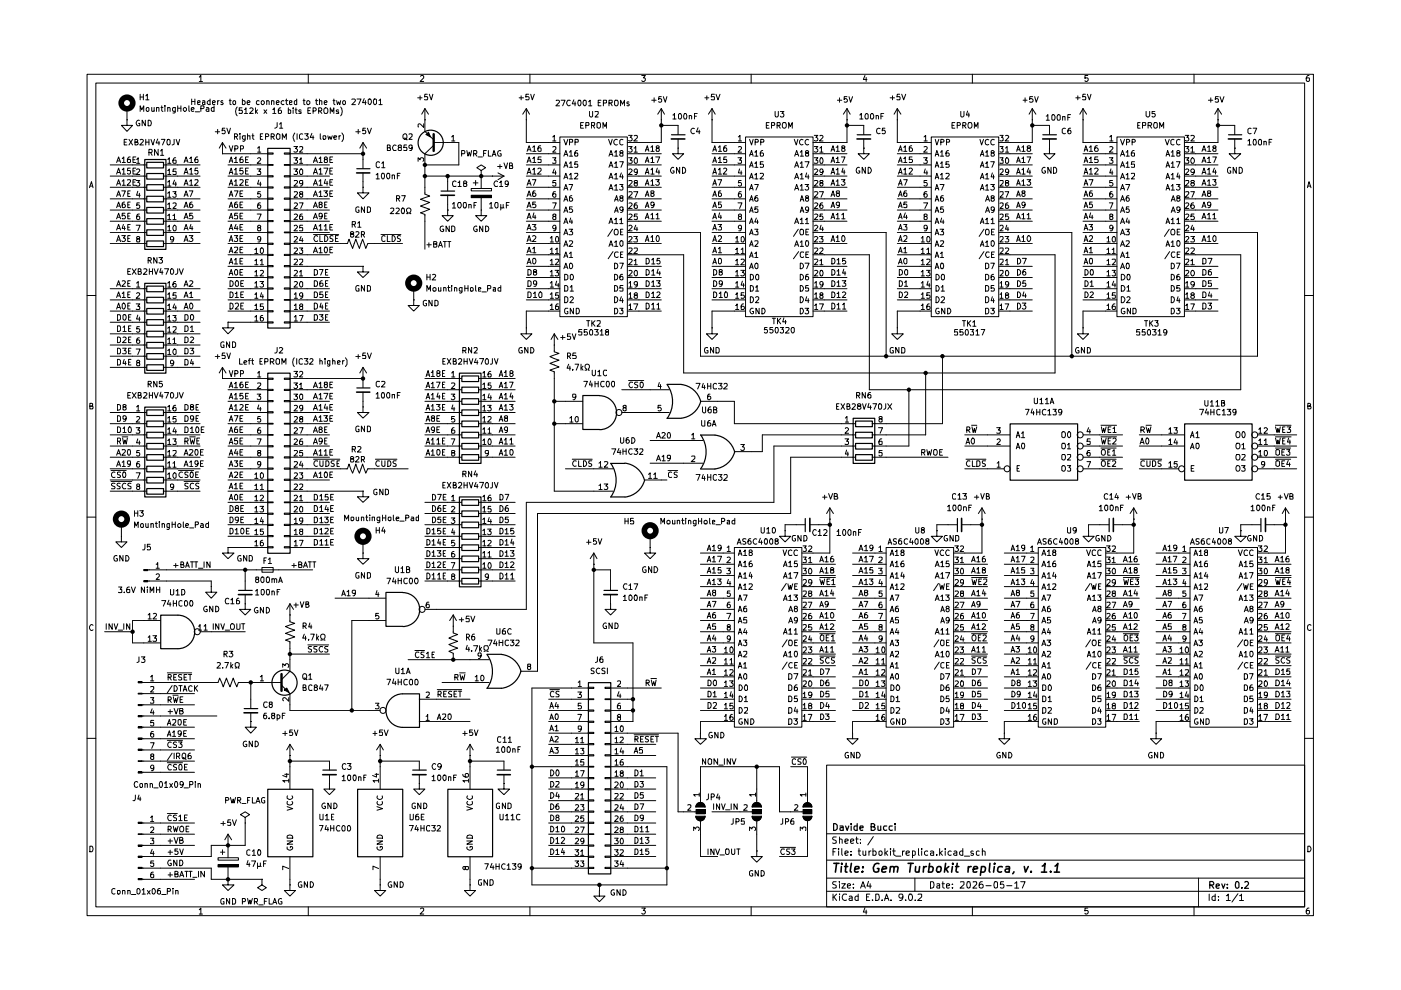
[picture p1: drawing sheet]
<svg xmlns="http://www.w3.org/2000/svg" width="297mm" height="210mm" viewBox="0 0 297 210" stroke-linecap="round" stroke-linejoin="round" font-family="sans-serif">
<g fill="none" stroke="#000" stroke-width=".21">
<path d="M18.5 15.7h260v178.4h-260zM20.3 17.6h256.3v174.7h-256.3zM29.7 20v1.2M30.4 20v1.2M42.2 16.3l.4-.3v1.3M42.2 17.3h.7M65.4 15.7v1.9M89.2 16.2l.1-.2h.4l.1 .2v.3l-.7 .8h.7M90.6 20h-.5l-.1 .6 .6-.1v.7l-.6-.1M91 20l.4 1.2 .4-1.2M112.1 20h-.6v.6l.5-.1 .2 .2v.3l-.2 .2-.5-.1M112.4 15.7v1.9"/>
<path d="M112.5 20l.4 1.2 .4-1.2M136.1 16h.7l-.4 .5 .4 .2v.3l-.2 .3h-.4l-.1-.2M151.5 20h-.6l-.1 .6 .6-.1 .1 .6h-.7M151.8 20l.4 1.2 .5-1.2M159.3 15.7v1.9M183.4 16l-.4 .8h.8M183.6 16.4v.9M190.8 20h-.6v.6l.6-.1v.7l-.6-.1M191.2 20l.4 1.2 .4-1.2M206.2 15.7v1.9M230.1 20h-.5l-.1 .6 .6-.1v.7l-.6-.1M230.5 20l.5 1.2 .3-1.2"/>
<path d="M230.6 16h-.6v.6l.5-.1 .2 .2v.3l-.2 .3-.5-.2M253.2 15.7v1.9M277.5 16h-.2a.93 .93 0 0 0-.3 1.2l.5 .1 .1-.2v-.5l-.6-.1-.1 .2M19 39.8l.4-1.3 .3 1.3M19.1 39.5h.5M23.4 35h7.7M23.4 37.3h7.7M23.4 39.7h7.7M24.7 39.3l.4-1.2 .5 1.2M24.7 36.9l.4-1.3 .5 1.3M24.7 34.5l.4-1.2 .5 1.2M24.9 38.9h.5"/>
<path d="M24.9 36.6h.5M24.9 34.1h.5M25.9 38.4l.3-.3v1.2M25.9 36l.3-.4v1.3M25.9 33.6l.3-.3v1.2M25.9 39.3h.7M25.9 36.9h.7M25.9 34.5h.7M26.3 30.1h.5M26.9 25.4v1.2h1.2l-1.2 1.3-1.2-1.3h1.2M26.9 25.4h.1M26.9 29.5h-.6v1.2h.6"/>
<path d="M26.9 23v2.4M27 38.2l.6-.1 .1 .3-.8 .9h.8M27.3 29.5l.8 1.2M27.6 35.6h-.5l-.1 .6h.6v.6l-.4 .1-.2-.2M27.6 33.3h-.3a.93 .93 0 0 0-.2 1.2h.5l.1-.5-.1-.2h-.5l-.1 .2M28.1 29.5l-.8 1.2M28.2 38.6h.4M28.2 36.2h.4M28.2 33.9h.4M28.6 30.1h.5v-.5l-.5-.1v1.2h.4l.3-.4-.3-.2M28.8 38.1h-.6v1.2h.6M28.8 35.6h-.6v1.3h.6"/>
<path d="M28.8 33.3h-.6v1.2h.6M28.9 38.3h.7l-.4 .4 .4 .2-.1 .5-.5 .1-.1-.2M29 33.8l.3-.4v1.2M29 36l.4-.2 .2 .4-.7 .8h.7M29 34.6h.6M29.5 25.6v-.1a.66 .66 0 0 0-.6 .5 .66 .66 0 0 0 .2 .7l.5-.1v-.4h-.2M29.7 29.6l.4-.1 .3 .4-.8 .8h.8M29.7 23.6v-1.2l.4 .9 .4-.9v1.2M29.7 20.6h.7M30.8 25.5v1.2l-.7-1.2v1.2M30.9 20.3l.3-.3v1.2M30.9 30.1h.7"/>
<path d="M30.9 29.5v1.2M30.9 21.2h.7M31.1 22.9l.3-.1 .2 .1v.6l-.2 .1-.4-.2zM31.4 25.5a.66 .66 0 0 1 .7 .4 .66 .66 0 0 1-.3 .8h-.4zM31.6 32.3h.5l.2-.1v-.4l-.2-.1h-.5v1.2M31.6 29.5v1.2M31.9 32.3l.4 .6M32 29.5l.4 1.2 .4-1.2M32.2 22.8v.7l.3 .1 .2-.1M32.7 22.8v.8M33.2 22.9l.2-.1 .3 .1v.7M33.2 22.8v.8"/>
<path d="M33.4 29.5l-.3 .8h.8M33.5 31.7v1.2l-.7-1.2v1.2M33.7 30v.7M34 32l.4-.3v1.2M34 32.9h.7M34.1 22.8h.4M34.2 29.5h.8l-.5 1.2M34.3 22.4v1.1l.2 .1M34.6 35h7.8M34.6 37.3h7.8M34.6 39.7h7.8M35 22.4v.1"/>
<path d="M35 22.8v.8M35.5 29.6h.5l.1 .9a.35 .35 0 0 1-.5 .2 .35 .35 0 0 1-.2-.4zM35.6 33.8l.3-.4v1.2M35.6 36.2l.3-.4v1.2M35.6 38.6l.3-.3v1.2M35.6 22.9l.1-.1 .4 .1v.7M35.6 39.5h.6M35.6 34.6h.6M35.6 37h.6M35.6 22.8v.8M36.9 29.5v1.1l-.4 .1M37 38.2l-.3 .8h.7"/>
<path d="M37.2 22.8v1l-.2 .2h-.3M37.2 22.9l-.4-.1-.2 .2 .1 .5h.5M37.3 33.4l-.5 .2-.1 .9 .1 .1 .5-.1v-.5h-.5l-.1 .1M37.3 38.6v.9M37.3 35.8h-.6v.6l.6-.1v.6h-.6M37.3 29.5l.5 1.2 .3-1.2M37.7 22.4v1.2M37.7 22.9h.7M38.4 22.4v1.2M38.9 23l.4-.2 .2 .2v.4l-.4 .2-.2-.2zM39 39.3l.5-1.2 .4 1.2M39 34.5l.5-1.2 .4 1.2"/>
<path d="M39 36.9l.5-1.3 .4 1.3M39.2 38.9h.5M39.2 36.6h.5M39.2 34.1h.5M40 22.4v1.1l.2 .1M40.2 38.4l.4-.3v1.2M40.2 33.6l.4-.3v1.2M40.2 36l.4-.4v1.3M40.2 39.3h.7M40.2 36.9h.7M40.2 34.5h.7M40.6 23.2l.5-.1-.1-.3-.4 .1v.6l.1 .1 .4-.1"/>
<path d="M40.6 21v1.2M40.6 21.5h.7M41.3 38.2l.6-.1 .1 .3-.8 .9h.8M41.3 21v1.2M41.4 23.7h.9M41.9 33.3h-.2a.93 .93 0 0 0-.3 1.2h.5l.1-.5-.1-.2h-.5l-.1 .2M41.9 35.6h-.5l-.1 .6h.6v.6l-.4 .1-.2-.2M41.9 21.8l.5-.1v-.3h-.5v.7h.5M42.6 23l.6-.1v-.5h-.6v1.2M42.9 21.4h.5v.8M43.4 21.7l-.5 .1v.3h.5M43.8 22.9l.3-.1 .2 .1v.7"/>
<path d="M44.3 23.1h-.4l-.2 .2 .2 .3 .4-.1M44.5 21.4l-.3-.1-.3 .3v.3l.3 .3 .3-.1M44.5 21v1.2M45 21.8l.6-.1-.1-.4-.5 .2v.5l.2 .2 .4-.1M45.4 22.9l-.4-.1-.2 .2 .1 .5h.5M45.4 22.4v1.2M45.6 27.9h1M46.1 21.3v.9M46.1 27.4v1M46.5 21.3l-.4 .3M47.2 32.6h.1M47.2 30.2v2.4"/>
<path d="M47.2 30.2l-.7 1.2M47.2 30.2l.7 1.2M47.2 32.6h9.5M47.2 21.4l-.2-.1-.2 .3 .5 .4-.1 .2-.4-.1M47.7 27.2h-.5l-.1 .6 .1-.2 .5 .1v.6h-.6M48.1 27.2l.4 1.2 .4-1.2M48.3 35h8.4M48.3 37.3h8.4M48.3 39.7h8.4M48.6 34.5l.4-1.2 .4 1.2M48.6 30.9l.4 1.2 .4-1.2M48.6 36.9l.4-1.3 .4 1.3"/>
<path d="M48.6 39.3l.4-1.2 .4 1.2M48.6 21.3h.4M48.7 38.9h.6M48.7 36.6h.6M48.7 34.1h.6M48.8 21v1.1l.2 .1M49.4 21.4l.4-.1 .2 .2v.5l-.2 .2-.4-.3zM49.7 33.6h.2l.1-.3v1.2M49.7 36h.2l.1-.4v1.3M49.7 38.4l.3-.3v1.2M49.7 29h.5l.2-.2-.1-.4h-.6v1.1M49.7 39.3h.7"/>
<path d="M49.7 36.9h.7M49.7 34.5h.7M49.8 31.6l.6-.1v-.5l-.6-.1v1.2M50 29l.4 .5M50.3 22.7a1.44 1.44 0 0 0 0 1.9M50.9 38.2l.5-.1 .2 .3-.8 .9h.8M50.9 28.4h.1M50.9 28.8v.7M51 31.6l.6-.1v-.5l-.6-.1v1.2M51.3 22.9h-.6v.6l.6-.1v.6h-.6M51.4 33.3l-.3 .1-.2 .2v.8l.5 .1 .2-.2v-.3l-.2-.2h-.4l-.1 .2M51.4 21.4l.3-.1 .3 .3-.1 .5h-.5"/>
<path d="M51.4 21v1.2M51.5 35.6h-.6v.6h.5l.2 .5-.3 .2-.4-.2M51.8 23.2h.2l.2-.3v1.1M51.8 24h.7M52 29.5a.36 .36 0 0 1-.6-.2l.1-.5h.5v.9l-.3 .3-.2-.1M52.1 38.6h.4M52.1 36.2h.4M52.1 33.9h.4M52.4 21.8l.6-.1-.2-.4-.4 .2v.5l.2 .2 .3-.1M52.5 28.9l.5-.1v.7M52.5 28.4v1.1M52.7 33.3h-.6v1.2h.6"/>
<path d="M52.7 35.6h-.6v1.3h.6M52.7 38.1h-.6v1.2h.6M53 23l.4-.1 .3 .3-.8 .8h.8M53.4 28.8h.4M53.6 28.4v1l.2 .1M54.2 22.9v1.1M54.3 23.6l.3 .4M54.5 35.8h.8l-.4 .5h.3v.7l-.7-.1M54.6 31.4l.3-.3v1.2M54.6 33.6l.4-.2 .3 .4-.8 .8h.8M54.6 32.3h.7M54.6 23.3l-.4 .4"/>
<path d="M54.9 38.2l-.3 .8h.8M54.9 21.4l-.3-.1-.2 .3v.5h.5M55.2 38.6v.9M55.2 29h.3M55.5 21.4l.3-.1 .2 .3v.3l-.2 .3-.4-.3zM55.7 28.4h-.5v1.1h.5M56 23.3l.6 .7M56.3 29h.5l.2-.2-.1-.4h-.6v1.1M56.6 21.5l.1-.2 .4 .2v.7M56.6 21.3v.9M56.6 23.3l-.6 .7M56.7 32.4h1.2v.3h-1.2z"/>
<path d="M56.7 34.9h1.2v.2h-1.2zM56.7 37.3h1.2v.2h-1.2zM56.7 39.6h1.2v.3h-1.2zM57.5 29h.5l.2-.2-.1-.4h-.6v1.1M57.6 21.5l.1-.2 .4 .1v.8M57.6 21.3v.9M57.7 29l.5 .5M57.8 23.2h.2l.2-.3v1.1M57.8 24h.7M58.6 21.8l.6-.1-.2-.4-.4 .2v.5l.2 .2 .3-.1M58.8 26v.8l-.5 .4M58.8 28.4l.6 .1v.9l-.6 .1a.78 .78 0 0 1 0-1.1z"/>
<path d="M59.3 26.3l.3-.3v1.2M59.3 27.2h.6M59.5 22.9h-.3l-.2 .3v.8h.5l.2-.1v-.4l-.2-.1h-.4l-.1 .1M59.9 29.5v-1.1l.4 .8 .4-.8v1.1M60.2 21.4l-.3-.1-.3 .3v.3l.3 .3 .3-.1M60.3 32.4h1.2v.3h-1.2zM60.3 34.9h1.2v.2h-1.2zM60.3 37.3h1.2v.2h-1.2zM60.3 39.6h1.2v.3h-1.2zM60.5 21.3h.5M60.7 21v1l.3 .2M61.1 22.9v1.1h.5v-.6h-.5"/>
<path d="M61.4 21.8l.5-.1v-.3h-.5v.7h.5M61.5 35h8.4M61.5 37.3h8.4M61.5 39.7h8.4M61.5 32.6h15.5M62.1 22.9v.1M62.1 23.3v.7M62.3 31.1h.8l-.4 .4 .4 .2-.1 .5h-.7M62.3 33.4h.8l-.4 .6 .4 .1v.4l-.2 .1-.6-.1M62.3 35.8h.8l-.4 .5 .4 .2v.3l-.2 .2-.6-.1M62.4 38.4l.5-.1 .2 .3-.8 .9h.8M62.5 28.2a1.32 1.32 0 0 0 0 1.8"/>
<path d="M62.6 23.3h.4M62.7 22.9v1l.3 .1M62.9 21.4l-.3-.1-.2 .2v.5l.2 .2 .3-.1M62.9 21v1.2M63 28.4v1.1M63.5 31.2h.7v.4l-.7 .7h.7M63.5 33.8h.2l.1-.4v1.2M63.5 34.6h.7M63.7 35.9l.2-.1 .3 .3v.7l-.2 .2h-.3l-.2-.4zM63.8 23.4l-.3-.1-.2 .2 .2 .2h.3v.3h-.5M64.2 38.8l-.1 .1h-.4l-.2-.1v-.4l.2-.1 .5 .1v.7l-.2 .3-.3 .1M64.2 28.4a.45 .45 0 0 0-.7 .2v.7a.45 .45 0 0 0 .7 .2"/>
<path d="M64.3 21.3h.4M64.4 21v1.1l.3 .1M64.6 28.4h.8l-.5 .4 .5 .2-.1 .5h-.7M65.1 21.4l.3-.1 .3 .3v.3l-.3 .3-.4-.3zM65.3 23.5h.4M65.9 22.9h-.6v1.1h.6M66.1 28.3l-.3 .8h.7M66.4 23.5h.6v-.6h-.6v1.1M66.4 28.8v.7M66.5 39.3l.4-1.2 .4 1.2M66.5 34.5l.4-1.2 .4 1.2M66.5 36.9l.4-1.3 .4 1.3"/>
<path d="M66.5 38.9h.6M66.5 36.6h.6M66.5 34.1h.6M66.9 21.3h.5M67.1 21v1l.3 .2M67.6 23.5h.6v-.6h-.6v1.1M67.6 38.4l.4-.3v1.2M67.6 33.6l.4-.3v1.2M67.6 36l.4-.4v1.3M67.6 39.3h.7M67.6 36.9h.7M67.6 34.5h.7"/>
<path d="M67.7 21.5l.2-.2 .3 .1v.8M67.7 21v1.2M67.8 23.5l.4 .5M67.9 28.4v1l.2 .1M68.5 28.9l.5-.1v.7h-.5zM68.7 35.6h.8l-.5 1.3M68.7 21.8l.6-.1-.1-.4-.5 .2v.5l.2 .2 .4-.1M68.7 23l.3-.1h.3a.87 .87 0 0 1 0 1.1h-.5l-.1-.3zM69 38l-.3 .9h.8M69 33.8h-.2a.31 .31 0 0 1 .1-.4 .31 .31 0 0 1 .4 0v.4l-.5 .1v.6h.5l.1-.2-.1-.4-.1-.1M69.3 38.4v.9M69.5 28.8l.2 .7 .2-.5 .3 .5 .2-.7"/>
<path d="M69.9 38.6h.5M69.9 36.2h.5M69.9 33.9h.5M70 24v-1.1l.4 .8 .4-.8v1.1M70.5 38.1h-.6v1.2h.6M70.5 33.3h-.6v1.2h.6M70.5 35.6h-.6v1.3h.6M70.6 21.3h.4M70.8 21v1l.2 .2M70.8 29.1l.6-.1-.1-.2h-.4l-.1 .2v.4l.2 .1h.3M71.4 21.3l.1 .9 .3-.6 .3 .6 .1-.9M71.8 23.4l-.3-.1-.2 .2 .2 .2h.3v.3h-.5"/>
<path d="M71.9 28.8v.7M72.2 22.7a1.44 1.44 0 0 1 0 1.9M72.2 28.8h-.2l-.1 .2M72.5 28.2l.3 .5v.8l-.3 .5M72.7 21.4l.4-.1 .1 .2v.5l-.1 .2-.5-.3zM74.6 21.1l.6-.1 .2 .2-.1 .3-.7 .7h.8M75.4 27.9h1M75.7 21h.8l-.5 1.2M75.9 27.4v1M77 32.6h.1M77 39.7v1.2h1.2l-1.2 1.3-1.2-1.3h1.2M77 39.7h.1"/>
<path d="M77 30.2v5.5M77 36.7v3M77 30.2l-.7 1.2M77 30.2l.7 1.2M77.2 20.9l-.3 .9h.7M77.5 27.2h-.5l-.1 .6 .1-.2 .5 .1v.6h-.6M77.5 21.3v.9M77.9 27.2l.4 1.2 .4-1.2M78.1 21.2l.1-.2a.6 .6 0 0 1 .6 .4 .6 .6 0 0 1-.2 .7l-.3 .1-.2-.3zM79.2 21.1l.5-.1 .1 .2v.7l-.2 .3-.4-.2zM79.8 37.1l.3-.4v1.2M79.8 37.9h.6"/>
<path d="M80.3 21.3l.4-.3v1.2M80.3 22.2h.7M80.4 34.5l-.3-.2-.3 .3v.8l.3 .2 .3-.2M80.9 36.8l.1-.1a.59 .59 0 0 1 .6 .4 .59 .59 0 0 1-.2 .7l-.1 .1-.4-.1zM80.9 34.6l.4-.3v1.3M80.9 35.6h.7M82.1 36.7h.4l.1 .2v.8l-.2 .2a.71 .71 0 0 1-.3-1.2zM82.1 31.3l.6-.1v-.4l-.6-.1v1.2h.6l.1-.3-.2-.3M83.1 37.3l.2-.2 .4 .1v.7M83.1 37.1v.8M84 30.8l-.3-.1a.67 .67 0 0 0-.5 .5 .67 .67 0 0 0 .3 .7l.5-.1M84.2 37.3h.5"/>
<path d="M84.7 31.2l-.3-.1 .1-.3h.6l-.1 .4h-.3l-.3 .3 .2 .4 .5-.1v-.4l-.2-.2M84.8 36.7h-.6v1.2M85.5 28.5l.5-.1a.65 .65 0 0 1 .3 .6 .65 .65 0 0 1-.5 .5h-.1a.67 .67 0 0 1-.2-1zM85.7 29.3h.2l.5 .3M86.2 30.7h-.5l-.1 .6 .6-.1v.7l-.6-.1M86.7 28.4h.7v.5l-.7 .6h.7M87.4 31.2v.2a.42 .42 0 0 1-.6 0 .42 .42 0 0 1 0-.6h.6v.9l-.2 .2h-.3M88.6 20.7h.9M88.6 34.2v-.8l.5 .5 .1-.4h.5l.1 .5-.1 .2M89.1 20.3v.9M89.8 26.2v.8l-.8-.8-.4 .2 .1 .5M90.1 25.4h.1"/>
<path d="M90.1 37.3h16.7M90.1 23l-.7 1.2M90.1 23l.7 1.2M90.1 23v4.9l1.8 1.7M90.3 28.5l.5-.5 .5 1zM91.9 30.8l-1.8 1.8v8.5l1 .5-1.9 .6 1.9 .7-1.9 .8 1.9 .7-1.9 .7 .9 .4v7.3M91.9 30.2h5.4v4.8h-7.2M94.9 37.3v3.2M95.8 29l.3-.3v1.2M95.8 29.9h.6M96.7 38.5l-.3-.1a.67 .67 0 0 0-.5 .5 .67 .67 0 0 0 .3 .6h.5M97.1 38.7h.2l.2-.3v1.1"/>
<path d="M97.1 39.5h.7M97.9 32.6h.5l.2-.2v-.3l-.2-.2h-.5v1.2M98.5 38.9l-.2-.1 .2-.4h.2l.3 .2-.2 .3h-.3l-.2 .1 .1 .5h.4l.2-.4-.3-.2M99 31.9l.2 1.2 .3-.8 .2 .8 .3-1.2M99.9 40h4.3v.5h-4.3zM100.3 38.8h1M100.4 32.6h.5l.2-.2v-.3l-.2-.2h-.5v1.2M100.8 32.6l.3 .5M100.8 38.3v1M101.3 33.3h1M102 36.2l1-.6-1-.6-.9 .6 .9 .6v1.1M102 37.3h.1"/>
<path d="M102 37.3v2.7M102.5 32.5h.5M103.1 31.9h-.6v1.2M103.5 31.9v1.2h.6M104.4 37.3h.1M104.4 33.1l.3-1.2 .5 1.2M104.5 32.8h.6M105.5 38.5l-.3-.1a.67 .67 0 0 0-.5 .5 .67 .67 0 0 0 .3 .6h.5M105.5 35.3h.9M105.6 36.7l1.2 .6M105.9 38.7h.2l.2-.3v1.1M105.9 39.5h.7"/>
<path d="M106 34.9v.8M106.2 32l-.1-.1a.66 .66 0 0 0-.6 .5 .66 .66 0 0 0 .2 .7l.6-.1v-.4h-.3M106.8 34.5l.5 1.2 .3-1.2M106.8 37.3l-1.2 .8M107.8 38.9l-.3 .2h-.2l-.2-.1v-.5l.4-.1 .3 .2-.2 .9h-.4M108 35.1h.6v-.4l-.1-.2h-.5v1.2h.6l.1-.3-.2-.3M110.1 20.7h.9M110.5 20.3v.9M111.6 25.4h.1M111.6 35h7.1M111.6 37.3h7.1M111.6 39.7h7.1"/>
<path d="M111.6 32.6h7.1M111.6 23v7.2h7.1M111.6 23l-.8 1.2M111.6 23l.7 1.2M111.8 39.3l.4-1.2 .4 1.2M111.8 36.9l.4-1.3 .4 1.3M111.8 34.5l.4-1.2 .4 1.2M111.8 32.1l.4-1.2 .4 1.2M111.9 38.9h.5M111.9 36.6h.5M111.9 34.1h.5M111.9 31.7h.5"/>
<path d="M112.9 38.1h.7l-.5 1.2M112.9 36l.4-.4v1.3M112.9 33.6l.4-.3v1.2M112.9 31.2l.4-.3v1.2M112.9 36.9h.7M112.9 34.5h.7M112.9 32.1h.7M114 35.8l.2-.2h.4l.1 .2v.4l-.7 .7h.7M114.6 30.9l-.4 .1a.94 .94 0 0 0 0 1.1l.5-.1v-.5l-.4-.2-.3 .3M114.7 33.3h-.6l-.1 .6 .6-.1 .1 .6h-.7M117.2 29l.3-.3v1.2M117.2 31.2h.7v.4l-.7 .7h.7"/>
<path d="M117.2 33.4h.7l-.4 .6h.4v.5h-.7M117.2 29.9h.7M117.5 35.8l-.3 .9h.7M117.8 36.2v.8M117.9 38.3h-.6l-.1 .5h.7v.5l-.2 .2h-.4l-.1-.2M117.9 21.3h.5l.2 .3-.7 .8h.7M118.7 29h14.3v38.1h-14.3zM119 21.3h.8l-.5 1.1M119.5 29.5l.5 1.2 .4-1.2M119.5 33.1l.5-1.2 .4 1.2M119.5 35.5l.5-1.2 .4 1.2M119.5 37.9l.5-1.2 .4 1.2"/>
<path d="M119.7 32.8h.5M119.7 35.1h.5M119.7 37.6h.5M119.7 40h.5M120.7 39.1h.7l-.5 1.2M120.7 30.1h.6l.1-.5-.7-.1v1.2M120.7 32.3l.4-.4v1.2M120.7 34.6l.4-.3v1.2M120.7 37.1l.4-.4v1.2M120.7 33.1h.7M120.7 35.5h.7M120.7 37.9h.7"/>
<path d="M120.9 21.3h-.5a.67 .67 0 0 0-.3 .6 .67 .67 0 0 0 .6 .5l.2-.1M121.7 21.2l-.4 .8h.8M121.8 36.8l.6-.1 .1 .4-.7 .8h.7M121.9 30.1h.6l.1-.5-.7-.1v1.2M121.9 21.6v.8M122.4 31.9h-.2a.93 .93 0 0 0-.3 1.2h.5l.1-.5-.1-.2h-.5l-.1 .2M122.4 34.3h-.5l-.1 .6 .6-.1v.7l-.6-.1M122.6 21.3h.1a.59 .59 0 0 1 .5 .3 .59 .59 0 0 1-.1 .7l-.2 .1-.3-.1zM123.1 26.6h.4M123.7 26h-.6v1.2h.6M123.8 21.3h.3l.2 .1v.8l-.3 .2a.71 .71 0 0 1-.2-1.1zM124.2 26.6h.6v-.6h-.6v1.2"/>
<path d="M124.8 21.6l.3-.3v1.1M124.8 22.4h.7M125 23.6v1l.2 .2 .4-.2v-1M125.4 26.6h.6l.1-.5-.7-.1v1.2M125.7 26.6l.4 .6M126.2 23.7h.6v.4l-.6 .7h.6M126.6 26.2l.1-.2h.5l.1 .2a.65 .65 0 0 1-.5 1l-.2-.2zM126.8 21.8h.5M127.4 21.3h-.6v1.1h.6M127.8 27.2v-1.2l.5 .8 .3-.8v1.2M127.9 21.8h.7v-.5h-.7v1.1M129 29.5l.5 1.2 .3-1.2"/>
<path d="M129.1 33.1l.4-1.2 .5 1.2M129.1 35.5l.4-1.2 .5 1.2M129.1 37.9l.4-1.2 .5 1.2M129.1 21.8h.7v-.5h-.7v1.1M129.3 32.8h.5M129.3 35.1h.5M129.3 37.6h.5M129.3 40h.5M129.5 21.8l.3 .6M130.3 32.3l.3-.4v1.2M130.3 34.6l.3-.3v1.2M130.3 37.1l.3-.4v1.2"/>
<path d="M130.3 39.5l.3-.4v1.2M130.3 21.4l.2-.1h.4a.86 .86 0 0 1-.1 1.1l-.5-.1zM130.3 33.1h.7M130.3 35.5h.7M130.3 37.9h.7M130.9 29.6a.55 .55 0 0 0-.8 .5 .55 .55 0 0 0 .8 .5M131.4 34.3h.8l-.5 1.2M131.4 39.1h.7l-.4 .4 .4 .1v.5l-.2 .2h-.3l-.2-.2M131.6 22.4v-1.1l.4 .8 .4-.8v1.1M131.7 32.4l-.3-.2 .3-.3h.2l.2 .4-.4 .1-.3 .3v.2l.2 .2h.4l.1-.5-.2-.2M131.7 36.7l-.3 .8h.8M132 37.1v.8"/>
<path d="M132.1 29.6a.45 .45 0 0 0-.7 .2v.7a.45 .45 0 0 0 .7 .1M133 35h7.2M133 37.3h7.2M133 39.7h7.2M133 32.6h7.2M133.3 28.7h.7l-.4 .4 .4 .3-.1 .4h-.6M133.3 31.1h.7l-.4 .4 .4 .2-.1 .5h-.6M133.3 33.4h.7l-.4 .6 .4 .1v.4l-.1 .1-.6-.1M133.4 36l.4-.2 .2 .4-.7 .8h.7M133.4 38.4l.5-.1 .1 .3-.7 .9h.7M133.4 21.7h-.5v.2l.4 .1 .1 .3-.1 .1h-.4M134.5 28.8h.6v.4l-.7 .7h.7"/>
<path d="M134.5 31.4l.3-.3v1.2M134.5 32.3h.6M134.6 33.5l.3-.1 .2 .3v.8l-.1 .1h-.4l-.1-.4zM134.7 38.8l-.2-.4 .1-.1h.4l.1 .3-.6 .3v.3l.2 .3 .4-.2v-.4l-.1-.1M135.1 36.3v.2l-.4 .1-.2-.1v-.4l.2-.3 .4 .2v.7l-.1 .3h-.4M136.8 32.1l.4-1.2 .4 1.2M136.8 34.5l.4-1.2 .4 1.2M136.8 39.3l.4-1.2 .4 1.2M136.8 36.9l.4-1.3 .4 1.3M136.9 38.9h.6M136.9 36.6h.6M136.9 34.1h.6"/>
<path d="M136.9 31.7h.6M138 31.2l.3-.3v1.2M138 33.6l.3-.3v1.2M138 38.4l.3-.3v1.2M138 36l.3-.4v1.3M138 39.3h.7M138 36.9h.7M138 34.5h.7M138 32.1h.7M138.2 21.3h.9M138.7 20.7v1M139 33.3h.9l-.5 1.2"/>
<path d="M139 38.1h.8l-.4 .4 .3 .1v.6l-.5 .1-.2-.2M139.4 31.4l-.3-.2a.35 .35 0 0 1 .3-.3 .35 .35 0 0 1 .4 .3l-.1 .1a.51 .51 0 0 0-.5 .3 .51 .51 0 0 0 0 .5h.5l.1-.4-.3-.3M139.4 35.6l-.3 .9h.8M139.7 36.1v.8M140.2 25.4h.1M140.2 20.5h-.5l-.1 .6 .2-.2 .4 .1v.6h-.6M140.2 23v7.2h-7.2M140.2 26.6h3.6v1.9M140.2 23l-.8 1.2M140.2 23l.7 1.2M140.6 20.5l.5 1.2 .3-1.2M142.7 24.4h.1l.2-.4v1.2"/>
<path d="M142.7 25.2h.6M142.8 35.6l-.1-.1a.6 .6 0 0 0-.5 .6 .6 .6 0 0 0 .6 .6l.1-.5h-.2M143.8 31.4v1.2h1.1l-1.1 1.2-1.2-1.2h1.2M143.8 31.4h.1M143.8 29.5v1.9M143.8 24.3l.3-.3a.71 .71 0 0 1 .3 1.2h-.4l-.2-.1zM144.1 35.5v1.2l-.7-1.2v1.2M144.7 35.5a.64 .64 0 0 1 .7 .6 .64 .64 0 0 1-.7 .6zM145.2 24a.75 .75 0 0 1 .3 1.2h-.4l-.2-.4 .1-.6zM146.1 24.6l.4-.1 .1 .1v.6M146.1 24.5v.7M147.2 27.3a.55 .55 0 0 0-.7 .5 .55 .55 0 0 0 .7 .5"/>
<path d="M147.2 24.6h.5M147.8 24h-.6v1.2M148 27.1l-.3 .8h.7M148.3 27.6v.8M149.4 20.7h.9M149.9 20.3v.9M151 25.4h.1M151 35h7.1M151 37.3h7.1M151 39.7h7.1M151 32.6h7.1M151 23v7.2h7.1"/>
<path d="M151 23l-.8 1.2M151 23l.6 1.2M151.1 32.1l.5-1.2 .3 1.2M151.1 39.3l.5-1.2 .3 1.2M151.1 34.5l.5-1.2 .3 1.2M151.1 36.9l.5-1.3 .3 1.3M151.2 38.9h.6M151.2 36.6h.6M151.2 34.1h.6M151.2 31.7h.6M152.2 38.1h.8l-.5 1.2M152.3 31.2l.4-.3v1.2"/>
<path d="M152.3 33.6l.4-.3v1.2M152.3 36l.4-.4v1.3M152.3 36.9h.7M152.3 34.5h.7M152.3 32.1h.7M153.4 35.8l.4-.2 .3 .4-.8 .9h.8M154 30.9l-.4 .1-.2 .4 .1 .7h.5v-.7l-.3-.1-.3 .3M154 33.3h-.5l-.1 .6 .6-.1v.7l-.6-.1M156.5 33.4h.7l-.4 .6h.3v.6l-.6-.1M156.5 29l.4-.3v1.2M156.5 31.2l.5-.1 .2 .3-.7 .9h.7M156.5 29.9h.7"/>
<path d="M156.8 35.8l-.3 .9h.8M157.1 38.3h-.5l-.1 .5h.6v.6l-.4 .1-.2-.2M157.1 36.2v.8M158.1 29h14.3v38.1h-14.3zM158.9 29.5l.4 1.2 .4-1.2M158.9 33.1l.4-1.2 .4 1.2M158.9 35.5l.4-1.2 .4 1.2M158.9 37.9l.4-1.2 .4 1.2M159 32.8h.6M159 35.1h.6M159 37.6h.6M159 40h.6"/>
<path d="M160 32.3h.2l.2-.4v1.2M160 34.6h.2l.2-.3v1.2M160 37.1l.4-.4v1.2M160 39.1h.8l-.5 1.2M160 33.1h.7M160 35.5h.7M160 37.9h.7M160.1 30.1h.6v-.5l-.6-.1v1.2M161.2 36.8l.5-.1 .2 .4-.8 .8h.8M161.3 30.1h.6v-.5l-.6-.1v1.2M161.7 31.9l-.3 .1-.2 .3v.7l.5 .1 .2-.2v-.3l-.2-.2h-.4l-.1 .2M161.8 34.3h-.6v.6l.5-.1 .2 .2v.3l-.2 .2-.5-.1"/>
<path d="M162.5 26.6h.4M163.1 26h-.6v1.2h.6M163.6 26.6h.6v-.6h-.6v1.2M164.3 23.6v1l.3 .2 .4-.2v-1M164.8 26.6h.6v-.6h-.6v1.2M165 26.6l.4 .6M165.4 23.6h.8l-.4 .4 .4 .3-.1 .4-.5 .1-.2-.2M166 26h.5l.2 .4-.1 .6-.2 .2-.4-.1-.1-.3zM167.2 27.2v-1.2l.4 .8 .4-.8v1.2M168.4 29.5l.4 1.2 .4-1.2M168.5 33.1l.4-1.2 .4 1.2M168.5 35.5l.4-1.2 .4 1.2"/>
<path d="M168.5 37.9l.4-1.2 .4 1.2M168.7 32.8h.5M168.7 35.1h.5M168.7 37.6h.5M168.7 40h.5M169.7 32.3l.3-.4v1.2M169.7 34.6l.3-.3v1.2M169.7 37.1l.3-.4v1.2M169.7 39.5l.3-.4v1.2M169.7 33.1h.6M169.7 35.5h.6M169.7 37.9h.6"/>
<path d="M170.3 29.6a.55 .55 0 0 0-.8 .5 .55 .55 0 0 0 .8 .5M170.7 34.3h.8l-.5 1.2M170.7 39.1h.8l-.5 .4 .5 .3-.1 .4-.5 .1-.2-.2M171 32.4h-.1a.31 .31 0 0 1 0-.4 .31 .31 0 0 1 .5 .1v.3h-.4l-.2 .3 .1 .4h.5l.1-.2v-.2l-.3-.3M171 36.7l-.2 .8h.7M171.4 37.1v.8M171.5 29.6a.55 .55 0 0 0-.8 .5 .55 .55 0 0 0 .8 .5M172.4 35h7.2M172.4 37.3h7.2M172.4 39.7h7.2M172.4 32.6h7.2M172.6 28.7h.8l-.4 .4 .4 .3-.1 .4h-.7"/>
<path d="M172.6 31.1h.8l-.4 .4 .4 .2-.1 .5h-.7M172.6 33.4h.8l-.4 .6 .4 .1v.4l-.2 .1-.6-.1M172.7 36l.4-.2 .3 .4-.8 .8h.8M172.7 38.4l.5-.1 .2 .3-.8 .9h.8M173.8 28.8l.4-.1 .3 .3-.8 .9h.8M173.8 31.4l.4-.3v1.2M173.8 32.3h.7M174.1 33.4a.75 .75 0 0 1 .2 1.2h-.3l-.2-.4 .1-.6zM174.1 38.8l-.3-.3 .1-.2h.5v.4l-.5 .1-.1 .1 .1 .5 .2 .1 .4-.3-.1-.4h-.2M174.5 36.3a.35 .35 0 0 1-.3 .3 .35 .35 0 0 1-.4-.3l.1-.4h.5v.8l-.2 .3h-.3M176.2 34.5l.4-1.2 .4 1.2M176.2 36.9l.4-1.3 .4 1.3"/>
<path d="M176.2 39.3l.4-1.2 .4 1.2M176.2 32.1l.4-1.2 .4 1.2M176.3 38.9h.6M176.3 36.6h.6M176.3 34.1h.6M176.3 31.7h.6M177.3 33.6h.2l.1-.3v1.2M177.3 36h.2l.1-.4v1.3M177.3 38.4l.3-.3v1.2M177.3 31.2l.3-.3v1.2M177.3 39.3h.7M177.3 36.9h.7"/>
<path d="M177.3 34.5h.7M177.3 32.1h.7M177.5 21.3h1M178 20.7v1M178.4 33.3h.8l-.6 1.2M178.4 38.1h.8l-.5 .4 .4 .1 .1 .4-.3 .3h-.3l-.2-.2M178.6 31.4l-.1-.1v-.3h.6v.3l-.6 .3 .1 .5h.4l.2-.2v-.2l-.3-.3M178.7 35.6l-.2 .9h.7M179 36.1v.8M179.6 25.4h.1M179.6 20.5h-.6v.6l.4-.2 .3 .3-.1 .4h-.6M179.6 23v7.2h-7.2"/>
<path d="M179.6 26.6h3.5v1.9M179.6 23l-.8 1.2M179.6 23l.7 1.2M180 20.5l.3 1.2 .5-1.2M182.2 35.6a.61 .61 0 0 0-.7 .2 .61 .61 0 0 0 .1 .8l.3 .1h.3l.1-.5h-.3M182.3 24.4l.3-.4v1.2M182.3 25.2h.7M183.1 31.4v1.2h1.2l-1.2 1.2-1.2-1.2h1.2M183.1 31.4h.1M183.1 29.5v1.9M183.5 35.5v1.2l-.7-1.2v1.2M183.6 24.1l.2-.1 .3 .3v.8l-.2 .1h-.3l-.2-.4z"/>
<path d="M184.1 35.5a.64 .64 0 0 1 .6 .6 .64 .64 0 0 1-.6 .6zM184.6 24.3l.2-.3a.71 .71 0 0 1 .3 1.2h-.4l-.1-.1zM185.8 24.6l.3-.1 .2 .1v.6M185.8 24.5v.7M186.6 27.3l-.2-.1a.6 .6 0 0 0-.6 .6 .6 .6 0 0 0 .6 .6l.2-.1M186.8 24.6h.4M187.4 24h-.6v1.2M187.6 27.2h-.5l-.1 .6 .2-.2 .4 .1v.6h-.6M188.7 20.7h1M189.2 20.3v.9M190.2 25.4h.1M190.2 35h7.2"/>
<path d="M190.2 37.3h7.2M190.2 39.7h7.2M190.2 32.6h7.2M190.2 23v7.2h7.2M190.2 23l-.6 1.2M190.2 23l.8 1.2M190.5 36.9l.4-1.3 .4 1.3M190.5 32.1l.4-1.2 .4 1.2M190.5 39.3l.4-1.2 .4 1.2M190.5 34.5l.4-1.2 .4 1.2M190.6 38.9h.6M190.6 36.6h.6"/>
<path d="M190.6 34.1h.6M190.6 31.7h.6M191.6 36h.2l.1-.4v1.3M191.6 31.2l.3-.3v1.2M191.6 38.1h.8l-.5 1.2M191.6 33.6h.2l.1-.3v1.2M191.6 36.9h.7M191.6 34.5h.7M191.6 32.1h.7M192.8 35.8l.4-.2 .3 .4-.8 .9h.8M193.3 30.9l-.5 .3v.8l.5 .1 .2-.2v-.3l-.3-.3h-.2l-.2 .3M193.4 33.3h-.6v.6l.5-.1 .2 .2v.3l-.2 .2-.5-.1"/>
<path d="M195.8 33.4h.8l-.4 .6h.3v.6l-.7-.1M195.9 29l.4-.3v1.2M195.9 31.2l.4-.1 .3 .3-.8 .9h.8M195.9 29.9h.7M196.2 35.8l-.3 .9h.8M196.5 38.3h-.6v.5h.6v.6l-.4 .1-.2-.2M196.5 36.2v.8M197.4 29h14.4v38.1h-14.4zM198.3 29.5l.3 1.2 .5-1.2M198.3 33.1l.3-1.2 .5 1.2M198.3 35.5l.3-1.2 .5 1.2M198.3 37.9l.3-1.2 .5 1.2"/>
<path d="M198.4 32.8h.6M198.4 35.1h.6M198.4 37.6h.6M198.4 40h.6M199.3 39.1h.9l-.6 1.2M199.4 32.3l.3-.4v1.2M199.4 34.6l.3-.3v1.2M199.4 37.1l.3-.4v1.2M199.4 33.1h.7M199.4 35.5h.7M199.4 37.9h.7M199.5 30.1h.5l.2-.1-.1-.4-.6-.1v1.2"/>
<path d="M200.6 36.8l.5-.1 .2 .4-.8 .8h.8M200.7 30.1h.6v-.5l-.6-.1v1.2M201.1 31.9l-.4 .1-.1 .3v.7l.5 .1 .2-.2v-.3l-.2-.2h-.4l-.1 .2M201.2 34.3h-.6v.6l.5-.1 .2 .2v.3l-.2 .2-.5-.1M201.8 26.6h.5M202.4 26h-.6v1.2h.6M202.9 26.6h.6l.1-.2-.1-.3-.6-.1v1.2M203.7 23.6v1l.2 .2h.2l.3-.2v-1M204.1 26.6h.5l.2-.2-.2-.4h-.5v1.2M204.4 26.6l.4 .6M205.1 23.5l-.2 .9h.7M205.4 26h.5l.2 .8a.46 .46 0 0 1-.6 .4 .86 .86 0 0 1-.1-1.2z"/>
<path d="M205.4 24v.8M206.6 27.2v-1.2l.3 .8 .4-.8v1.2M207.8 29.5l.3 1.2 .4-1.2M207.9 33.1l.4-1.2 .3 1.2M207.9 35.5l.4-1.2 .3 1.2M207.9 37.9l.4-1.2 .3 1.2M207.9 32.8h.6M207.9 35.1h.6M207.9 37.6h.6M207.9 40h.6M209 32.3h.1l.2-.4v1.2M209 34.6h.1l.2-.3v1.2"/>
<path d="M209 37.1l.3-.4v1.2M209 39.5l.3-.4v1.2M209 33.1h.6M209 35.5h.6M209 37.9h.6M209.6 29.6l-.2-.1a.6 .6 0 0 0-.5 .6 .6 .6 0 0 0 .5 .6l.2-.1M210.1 34.3h.7l-.5 1.2M210.1 39.1h.7l-.4 .4 .3 .1 .1 .4-.2 .3h-.4l-.1-.2M210.3 32.4l-.2-.1 .2-.4h.3l.2 .3-.1 .2h-.4l-.2 .2v.4l.6 .1 .1-.4-.2-.3M210.4 36.7l-.3 .8h.7M210.7 37.1v.8M210.8 29.6l-.2-.1a.6 .6 0 0 0-.5 .6 .6 .6 0 0 0 .5 .6l.2-.1"/>
<path d="M211.8 35h7.1M211.8 37.3h7.1M211.8 39.7h7.1M211.8 32.6h7.1M212 28.7h.7l-.4 .4 .4 .2v.5h-.7M212 31.1h.7l-.4 .4 .4 .2v.5h-.7M212 33.4h.7l-.4 .6h.4v.5h-.7M212 36l.2-.2h.3l.2 .2v.3l-.7 .7h.7M212 38.4h.7v.4l-.7 .7h.7M213.2 28.8l.4-.1 .3 .3-.8 .9h.8M213.2 31.4l.3-.3v1.2M213.2 32.3h.7"/>
<path d="M213.4 38.8l-.2-.4 .5-.1 .2 .2-.3 .3-.4 .1v.4l.2 .2h.2l.3-.3v-.3l-.3-.1M213.4 33.4a.71 .71 0 0 1 .3 1.2h-.3l-.2-.1v-.8zM213.9 36.3l-.3 .3-.4-.1v-.5l.4-.2a.81 .81 0 0 1 0 1.2h-.3M215.6 36.9l.3-1.3 .4 1.3M215.6 39.3l.3-1.2 .4 1.2M215.6 34.5l.3-1.2 .4 1.2M215.6 32.1l.3-1.2 .4 1.2M215.6 38.9h.6M215.6 36.6h.6M215.6 34.1h.6M215.6 31.7h.6M216.7 36l.3-.4v1.3"/>
<path d="M216.7 38.4l.3-.3v1.2M216.7 33.6l.3-.3v1.2M216.7 31.2l.3-.3v1.2M216.7 39.3h.6M216.7 36.9h.6M216.7 34.5h.6M216.7 32.1h.6M216.9 21.3h.9M217.3 20.7v1M217.8 38.1h.7l-.4 .4 .3 .1 .1 .4-.2 .3h-.4l-.1-.2M217.8 33.3h.7l-.5 1.2M218 31.4l-.2-.2v-.2h.6v.3l-.4 .1-.2 .3 .1 .4h.5l.1-.2v-.2l-.2-.3"/>
<path d="M218.1 35.6l-.3 .9h.7M218.4 36.1v.8M218.9 25.4h.1M218.9 26.6h3.6v1.9M218.9 23v7.2h-7.1M218.9 23l-.7 1.2M218.9 23l.7 1.2M218.9 20.5h-.5l-.1 .6 .1-.2h.4l.2 .3-.1 .4h-.6M219.4 20.5l.3 1.2 .4-1.2M221.6 35.6a.61 .61 0 0 0-.7 .2 .61 .61 0 0 0 .1 .8l.3 .1h.3l.1-.5h-.3M221.8 24.6l.4-.3v1.2M221.8 25.5h.7"/>
<path d="M222.5 31.4v1.2h1.2l-1.2 1.2-1.2-1.2h1.2M222.5 31.4h.1M222.5 29.5v1.9M222.8 35.5v1.2l-.6-1.2v1.2M223.1 24.4l.3-.1a.84 .84 0 0 1 .1 1.2h-.3l-.2-.2zM223.4 35.5h.3l.3 .3v.6l-.3 .3h-.3zM224.2 24.4l.3-.1 .3 .3v.7l-.2 .2-.4-.1zM225.3 24.8l.5-.1v.8M225.3 24.7v.8M225.9 27.3a.45 .45 0 0 0-.7 .1v.7a.45 .45 0 0 0 .7 .2M226.4 24.9h.4M227 24.3h-.6v1.2"/>
<path d="M227 27.2l-.4 .1-.2 .8a.35 .35 0 0 0 .3 .3 .35 .35 0 0 0 .4-.3l-.1-.4-.2-.1-.4 .3M228.1 20.7h.9M228.5 20.3v.9M229.6 25.4h.1M229.6 35h7.2M229.6 37.3h7.2M229.6 39.7h7.2M229.6 32.6h7.2M229.6 23l-.7 1.2M229.6 23l.8 1.2M229.6 23v7.2h7.2M229.9 34.5l.3-1.2 .4 1.2"/>
<path d="M229.9 36.9l.3-1.3 .4 1.3M229.9 39.3l.3-1.2 .4 1.2M229.9 32.1l.3-1.2 .4 1.2M230 38.9h.5M230 36.6h.5M230 34.1h.5M230 31.7h.5M230.9 38.1h.8l-.5 1.2M231 33.6l.3-.3v1.2M231 36l.3-.4v1.3M231 31.2l.3-.3v1.2M231 36.9h.6"/>
<path d="M231 34.5h.6M231 32.1h.6M232.1 35.8l.1-.2h.4l.2 .3-.7 1h.7M232.7 30.9l-.5 .1a.94 .94 0 0 0 0 1.1h.5l.1-.2v-.3l-.2-.3h-.3l-.2 .3M232.7 33.3h-.5l-.1 .6 .6-.1 .1 .2v.3l-.1 .2-.6-.1M235.2 33.4h.8l-.5 .6 .5 .1v.4l-.2 .1-.6-.1M235.3 29l.3-.3v1.2M235.3 31.2l.4-.1 .3 .3-.8 .9h.8M235.3 29.9h.7M235.5 35.8l-.2 .9h.7M235.8 36.2v.8M235.9 38.3h-.6v.5h.6l.1 .4-.3 .3-.4-.2"/>
<path d="M236.8 29h14.3v38.1h-14.3zM237.6 29.5l.4 1.2 .4-1.2M237.6 33.1l.4-1.2 .4 1.2M237.6 35.5l.4-1.2 .4 1.2M237.6 37.9l.4-1.2 .4 1.2M237.7 32.8h.6M237.7 35.1h.6M237.7 37.6h.6M237.7 40h.6M238.7 39.1h.8l-.5 1.2M238.8 32.3l.3-.4v1.2M238.8 34.6l.3-.3v1.2"/>
<path d="M238.8 37.1l.3-.4v1.2M238.8 33.1h.6M238.8 35.5h.6M238.8 37.9h.6M238.8 30.1h.6l.1-.1-.1-.4-.6-.1v1.2M239.9 36.8h.6v.5l-.6 .6h.6M240 30.1h.5l.2-.1-.1-.4-.6-.1v1.2M240.5 31.9l-.5 .2-.1 .8 .1 .2 .5-.1v-.6h-.5l-.1 .2M240.5 34.3h-.6v.6l.6-.1v.6h-.6M241.2 26.6h.4M241.7 26h-.5v1.2h.5M242.2 26.6h.6l.1-.5-.7-.1v1.2"/>
<path d="M243 23.6v1l.2 .2h.3l.3-.2v-1M243.4 26.6h.6l.2-.2-.1-.3-.7-.1v1.2M243.8 26.6l.4 .6M244.8 26h.4l.2 .2v.8l-.5 .2a.86 .86 0 0 1-.1-1.2zM244.9 23.6h-.6v.5h.6v.5l-.2 .2-.4-.2M245.9 27.2v-1.2l.4 .8 .4-.8v1.2M247.1 29.5l.4 1.2 .4-1.2M247.2 33.1l.4-1.2 .4 1.2M247.2 35.5l.4-1.2 .4 1.2M247.2 37.9l.4-1.2 .4 1.2M247.3 32.8h.6M247.3 35.1h.6"/>
<path d="M247.3 37.6h.6M247.3 40h.6M248.3 32.3l.4-.4v1.2M248.3 34.6l.4-.3v1.2M248.3 37.1l.4-.4v1.2M248.3 39.5l.4-.4v1.2M248.3 33.1h.7M248.3 35.5h.7M248.3 37.9h.7M248.9 29.6a.45 .45 0 0 0-.7 .2v.7a.45 .45 0 0 0 .7 .1M249.4 34.3h.8l-.5 1.2M249.4 39.1h.8l-.4 .4 .3 .1 .1 .4-.3 .3h-.3l-.2-.2"/>
<path d="M249.7 32.4l-.2-.1 .2-.4h.2l.3 .3-.2 .2h-.3l-.2 .2v.4l.5 .1 .2-.4-.3-.3M249.8 36.7l-.3 .8h.7M250 37.1v.8M250.2 29.6l-.3-.1a.6 .6 0 0 0-.5 .6 .6 .6 0 0 0 .5 .6l.3-.1M251.1 35h7.1M251.1 37.3h7.1M251.1 39.7h7.1M251.1 32.6h7.1M251.3 28.7h.8l-.5 .4 .4 .1v.6h-.7M251.3 31.1h.8l-.5 .4 .4 .1v.6h-.7M251.3 33.4h.8l-.5 .6h.4v.6l-.7-.1M251.4 36l.4-.2 .3 .4-.8 .8h.8"/>
<path d="M251.4 38.4l.6-.1 .1 .3-.8 .9h.8M252.5 28.8l.5-.1 .2 .3-.7 .9h.7M252.5 31.4l.3-.3v1.2M252.5 32.3h.7M252.6 33.5l.2-.1a.61 .61 0 0 1 .4 .7 .61 .61 0 0 1-.6 .5l-.1-.4zM252.7 38.8l-.2-.4 .1-.1h.5l.1 .2-.7 .4v.3l.2 .3h.3l.2-.3v-.3l-.2-.1M253.2 36.3l-.2 .3-.4-.1-.1-.2v-.2l.2-.3h.3a.81 .81 0 0 1 0 1.2h-.4M254.8 32.1l.5-1.2 .4 1.2M254.8 39.3l.5-1.2 .4 1.2M254.8 36.9l.5-1.3 .4 1.3M254.8 34.5l.5-1.2 .4 1.2M255 38.9h.5"/>
<path d="M255 36.6h.5M255 34.1h.5M255 31.7h.5M256 31.2l.4-.3v1.2M256 38.4l.4-.3v1.2M256 36l.4-.4v1.3M256 33.6l.4-.3v1.2M256 39.3h.7M256 36.9h.7M256 34.5h.7M256 32.1h.7M256.2 21.3h.9"/>
<path d="M256.7 20.7v1M257.1 38.1h.7l-.3 .4 .3 .1v.5l-.2 .2h-.3l-.2-.2M257.1 33.3h.8l-.5 1.2M257.4 31.4l-.3-.2 .1-.2h.6v.3l-.4 .1-.3 .3 .2 .4 .5-.1v-.4l-.2-.2M257.5 35.6l-.4 .9h.8M257.7 36.1v.8M258.2 25.4h.1M258.2 26.6h3.6v1.9M258.2 23l-.6 1.2M258.2 23l.8 1.2M258.2 23v7.2h-7.1M258.3 20.5h-.6l-.1 .6 .2-.2h.3l.2 .2v.5h-.7"/>
<path d="M258.7 20.5l.4 1.2 .4-1.2M260.9 35.6a.42 .42 0 0 0-.6 .2v.6l.1 .3h.5v-.5h-.1M261.8 31.4v1.2h1.3l-1.3 1.2-1.2-1.2h1.2M261.8 31.4h.1M261.8 29.5v1.9M262.1 35.5v1.2l-.6-1.2v1.2M262.7 35.5l.5 .1 .2 .2v.6l-.3 .3h-.4zM264.6 29.9l.3-.4v1.2M264.6 30.7h.7M265.3 27.3a.45 .45 0 0 0-.7 .1v.7a.45 .45 0 0 0 .7 .2M265.7 27.2h.7l-.5 1.2M265.8 29.6l.3-.1a.91 .91 0 0 1 .1 1.2l-.4-.1z"/>
<path d="M267 29.6l.2-.1 .3 .3v.8l-.2 .1h-.3l-.2-.4zM268 30.1h.5v.6M268 30v.7M269.1 30.1h.4M269.7 29.5h-.6v1.2M277.2 39.8l.3-1.3 .5 1.3M277.3 39.5h.6M23.4 42.2h7.7M23.4 44.5h7.7M23.4 46.9h7.7M23.4 49.3h7.7M23.4 51.6h7.7"/>
<path d="M24.7 41.7l.4-1.2 .5 1.2M24.7 51.2l.4-1.2 .5 1.2M24.7 46.4l.4-1.2 .5 1.2M24.7 48.8l.4-1.2 .5 1.2M24.7 44l.4-1.2 .5 1.2M24.9 41.3h.5M24.9 43.7h.5M24.9 50.9h.5M24.9 46.1h.5M24.9 48.4h.5M25.8 40.5h.8l-.5 1.2M25.8 50h.8l-.4 .5h.3l.1 .5-.3 .2h-.3l-.2-.1"/>
<path d="M25.9 59.6l.4-.1 .3 .4-.8 .8h.8M26.2 47.6l-.3 .8h.7M26.4 42.8l-.5 .3v.8h.6l.1-.4-.3-.2h-.2l-.2 .2M26.4 48v.8M26.5 45.2h-.6v.6l.4-.2 .3 .3v.3l-.2 .2-.5-.1M27.1 41.1h.3M27.1 50.5h.3M27.1 45.8h.3M27.1 43.4h.3M27.1 48.2h.3M27.1 57.6h.4M27.6 40.5h-.5v1.2h.5"/>
<path d="M27.6 59.5h-.5v1.2h.5M27.6 50h-.5v1.2h.5M27.6 45.2h-.5v1.2h.5M27.6 47.6h-.5v1.2h.5M27.6 42.8h-.5v1.2h.5M27.7 57h-.6v1.2h.6M28 57l.9 1.2M28.9 47.8h.8l-.5 1.1M28.9 57l-.9 1.2M29.2 40.6l-.2 .8h.7M29.2 50.6h-.2a.31 .31 0 0 1 .1-.4 .31 .31 0 0 1 .4 .1v.3h-.3l-.2 .3v.4h.5l.1-.4-.2-.3M29.3 57.6h.4l.2-.2v-.3l-.2-.1h-.4v1.2l.6-.1 .1-.4-.3-.1"/>
<path d="M29.5 43h-.5v.6l.1-.2 .4 .1v.6h-.5M29.5 45.4l-.4 .1-.1 .8a.35 .35 0 0 0 .3 .3 .35 .35 0 0 0 .3-.3v-.2l-.2-.3-.4 .3M29.5 41v.8M30.5 57.1l.4-.1 .3 .3-.8 .9h.8M31.4 55.2h.5l.2-.2-.1-.3-.6-.1v1.2M31.7 57v1.2M31.7 57.6h.6M31.7 55.2l.4 .6M32.3 57v1.2M32.7 57l.4 1.2 .4-1.2M33.3 54.6v1.2l-.7-1.2v1.2M33.7 54.6h.8l-.5 .4 .5 .3-.1 .4h-.7"/>
<path d="M34.1 56.9l-.2 .8h.6M34.4 57.4v.8M34.6 42.2h7.8M34.6 44.5h7.8M34.6 46.9h7.8M34.6 49.3h7.8M34.6 51.6h7.8M34.9 57h.8l-.5 1.2M35.6 41l.3-.4v1.2M35.6 43.3l.3-.3v1.2M35.6 45.7l.3-.3v1.2M35.6 48.1l.3-.3v1.1"/>
<path d="M35.6 41.8h.6M35.6 44.2h.6M35.6 46.6h.6M35.6 48.9h.6M36.2 57.1l.3-.1a.64 .64 0 0 1 .4 .6 .64 .64 0 0 1-.5 .6l-.2-.3zM36.7 40.6h.6l-.3 .5h.3v.6l-.1 .1h-.4l-.1-.1M36.7 43.1h.6v.4l-.6 .7h.6M36.7 45.7l.3-.3v1.2M36.7 46.6h.6M36.8 47.8h.3l.2 .2v.8l-.1 .1h-.4l-.1-.4zM36.8 50.6l-.2 .3-.4-.1v-.5l.4-.2a.81 .81 0 0 1 0 1.2h-.4M37.3 59.7h-.3a.73 .73 0 0 0-.1 1.2l.4-.1v-.5l-.4-.2-.2 .3"/>
<path d="M37.7 57v.8l-.2 .3-.3 .1M38 57l.4 1.2 .5-1.2M39 44l.5-1.2 .4 1.2M39 41.7l.5-1.2 .4 1.2M39 48.8l.5-1.2 .4 1.2M39 46.4l.5-1.2 .4 1.2M39 51.2l.5-1.2 .4 1.2M39.2 41.3h.5M39.2 43.7h.5M39.2 50.9h.5M39.2 46.1h.5M39.2 48.4h.5"/>
<path d="M40.1 40.5h.8l-.5 1.2M40.1 50h.8l-.4 .5h.3l.1 .5-.3 .2h-.3l-.2-.1M40.2 59.6l.4-.1 .3 .4-.8 .8h.8M40.5 47.6l-.3 .8h.7M40.7 42.8l-.5 .3v.8h.6l.1-.4-.3-.2h-.2l-.2 .2M40.7 48v.8M40.8 45.2h-.6v.6l.4-.2 .3 .3v.3l-.2 .2-.5-.1M48.3 42.2h8.4M48.3 44.5h8.4M48.3 46.9h8.4M48.3 49.3h8.4M48.3 51.6h8.4"/>
<path d="M48.3 54h8.4M48.3 56.5h8.4M48.3 58.8h8.4M48.6 46.4l.4-1.2 .4 1.2M48.6 44l.4-1.2 .4 1.2M48.6 41.7l.4-1.2 .4 1.2M48.6 53.6l.4-1.2 .4 1.2M48.6 48.8l.4-1.2 .4 1.2M48.6 56l.4-1.2 .4 1.2M48.6 51.2l.4-1.2 .4 1.2M48.6 58.3l.4-1.2 .4 1.2M48.7 41.3h.6"/>
<path d="M48.7 43.7h.6M48.7 50.9h.6M48.7 46.1h.6M48.7 48.4h.6M48.7 53.3h.6M48.7 55.6h.6M48.7 58h.6M48.8 59.5a.66 .66 0 0 1 .6 .5 .66 .66 0 0 1-.2 .7h-.4zM49.7 40.5h.8l-.5 1.2M49.7 52.5h.7v.4l-.7 .7h.7M49.7 55.1l.3-.3v1.2M49.7 50h.7l-.4 .5h.4v.6l-.2 .1h-.3l-.2-.1"/>
<path d="M49.7 56h.7M49.9 57.2l.2-.1 .3 .3v.7l-.4 .2a.7 .7 0 0 1-.1-1.1zM50 59.6l.3-.1 .2 .3v.7l-.1 .2h-.4l-.1-.4zM50 47.6l-.3 .8h.8M50.3 42.8h-.3a.73 .73 0 0 0 0 1.2l.4-.1v-.5l-.4-.1-.3 .2M50.3 48v.8M50.4 45.2h-.6l-.1 .6 .2-.2h.3l.2 .2v.5h-.7M50.9 41.1h.4M50.9 50.5h.4M50.9 45.8h.4M50.9 43.4h.4M50.9 48.2h.4"/>
<path d="M50.9 52.9h.4M50.9 55.4h.4M50.9 57.7h.4M51.5 45.2h-.6v1.2h.6M51.5 42.8h-.6v1.2h.6M51.5 40.5h-.6v1.2h.6M51.5 52.4h-.6v1.2h.6M51.5 47.6h-.6v1.2h.6M51.5 54.8h-.6v1.2h.6M51.5 50h-.6v1.2h.6M51.5 57.1h-.6v1.2h.6M51.6 59.5h-.5v1.2h.5"/>
<path d="M54 52.9l.4-.3v1.2M54 55.3l.4-.4v1.2M54 57.7l.4-.4v1.2M54 53.8h.7M54 56.1h.7M54 58.5h.7M54.5 45.4h.9l-.5 1.2M54.9 48.3h-.2a.31 .31 0 0 1 .1-.5 .31 .31 0 0 1 .4 .1v.4h-.3l-.3 .2 .1 .4h.5l.1-.1-.1-.5h-.2M55.1 59.7h.8l-.4 .4 .4 .3-.1 .4h-.7M55.2 40.6h-.5l-.1 .5h.6v.6l-.4 .1-.2-.1M55.2 43l-.4 .1-.2 .8a.35 .35 0 0 0 .3 .3 .35 .35 0 0 0 .4-.3l-.1-.4-.2-.1-.4 .3M55.2 52.7l.2-.1a.6 .6 0 0 1 .6 .4 .6 .6 0 0 1-.3 .7l-.2 .1-.3-.3z"/>
<path d="M55.2 55.3l.3-.4v1.2M55.2 57.4l.4-.1 .3 .4-.8 .8h.8M55.2 56.1h.7M55.3 50.6a.35 .35 0 0 1-.4 .3 .35 .35 0 0 1-.3-.3l.1-.4h.5v.9l-.2 .2h-.3M56.7 42h1.2v.2h-1.2zM56.7 44.4h1.2v.2h-1.2zM56.7 46.7h1.2v.3h-1.2zM56.7 49.2h1.2v.2h-1.2zM56.7 51.6h1.2v.2h-1.2zM56.7 53.9h1.2v.3h-1.2zM56.7 56.3h1.2v.3h-1.2zM56.7 58.7h1.2v.2h-1.2z"/>
<path d="M60.3 42h1.2v.2h-1.2zM60.3 44.4h1.2v.2h-1.2zM60.3 46.7h1.2v.3h-1.2zM60.3 49.2h1.2v.2h-1.2zM60.3 51.6h1.2v.2h-1.2zM60.3 53.9h1.2v.3h-1.2zM60.3 56.3h1.2v.3h-1.2zM60.3 58.7h1.2v.2h-1.2zM61.5 51.6h12.2l.3-.9 .8 2 .6-2 .8 2 .7-2 .7 2 .4-1.1h7.3M61.5 42.2h8.4M61.5 44.5h8.4M61.5 46.9h8.4"/>
<path d="M61.5 49.3h8.4M61.5 54h8.4M61.5 56.5h15.5M61.5 58.8h8.4M62.4 40.7l.5-.1 .2 .4-.8 .8h.8M62.4 43.1l.4-.1 .3 .3-.8 .9h.8M62.4 45.5l.4-.1 .3 .3-.8 .9h.8M62.4 47.9l.4-.1 .3 .3-.8 .8h.8M62.4 50.3l.4-.2 .3 .4-.8 .8h.8M62.4 52.7l.5-.1 .2 .3-.8 .9h.8M62.4 55l.5-.1 .2 .4-.8 .8h.8M62.4 57.4l.4-.1 .3 .4-.8 .8h.8"/>
<path d="M62.4 59.8l.4-.1 .3 .3-.8 .9h.8M63.5 43h.8l-.5 1.2M63.5 52.6h.7l-.4 .4 .4 .1v.5l-.2 .2h-.3l-.2-.2M63.5 55h.7v.5l-.7 .6h.7M63.5 57.7l.3-.4v1.2M63.5 58.5h.7M63.7 59.8l.2-.1 .3 .2v.7l-.4 .3a.7 .7 0 0 1-.1-1.1zM63.8 41.1l-.3-.3 .2-.2h.4l.1 .4-.7 .3v.3l.3 .2 .4-.1v-.5l-.2-.1M63.8 50.1l-.3 .9h.8M64.1 45.4h-.3a.73 .73 0 0 0 0 1.2l.4-.1v-.5l-.4-.2-.3 .3M64.1 50.5v.8M64.2 47.8h-.6l-.1 .5h.6l.1 .6h-.7"/>
<path d="M66.5 46.4l.4-1.2 .4 1.2M66.5 48.8l.4-1.2 .4 1.2M66.5 53.6l.4-1.2 .4 1.2M66.5 44l.4-1.2 .4 1.2M66.5 41.7l.4-1.2 .4 1.2M66.5 49.7h5.3M66.5 41.3h.6M66.5 43.7h.6M66.5 46.1h.6M66.5 48.4h.6M66.5 53.3h.6M66.6 57.1h.4l.3 .3v.7l-.3 .2h-.4z"/>
<path d="M66.6 59.5h.4l.3 .3v.7l-.2 .2h-.5zM67.3 50.1l-.2-.1a.6 .6 0 0 0-.5 .6 .6 .6 0 0 0 .7 .5M67.6 47.9l.4-.3v1.2M67.6 52.7l.4-.3v1.2M67.6 40.8l.4-.3v1.2M67.6 48.8h.7M67.6 53.6h.7M67.6 41.7h.7M67.7 57.1h.8l-.5 1.2M67.8 50v1.2h.6M67.8 43.3h-.2v-.4h.6v.4l-.6 .1v.5l.2 .1h.3l.2-.2-.2-.5M68.3 45.7l-.2 .3-.5-.1v-.6l.5-.1 .2 .3-.1 .8-.5 .1"/>
<path d="M68.3 59.5l-.5 .3v.8l.5 .1 .2-.2v-.3l-.2-.2h-.4l-.1 .2M68.7 40.5h.7l-.4 .4 .3 .1v.6h-.6M68.7 47.9l.4-.3v1.2M68.7 48.8h.7M68.8 50a.64 .64 0 0 1 .7 .6 .64 .64 0 0 1-.7 .6zM68.8 52.5l.1-.1a.59 .59 0 0 1 .6 .4 .59 .59 0 0 1-.2 .6l-.1 .2-.4-.2zM68.8 45.8h.4M68.8 43.4h.4M69 57.7h.3M69.3 45.2h-.5v1.2h.5M69.3 42.8h-.5v1.2h.5M69.5 57.1h-.5v1.2h.5"/>
<path d="M69.5 59.5h-.5v1.2h.5M69.9 41.1h.5M69.9 48.2h.5M69.9 52.9h.5M70.5 47.6h-.6v1.2h.6M70.5 52.4h-.6v1.2h.6M70.5 40.5h-.6v1.2h.6M70.6 50h-.6v.5l.5 .2 .1 .3-.2 .2-.5-.1M71.1 50.5h.4M71.7 50h-.6v1.2h.6M74.5 49.6l-.2-.1v-.3h.6v.3l-.6 .2v.5l.2 .1h.3l.2-.3-.2-.4M74.7 47.6l.7-.1v-.4l-.7-.1v1.2"/>
<path d="M75 47.6l.4 .6M75.4 49.2l.5-.1 .2 .3-.7 .9h.7M75.9 47.3l.3-.3v1.2M75.9 48.2h.6M76.1 43.9a.45 .45 0 0 0-.7 .2v.7a.45 .45 0 0 0 .7 .2v-.5h-.2M76.6 49.7h.6v-.5l-.6-.1v1.2M76.9 49.7l.4 .6M77 56.5v1.2h1.2l-1.2 1.1-1.2-1.1h1.2M77 56.5h.1M77.3 43.9v1.1l-.7-1.1v1.1M77.9 43.9h.3l.4 .2v.7l-.4 .2h-.3zM80.8 49.7h4.2"/>
<path d="M81.6 50.1l-.3-.1-.4 .3 .1 .8 .3 .1 .3-.1M82.1 50v1.2h.6M82.8 44.2h.7v.4l-.8 .7h.8M83.1 50a.64 .64 0 0 1 .7 .6 .64 .64 0 0 1-.7 .6zM84 44.2l.4-.1 .3 .3-.8 .9h.8M84.1 42.1h.6v-.5l-.6-.1v1.2M84.3 42.1l.5 .6M84.9 50h-.6v.5l.5 .2 .1 .3-.2 .2-.5-.1M85.2 44.2l.3-.1a.78 .78 0 0 1 0 1.2l-.3-.1zM85.2 41.5h.7l-.5 1.2M86.2 45.3h.3v-.3h-.1l-.2-.3a.48 .48 0 0 1 .5-.6 .48 .48 0 0 1 .4 .6l-.2 .3v.3h.2M90.5 51.9h.9"/>
<path d="M90.5 58.2v1.2M90.5 58.8h.7M90.9 51.5v.9M91.2 58.2v1.2M91.7 58.3l.4-.1 .3 .3-.8 .9h.8M91.9 51.7h.6l.1-.3-.1-.2h-.6v1.2h.6l.1-.2v-.3l-.2-.2M93 52.4l.4-1.2 .4 1.2M93.1 52.1h.5M94 48l-.3-.1a.61 .61 0 0 0-.4 .6 .61 .61 0 0 0 .5 .6l.3-.1v-.4h-.3M94 51.2h.7M94.3 51.2v1.2M94.9 44.5v1.2h1.2l-1.2 1.2-1.2-1.2h1.2"/>
<path d="M94.9 44.5h.1M94.9 51.2h.7M94.9 41.4v3.1M95.3 47.9v1.2l-.7-1.2v1.2M95.3 51.2v1.2M95.8 47.9h.3l.3 .3v.7l-.3 .2h-.3zM95.9 43.3l.4-.4v1.2M95.9 44.1h.7M97.3 42.9l.3 .1a.66 .66 0 0 1-.2 1.1l-.1-.1a.67 .67 0 0 1 0-1.1zM98.3 43l.4-.1a.86 .86 0 0 1-.1 1.2l-.3-.1zM99.4 43.4l.4-.1 .1 .8M99.4 43.3v.8"/>
<path d="M99.9 41.4h4.3v.5h-4.3zM100.5 43.5h.3M101 42.9h-.5v1.2M101.1 48a.54 .54 0 0 0-.7 .6 .54 .54 0 0 0 .8 .4v-.4h-.3M102 44.5v1.2h1.2l-1.2 1.2-1.2-1.2h1.2M102 44.5h.1M102 41.9v2.6M102.4 47.9v1.2l-.7-1.2v1.2M103 47.9l.5 .2 .1 .3-.1 .5-.3 .2h-.2zM103.8 43.3l.3-.4v1.2M103.8 44.1h.7M105.1 42.9h.3l.2 .2v.8l-.4 .2a.84 .84 0 0 1-.1-1.2z"/>
<path d="M106.2 43.3v1.2M106.7 43.3v.7l-.4 .1-.1-.2M106.7 43.9l.1 .2M107.4 43.5h.4M108 42.9h-.6v1.2M111.6 42.2h7.1M111.6 44.5h7.1M111.6 46.9h7.1M111.6 49.3h7.1M111.6 51.6h7.1M111.6 54h7.1M111.6 56.5h7.1"/>
<path d="M111.6 58.8h7.1M111.8 56l.4-1.2 .4 1.2M111.8 44l.4-1.2 .4 1.2M111.8 41.7l.4-1.2 .4 1.2M111.8 48.8l.4-1.2 .4 1.2M111.8 51.2l.4-1.2 .4 1.2M111.8 53.6l.4-1.2 .4 1.2M111.8 46.4l.4-1.2 .4 1.2M111.9 59.5h.4l.3 .3v.7l-.2 .2h-.5zM111.9 57.1h.4l.3 .3v.7l-.3 .2h-.4zM111.9 41.3h.5M111.9 43.7h.5"/>
<path d="M111.9 50.9h.5M111.9 46.1h.5M111.9 48.4h.5M111.9 53.3h.5M111.9 55.6h.5M112.9 47.6h.7l-.4 .5 .4 .2v.3l-.1 .2-.6-.1M112.9 54.9l.2-.1 .4 .1a.66 .66 0 0 1-.3 1.1l-.3-.3zM112.9 50.1l.5-.1 .2 .3-.7 .9h.7M112.9 52.7l.4-.3v1.2M112.9 53.6h.7M113.2 45.1l-.3 1h.7M113.3 57.7l-.2-.1v-.4h.6v.4l-.6 .1v.6h.2h.2l.3-.2-.3-.4"/>
<path d="M113.5 40.5h-.4l-.2 .2v.9h.6l.1-.5-.2-.2h-.3l-.2 .2M113.5 45.6v.8M113.5 42.8h-.6v.6l.5-.1 .2 .2-.1 .4h-.6M116.7 50.5l.3-.4v1.2M116.7 52.9l.3-.3v1.2M116.7 55.3l.3-.4v1.2M116.7 57.7l.3-.4v1.2M116.7 53.8h.6M116.7 56.1h.6M116.7 58.5h.6M116.7 51.3h.6M117.2 43h.7l-.5 1.2"/>
<path d="M117.4 45.9l-.2-.3 .2-.2 .5 .1v.3a.51 .51 0 0 0-.6 .7h.6v-.5l-.2-.1M117.7 57.3h.7l-.4 .4 .4 .3v.4h-.7M117.8 40.6l-.5 .1a.82 .82 0 0 0 .1 1.1l.5-.1v-.6h-.5l-.2 .2M117.8 52.9l.3-.3v1.2M117.8 55l.6-.1v.4l-.7 .8h.7M117.8 53.8h.6M117.9 48.3v.1l-.5 .1-.2-.2v-.3l.2-.2 .5 .1v.8l-.2 .2h-.4M117.9 50.3l.1-.2a.75 .75 0 0 1 .3 1.2l-.4-.1zM118 59.6l-.2 .9h.7M119.5 40.3l.5-1.2 .4 1.2M119.5 42.7l.5-1.2 .4 1.2M119.5 45l.5-1.1 .4 1.1"/>
<path d="M119.5 47.4l.5-1.2 .4 1.2M119.5 49.8l.5-1.2 .4 1.2M119.5 52.2l.5-1.1 .4 1.1M119.5 54.6l.5-1.2 .4 1.2M119.5 57l.5-1.2 .4 1.2M119.7 58.2h.4l.3 .2v.7l-.3 .3h-.4zM119.7 42.3h.5M119.7 44.7h.5M119.7 47.1h.5M119.7 49.4h.5M119.7 51.9h.5M119.7 54.3h.5"/>
<path d="M119.7 56.6h.5M120.7 48.6h.7l-.4 .5 .4 .2v.3l-.2 .2-.5-.1M120.7 51.1h.5l.2 .3-.7 .8h.7M120.7 53.8l.4-.4v1.2M120.7 54.6h.7M120.8 55.9l.3-.1a.64 .64 0 0 1 .3 .6 .64 .64 0 0 1-.4 .6l-.3-.3zM121 46.2l-.3 .9h.7M121 58.3l.2-.1a.64 .64 0 0 1 .4 .6 .64 .64 0 0 1-.4 .6l-.3-.3zM121.2 41.5l-.5 .2v.9h.6l.1-.4-.2-.3h-.3l-.2 .3M121.2 46.7v.7M121.3 43.9h-.6v.5l.5-.1 .2 .2-.1 .5h-.6M129.1 40.3l.4-1.2 .5 1.2"/>
<path d="M129.1 47.4l.4-1.2 .5 1.2M129.1 52.2l.4-1.1 .5 1.1M129.3 47.1h.5M129.3 51.9h.5M129.9 48.6l-1 1.5M130 53.3l-1.1 1.6M130.3 42.7l.4-1.2 .4 1.2M130.3 45l.4-1.1 .4 1.1M130.3 46.6l.3-.4v1.2M130.3 48.8l.3-.2 .3 .1a.87 .87 0 0 1 0 1.1h-.5l-.2-.4zM130.3 51.4l.3-.3v1.1M130.3 55.8l.6 .2 .1 .3-.1 .5-.3 .2h-.3z"/>
<path d="M130.3 58.2l.6 .1 .1 .4-.1 .5-.3 .2h-.3zM130.3 40.3h.7M130.3 47.4h.7M130.3 52.2h.7M130.4 42.3h.6M130.4 44.7h.6M131.1 53.5l-.5-.1-.3 .3 .1 .7 .3 .2 .4-.2M131.4 46.6h.2l.1-.4v1.2M131.4 55.8h.8l-.5 1.2M131.4 47.4h.7M131.6 51.1h.3l.2 .1v.8l-.3 .2a.71 .71 0 0 1-.2-1.1zM131.6 49.2h.3"/>
<path d="M131.6 53.9h.3M131.7 42l-.3-.3 .3-.2 .4 .1v.3a.51 .51 0 0 0-.6 .7h.6v-.5l-.2-.1M132 58.2h-.3a.73 .73 0 0 0 0 1.2l.4-.1v-.5l-.4-.2-.3 .2M132.1 44.4l-.2 .2h-.2l-.3-.2 .1-.5h.6v.9l-.5 .2M132.1 48.6h-.5v1.2h.5M132.1 53.4h-.5v1.2h.5M133 42.2h7.2M133 44.5h7.2M133 46.9h7.2M133 49.3h15.5v26.2h118.1v-26.2h-15.5M133 51.6h7.2M133 54h11.9v25.1h78.8v-25.1h-11.9"/>
<path d="M133 56.5h7.2M133 58.8h7.2M133.4 40.7l.5-.1 .1 .4-.7 .8h.7M133.4 43.1l.4-.1 .2 .3-.7 .9h.7M133.4 45.5l.4-.1 .2 .3-.7 .9h.7M133.4 47.9l.4-.1 .2 .3-.7 .8h.7M133.4 50.3l.4-.2 .2 .4-.7 .8h.7M133.4 52.7l.5-.1 .1 .3-.7 .9h.7M133.4 55l.5-.1 .1 .4-.7 .8h.7M133.4 57.4l.4-.1 .2 .4-.7 .8h.7M134.4 40.6h.8l-.5 1.2M134.4 50.1h.7l-.3 .5 .3 .1v.5h-.7"/>
<path d="M134.5 52.7l.5-.1 .1 .5-.7 .7h.7M134.5 55.3l.3-.4v1.2M134.5 56.1h.6M134.6 57.4l.3-.1 .2 .3v.7l-.3 .2a.7 .7 0 0 1-.2-1.1zM134.8 47.8l-.3 .8h.7M135 43h-.2a.73 .73 0 0 0-.1 1.2l.4-.1v-.5l-.4-.2-.2 .3M135 48.2v.7M135.1 45.4h-.6v.6l.1-.2h.4l.1 .2v.5h-.6M136.8 41.7l.4-1.2 .4 1.2M136.8 44l.4-1.2 .4 1.2M136.8 46.4l.4-1.2 .4 1.2M136.8 51.2l.4-1.2 .4 1.2"/>
<path d="M136.9 41.3h.6M136.9 43.7h.6M136.9 50.9h.6M136.9 46.1h.6M137 59.5a.66 .66 0 0 1 .6 .5 .66 .66 0 0 1-.2 .7h-.4zM137 54.8h.4a.66 .66 0 0 1 .2 .7 .66 .66 0 0 1-.6 .5zM137 57.1l.6 .2 .1 .4-.1 .5-.4 .1h-.2zM138 45.6l.3-.4v1.2M138 50.3l.3-.3v1.2M138 46.4h.7M138 51.2h.7M138.2 59.9l.3-.4v1.2"/>
<path d="M138.2 55.1l.3-.3v1.2M138.2 41l-.2-.4 .5-.1 .2 .2-.3 .3-.4 .1v.5l.2 .1h.2l.3-.3-.3-.4M138.2 57.5l.3-.4v1.2M138.2 56h.7M138.2 58.3h.7M138.7 43.3l-.3 .3-.4-.2v-.5l.4-.1a.73 .73 0 0 1-.1 1.2h-.2M139.1 45.6l.3-.4v1.2M139.1 46.4h.7M139.2 59.5h.8l-.5 .5h.4v.7l-.7-.1M139.4 50a.68 .68 0 0 1 .4 .6 .68 .68 0 0 1-.4 .6l-.3-.5 .1-.6zM139.5 57.1l-.2 .8h.7M139.9 54.8h-.5l-.1 .6 .1-.2 .5 .1v.6h-.6"/>
<path d="M139.9 57.6v.7M151 42.2h7.1M151 44.5h7.1M151 46.9h7.1M151 49.3h7.1M151 51.6h7.1M151 54h7.1M151 56.5h7.1M151 58.8h7.1M151.1 53.6l.5-1.2 .3 1.2M151.1 48.8l.5-1.2 .3 1.2M151.1 41.7l.5-1.2 .3 1.2"/>
<path d="M151.1 51.2l.5-1.2 .3 1.2M151.1 56l.5-1.2 .3 1.2M151.1 46.4l.5-1.2 .3 1.2M151.1 44l.5-1.2 .3 1.2M151.2 41.3h.6M151.2 43.7h.6M151.2 50.9h.6M151.2 46.1h.6M151.2 48.4h.6M151.2 53.3h.6M151.2 55.6h.6M151.3 57.1l.6 .2 .1 .4-.1 .5-.3 .1h-.3z"/>
<path d="M151.3 59.5a.66 .66 0 0 1 .7 .5 .66 .66 0 0 1-.3 .7h-.4zM152.2 47.6h.8l-.4 .5 .4 .2v.3l-.2 .2-.6-.1M152.3 52.7l.4-.3v1.2M152.3 50.1l.4-.1 .3 .3-.8 .9h.8M152.3 54.9l.2-.1 .3 .1a.66 .66 0 0 1-.2 1.1l-.3-.3zM152.3 53.6h.7M152.6 45.1l-.3 1h.7M152.7 57.7l-.2-.1v-.4h.6v.4l-.6 .1v.6h.2h.2l.3-.2-.3-.4M152.8 40.5h-.3l-.2 .2v.9h.6l.1-.5-.3-.2h-.2l-.2 .2M152.8 45.6v.8M152.9 42.8h-.6v.6l.4-.1 .3 .2-.1 .4h-.6M156 50.5h.1l.2-.4v1.2"/>
<path d="M156 52.9l.3-.3v1.2M156 55.3l.3-.4v1.2M156 57.7l.3-.4v1.2M156 53.8h.6M156 56.1h.6M156 58.5h.6M156 51.3h.6M156.5 43h.8l-.5 1.2M156.8 45.9l-.3-.3a.35 .35 0 0 1 .4-.2 .35 .35 0 0 1 .3 .2l-.2 .3a.36 .36 0 0 0-.5 .4 .36 .36 0 0 0 .6 .3 .36 .36 0 0 0 0-.6l-.1-.1M157.1 57.3h.7l-.4 .4 .4 .3-.1 .4h-.6M157.1 40.6h-.3l-.2 .3v.8h.5l.1-.4a.35 .35 0 0 0-.3-.2 .35 .35 0 0 0-.4 .2M157.1 52.9l.4-.3v1.2"/>
<path d="M157.1 55l.5-.1 .2 .4-.7 .8h.7M157.1 53.8h.7M157.2 48.3a.35 .35 0 0 1-.3 .2 .35 .35 0 0 1-.4-.2l.1-.5h.5v.9l-.1 .2h-.4M157.4 50.1a.71 .71 0 0 1 .2 1.2h-.3l-.2-.2v-.7zM157.4 59.6l-.3 .9h.7M158.9 40.3l.4-1.2 .4 1.2M158.9 42.7l.4-1.2 .4 1.2M158.9 45l.4-1.1 .4 1.1M158.9 47.4l.4-1.2 .4 1.2M158.9 49.8l.4-1.2 .4 1.2M158.9 52.2l.4-1.1 .4 1.1M158.9 54.6l.4-1.2 .4 1.2"/>
<path d="M158.9 57l.4-1.2 .4 1.2M159 42.3h.6M159 44.7h.6M159 47.1h.6M159 49.4h.6M159 51.9h.6M159 54.3h.6M159 56.6h.6M159.1 58.2l.6 .1 .1 .4-.1 .5-.4 .2h-.2zM160 48.6h.7l-.3 .5 .3 .1v.5h-.7M160 51.1h.7v.5l-.7 .6h.7M160 53.8l.4-.4v1.2"/>
<path d="M160 54.6h.7M160.2 55.9l.2-.1 .3 .2v.7l-.3 .3a.7 .7 0 0 1-.2-1.1zM160.4 46.2l-.4 .9h.8M160.4 58.3l.2-.1 .3 .2v.7l-.4 .3a.7 .7 0 0 1-.1-1.1zM160.6 41.5h-.2a.73 .73 0 0 0-.1 1.2l.4-.1v-.5l-.4-.2-.3 .3M160.6 46.7v.7M160.7 43.9h-.6l-.1 .5 .2-.1h.3l.2 .1v.6h-.7M168.5 40.3l.4-1.2 .4 1.2M168.5 47.4l.4-1.2 .4 1.2M168.5 52.2l.4-1.1 .4 1.1M168.7 47.1h.5M168.7 51.9h.5"/>
<path d="M169.2 48.6l-1 1.5M169.3 53.3l-1.1 1.6M169.7 42.7l.3-1.2 .4 1.2M169.7 45l.3-1.1 .4 1.1M169.7 46.6l.3-.4v1.2M169.7 51.4l.3-.3v1.1M169.7 55.8a.6 .6 0 0 1 .7 .6 .6 .6 0 0 1-.7 .6zM169.7 58.2a.6 .6 0 0 1 .7 .6 .6 .6 0 0 1-.7 .6zM169.7 40.3h.6M169.7 47.4h.6M169.7 52.2h.6M169.8 42.3h.5"/>
<path d="M169.8 44.7h.5M169.8 48.6l.5 .2v.8l-.1 .2h-.4a.86 .86 0 0 1 0-1.2zM170.3 53.5l-.5-.1-.1 .3 .1 .7 .2 .2 .3-.2M170.7 55.8h.8l-.5 1.2M170.8 46.6l.3-.4v1.2M170.8 47.4h.7M170.9 51.1a.59 .59 0 0 1 .6 .3 .59 .59 0 0 1-.1 .7l-.2 .1-.3-.1zM170.9 49.2h.4M170.9 53.9h.4M171 42l-.2-.3a.35 .35 0 0 1 .3-.2 .35 .35 0 0 1 .4 .2l-.3 .3a.36 .36 0 0 0-.4 .4 .36 .36 0 0 0 .5 .3 .36 .36 0 0 0 .1-.6l-.2-.1M171.4 58.2l-.5 .1-.1 .8a.35 .35 0 0 0 .3 .3 .35 .35 0 0 0 .4-.3v-.3l-.3-.2-.4 .2M171.5 44.4l-.5 .2-.2-.2v-.3a.35 .35 0 0 1 .3-.3 .35 .35 0 0 1 .4 .3l-.2 .9h-.4"/>
<path d="M171.5 48.6h-.6v1.2h.6M171.5 53.4h-.6v1.2h.6M172.4 54h11.9v28.6h78.8v-28.6h-12M172.4 42.2h7.2M172.4 44.5h7.2M172.4 46.9h7.2M172.4 49.3h15.5v26.2M172.4 51.6h7.2M172.4 56.5h7.2M172.4 58.8h7.2M172.7 40.7l.5-.1 .2 .4-.8 .8h.8M172.7 43.1l.4-.1 .3 .3-.8 .9h.8"/>
<path d="M172.7 45.5l.4-.1 .3 .3-.8 .9h.8M172.7 47.9l.4-.1 .3 .3-.8 .8h.8M172.7 50.3l.4-.2 .3 .4-.8 .8h.8M172.7 52.7l.5-.1 .2 .3-.8 .9h.8M172.7 55l.5-.1 .2 .4-.8 .8h.8M172.7 57.4l.4-.1 .3 .4-.8 .8h.8M173.7 40.6h.9l-.5 1.2M173.7 50.1h.8l-.4 .5h.3l.1 .2-.1 .5-.7-.1M173.8 52.7l.6-.1 .1 .3-.8 .9h.8M173.8 55.3l.4-.4v1.2M173.8 56.1h.7M173.9 57.4l.3-.1a.78 .78 0 0 1 0 1.2l-.3-.1z"/>
<path d="M174.1 47.8l-.3 .8h.8M174.4 43l-.4 .1-.2 .8a.35 .35 0 0 0 .4 .3 .35 .35 0 0 0 .3-.3v-.2l-.3-.3-.4 .3M174.4 45.4h-.5l-.1 .6 .2-.2 .4 .1v.6h-.6M174.4 48.2v.7M176.2 51.2l.4-1.2 .4 1.2M176.2 46.4l.4-1.2 .4 1.2M176.2 41.7l.4-1.2 .4 1.2M176.2 44l.4-1.2 .4 1.2M176.3 41.3h.6M176.3 43.7h.6M176.3 50.9h.6M176.3 46.1h.6"/>
<path d="M176.4 59.5a.66 .66 0 0 1 .6 .5 .66 .66 0 0 1-.2 .7h-.4zM176.4 57.1l.6 .2v.4v.5l-.4 .1h-.2zM176.4 54.8h.4a.66 .66 0 0 1 .2 .7 .66 .66 0 0 1-.6 .5zM177.3 50.3h.2l.1-.3v1.2M177.3 45.6l.3-.4v1.2M177.3 46.4h.7M177.3 51.2h.7M177.5 59.9l.3-.4v1.2M177.5 57.5l.3-.4v1.2M177.5 55.1l.3-.3v1.2M177.5 56h.6M177.5 58.3h.6"/>
<path d="M177.5 41l-.2-.4 .2-.1h.4l.1 .3-.7 .4 .2 .5 .5-.1v-.5l-.2-.1M178 43.3l-.2 .3h-.3l-.2-.3 .1-.4h.6v.9l-.5 .2M178.5 45.6l.3-.4v1.2M178.5 46.4h.7M178.6 59.5h.7l-.4 .5 .4 .2v.3l-.1 .2-.6-.1M178.7 50a.68 .68 0 0 1 .5 .6 .68 .68 0 0 1-.5 .6l-.2-.2v-.8zM178.9 57.1l-.3 .8h.7M179.2 57.6v.7M179.2 54.8h-.6v.6l.5-.2 .2 .3-.1 .4h-.6M190.2 42.2h7.2M190.2 44.5h7.2M190.2 46.9h7.2"/>
<path d="M190.2 49.3h7.2M190.2 51.6h7.2M190.2 54h7.2M190.2 56.5h7.2M190.2 58.8h7.2M190.5 48.8l.4-1.2 .4 1.2M190.5 53.6l.4-1.2 .4 1.2M190.5 51.2l.4-1.2 .4 1.2M190.5 46.4l.4-1.2 .4 1.2M190.5 56l.4-1.2 .4 1.2M190.5 41.7l.4-1.2 .4 1.2M190.5 44l.4-1.2 .4 1.2"/>
<path d="M190.6 41.3h.6M190.6 43.7h.6M190.6 50.9h.6M190.6 46.1h.6M190.6 48.4h.6M190.6 53.3h.6M190.6 55.6h.6M190.7 59.5a.66 .66 0 0 1 .6 .5 .66 .66 0 0 1-.2 .7h-.4zM190.7 57.1l.6 .2v.4v.5l-.4 .1h-.2zM191.6 47.6h.7l-.4 .5 .4 .1v.5h-.7M191.6 52.7l.3-.3v1.2M191.6 50.1l.2-.1h.3l.2 .1v.4l-.7 .7h.7"/>
<path d="M191.6 53.6h.7M191.8 59.9l.3-.4v1.2M191.8 54.8h.3l.2 .1v.8l-.4 .3a.84 .84 0 0 1-.1-1.2zM191.9 45.1l-.3 1h.8M191.9 57.2l.3-.1 .2 .3v.7l-.3 .2a.7 .7 0 0 1-.2-1.1zM192.2 40.5l-.4 .1-.2 .8 .3 .3 .4-.1v-.5l-.2-.2h-.2l-.3 .2M192.2 45.6v.8M192.3 42.8h-.6l-.1 .6 .2-.1h.3l.2 .1v.5h-.7M195.3 50.5l.4-.4v1.2M195.3 52.9l.4-.3v1.2M195.3 55.3l.4-.4v1.2M195.3 57.7l.4-.4v1.2"/>
<path d="M195.3 53.8h.7M195.3 56.1h.7M195.3 58.5h.7M195.3 51.3h.7M195.8 43h.9l-.6 1.2M196.1 45.9l-.2-.1v-.3h.6v.3l-.6 .2v.5l.4 .1a.35 .35 0 0 0 .3-.4 .35 .35 0 0 0-.3-.3M196.4 57.3h.8l-.4 .4 .4 .3-.1 .4h-.7M196.5 40.6h-.4l-.2 .3v.8l.2 .1 .4-.1v-.6h-.4l-.2 .2M196.5 52.9l.4-.3v1.2M196.5 55l.5-.1 .2 .4-.8 .8h.8M196.5 53.8h.7M196.6 48.3l-.3 .2-.4-.1v-.5l.4-.1 .3 .2-.2 .9h-.4"/>
<path d="M196.8 50.1a.71 .71 0 0 1 .2 1.2h-.3l-.2-.2v-.7zM196.8 59.6l-.3 .9h.7M198.3 40.3l.3-1.2 .5 1.2M198.3 42.7l.3-1.2 .5 1.2M198.3 45l.3-1.1 .5 1.1M198.3 47.4l.3-1.2 .5 1.2M198.3 49.8l.3-1.2 .5 1.2M198.3 52.2l.3-1.1 .5 1.1M198.3 54.6l.3-1.2 .5 1.2M198.3 57l.3-1.2 .5 1.2M198.4 42.3h.6M198.4 44.7h.6"/>
<path d="M198.4 47.1h.6M198.4 49.4h.6M198.4 51.9h.6M198.4 54.3h.6M198.4 56.6h.6M198.5 58.2a.6 .6 0 0 1 .6 .6 .6 .6 0 0 1-.6 .6zM199.3 48.6h.8l-.5 .5h.4l.1 .2-.1 .5-.7-.1M199.4 51.1h.6l.1 .3-.8 .8h.8M199.4 53.8l.3-.4v1.2M199.4 54.6h.7M199.5 55.9l.3-.1a.78 .78 0 0 1 0 1.2l-.3-.1zM199.6 46.2l-.2 .9h.8"/>
<path d="M199.6 58.3h.6v.8a.35 .35 0 0 1-.4 .3 .35 .35 0 0 1-.2-.5zM200 41.5l-.4 .1-.2 .8a.35 .35 0 0 0 .3 .3 .35 .35 0 0 0 .4-.3v-.2l-.3-.3-.4 .3M200 43.9h-.5l-.1 .5 .2-.1 .4 .1v.6h-.6M200 46.7v.7M207.9 40.3l.4-1.2 .3 1.2M207.9 47.4l.4-1.2 .3 1.2M207.9 52.2l.4-1.1 .3 1.1M207.9 47.1h.6M207.9 51.9h.6M208.6 48.6l-1 1.5M208.6 53.3l-1 1.6M209 42.7l.4-1.2 .4 1.2"/>
<path d="M209 45l.4-1.1 .4 1.1M209 46.6h.1l.2-.4v1.2M209 48.8l.5-.2a.86 .86 0 0 1 .1 1.2h-.5l-.1-.2zM209 51.4l.3-.3v1.1M209 55.8h.3l.3 .2v.7l-.3 .3h-.3zM209 58.2h.3l.3 .2v.7l-.3 .3h-.3zM209 40.3h.6M209 47.4h.6M209 52.2h.6M209.1 42.3h.5M209.1 44.7h.5M209.7 53.5l-.5-.1a.67 .67 0 0 0-.2 .7 .67 .67 0 0 0 .5 .5l.2-.2"/>
<path d="M210.1 55.8h.7l-.5 1.2M210.1 46.6l.4-.4v1.2M210.1 51.2l.2-.1a.6 .6 0 0 1 .6 .4 .6 .6 0 0 1-.2 .7h-.3l-.3-.2zM210.1 47.4h.7M210.2 49.2h.5M210.2 53.9h.5M210.3 42l-.2-.1v-.3h.6v.3l-.6 .2v.5l.2 .1h.3l.2-.3-.2-.4M210.7 58.2l-.6 .2v.9h.6l.1-.5-.2-.2h-.3l-.2 .2M210.8 44.4l-.2 .2-.5-.2v-.5h.5a.73 .73 0 0 1-.1 1.1h-.3M210.8 48.6h-.6v1.2h.6M210.8 53.4h-.6v1.2h.6M211.8 42.2h7.1"/>
<path d="M211.8 44.5h7.1M211.8 46.9h7.1M211.8 49.3h15.4v26.2M211.8 51.6h7.1M211.8 56.5h7.1M211.8 58.8h7.1M212 40.7h.7v.4l-.7 .7h.7M212 43.1h.7v.4l-.7 .7h.7M212 45.5h.7v.4l-.7 .7h.7M212 47.9l.2-.1h.3l.2 .1v.4l-.7 .6h.7M212 50.3l.2-.2h.3l.2 .2v.3l-.7 .7h.7M212 52.7h.7v.4l-.7 .7h.7"/>
<path d="M212 55h.7v.5l-.7 .6h.7M212 57.4h.7v.4l-.7 .7h.7M213.1 40.6h.8l-.5 1.2M213.1 50.1h.8l-.5 .5 .5 .2v.3l-.2 .2-.6-.1M213.2 52.7l.5-.1 .2 .3-.8 .9h.8M213.2 55.3l.3-.4v1.2M213.2 56.1h.7M213.3 57.4l.2-.1a.64 .64 0 0 1 .4 .6 .64 .64 0 0 1-.5 .6l-.2-.2zM213.4 47.8l-.2 .8h.7M213.7 43l-.5 .3v.8h.6l.1-.4-.3-.3h-.2l-.2 .3M213.7 48.2v.7M213.8 45.4h-.6v.6l.4-.2 .3 .3-.1 .4h-.6"/>
<path d="M215.6 41.7l.3-1.2 .4 1.2M215.6 46.4l.3-1.2 .4 1.2M215.6 51.2l.3-1.2 .4 1.2M215.6 44l.3-1.2 .4 1.2M215.6 41.3h.6M215.6 43.7h.6M215.6 50.9h.6M215.6 46.1h.6M215.7 54.8h.5a.66 .66 0 0 1 .2 .7 .66 .66 0 0 1-.7 .5zM215.7 59.5a.66 .66 0 0 1 .7 .5 .66 .66 0 0 1-.2 .7h-.5zM215.7 57.1a.6 .6 0 0 1 .7 .6 .6 .6 0 0 1-.7 .6zM216.7 45.6l.3-.4v1.2"/>
<path d="M216.7 50.3l.3-.3v1.2M216.7 46.4h.6M216.7 51.2h.6M216.7 54.8h.9l-.5 1.2M216.9 41l-.2-.3v-.2h.6a.44 .44 0 0 1-.1 .4 .44 .44 0 0 1-.5 .2 .35 .35 0 0 0 .1 .5 .35 .35 0 0 0 .5-.1 .35 .35 0 0 0-.2-.5M217.3 43.3l-.4 .3-.2-.3v-.2a.35 .35 0 0 1 .3-.3 .35 .35 0 0 1 .3 .3l-.1 .8-.5 .1M217.4 59.5h-.5l-.1 .6 .6-.1v.7l-.6-.1M217.4 57.1l-.4 .1-.2 .9a.35 .35 0 0 0 .4 .2 .35 .35 0 0 0 .3-.2v-.3l-.2-.2-.5 .2M217.8 45.6l.3-.4v1.2M217.8 46.4h.7M217.9 50h.2a.68 .68 0 0 1 .4 .6 .68 .68 0 0 1-.4 .6 .81 .81 0 0 1-.2-1.2zM229.6 42.2h7.2"/>
<path d="M229.6 44.5h7.2M229.6 46.9h7.2M229.6 49.3h7.2M229.6 51.6h7.2M229.6 54h7.2M229.6 56.5h7.2M229.6 58.8h7.2M229.9 56l.3-1.2 .4 1.2M229.9 44l.3-1.2 .4 1.2M229.9 51.2l.3-1.2 .4 1.2M229.9 53.6l.3-1.2 .4 1.2M229.9 48.8l.3-1.2 .4 1.2"/>
<path d="M229.9 46.4l.3-1.2 .4 1.2M229.9 41.7l.3-1.2 .4 1.2M230 41.3h.5M230 43.7h.5M230 50.9h.5M230 46.1h.5M230 48.4h.5M230 53.3h.5M230 55.6h.5M230 57.1a.6 .6 0 0 1 .7 .6 .6 .6 0 0 1-.7 .6zM230 59.5a.66 .66 0 0 1 .7 .5 .66 .66 0 0 1-.2 .7h-.5zM230.9 47.6h.7l-.4 .5h.4v.2v.5l-.7-.1"/>
<path d="M231 50.1l.4-.1 .2 .3-.7 .9h.7M231 52.7l.3-.3v1.2M231 53.6h.6M231.1 54.9l.4-.1a.86 .86 0 0 1-.1 1.2l-.3-.1zM231.1 59.9l.4-.4v1.2M231.2 57.2l.4-.1a.78 .78 0 0 1 0 1.2h-.4zM231.2 45.1l-.2 1h.7M231.6 42.8h-.5l-.1 .6 .1-.1h.5v.6h-.6M231.6 40.5l-.5 .1-.1 .8a.35 .35 0 0 0 .3 .3 .35 .35 0 0 0 .3-.3v-.3l-.2-.2-.4 .2M231.6 45.6v.8M234.7 50.5l.3-.4v1.2M234.7 52.9l.3-.3v1.2"/>
<path d="M234.7 55.3l.3-.4v1.2M234.7 57.7l.3-.4v1.2M234.7 53.8h.7M234.7 56.1h.7M234.7 58.5h.7M234.7 51.3h.7M235.2 43h.8l-.5 1.2M235.5 45.9l-.2-.1v-.3h.6v.3l-.6 .2v.5l.2 .1 .4-.1 .1-.2-.3-.4M235.8 40.6h-.3l-.2 .3v.8l.4 .1 .3-.2-.1-.5h-.2h-.4v.2M235.8 52.9l.3-.3v1.2M235.8 55h.7v.5l-.7 .6h.7M235.8 57.3h.7l-.4 .4 .4 .2v.5h-.7"/>
<path d="M235.8 53.8h.7M236 48.3l-.3 .2-.4-.1v-.5l.4-.1a.81 .81 0 0 1 0 1.1h-.3M236 50.2l.2-.1 .3 .3v.7l-.2 .2h-.3l-.2-.4zM236.1 59.6l-.3 .9h.8M237.6 40.3l.4-1.2 .4 1.2M237.6 42.7l.4-1.2 .4 1.2M237.6 45l.4-1.1 .4 1.1M237.6 47.4l.4-1.2 .4 1.2M237.6 49.8l.4-1.2 .4 1.2M237.6 52.2l.4-1.1 .4 1.1M237.6 54.6l.4-1.2 .4 1.2M237.6 57l.4-1.2 .4 1.2"/>
<path d="M237.7 58.2a.61 .61 0 0 1 .8 .6 .61 .61 0 0 1-.8 .6zM237.7 42.3h.6M237.7 44.7h.6M237.7 47.1h.6M237.7 49.4h.6M237.7 51.9h.6M237.7 54.3h.6M237.7 56.6h.6M238.7 48.6h.7l-.4 .5h.4v.2v.5l-.7-.1M238.8 51.1h.6v.3l-.7 .8h.7M238.8 53.8l.3-.4v1.2M238.8 54.6h.6"/>
<path d="M238.8 55.9l.4-.1a.78 .78 0 0 1 0 1.2l-.4-.1zM239 46.2l-.2 .9h.7M239 58.3l.4-.1a.78 .78 0 0 1 0 1.2l-.4-.1zM239.4 41.5l-.5 .1-.1 .8a.35 .35 0 0 0 .3 .3 .35 .35 0 0 0 .3-.3v-.2l-.2-.3-.4 .3M239.4 43.9h-.6v.5l.1-.1 .5 .1v.6h-.6M239.4 46.7v.7M247.2 40.3l.4-1.2 .4 1.2M247.2 47.4l.4-1.2 .4 1.2M247.2 52.2l.4-1.1 .4 1.1M247.3 47.1h.6M247.3 51.9h.6M247.9 48.6l-1 1.5"/>
<path d="M248 53.3l-1 1.6M248.3 42.7l.5-1.2 .4 1.2M248.3 45l.5-1.1 .4 1.1M248.3 46.6l.4-.4v1.2M248.3 51.4l.4-.3v1.1M248.3 55.8l.6 .2 .1 .3-.1 .5-.3 .2h-.3zM248.3 58.2l.6 .1 .1 .4-.1 .5-.3 .2h-.3zM248.3 40.3h.7M248.3 47.4h.7M248.3 52.2h.7M248.4 48.7h.5a.87 .87 0 0 1 0 1.1h-.5a.87 .87 0 0 1 0-1.1zM248.4 42.3h.6"/>
<path d="M248.4 44.7h.6M249.1 53.5l-.5-.1a.67 .67 0 0 0-.3 .7 .67 .67 0 0 0 .5 .5l.3-.2M249.4 55.8h.8l-.5 1.2M249.5 46.6l.4-.4v1.2M249.5 51.2l.2-.1a.6 .6 0 0 1 .6 .4 .6 .6 0 0 1-.3 .7h-.2l-.3-.2zM249.5 47.4h.7M249.6 49.2h.4M249.6 53.9h.4M249.7 42l-.2-.1v-.3h.6v.3l-.6 .2v.5l.2 .1h.2l.3-.3-.3-.4M250 58.2l-.5 .2v.9h.6l.1-.5-.3-.2h-.2l-.2 .2M250.2 44.4l-.3 .2-.4-.2v-.5h.4a.73 .73 0 0 1 0 1.1h-.3M250.2 48.6h-.6v1.2h.6"/>
<path d="M250.2 53.4h-.6v1.2h.6M251.1 42.2h7.1M251.1 44.5h7.1M251.1 46.9h7.1M251.1 51.6h7.1M251.1 56.5h7.1M251.1 58.8h7.1M251.4 40.7l.6-.1 .1 .4-.8 .8h.8M251.4 43.1l.4-.1 .3 .3-.8 .9h.8M251.4 45.5l.4-.1 .3 .3-.8 .9h.8M251.4 47.9l.4-.1 .3 .3-.8 .8h.8M251.4 50.3l.4-.2 .3 .4-.8 .8h.8"/>
<path d="M251.4 52.7l.6-.1 .1 .3-.8 .9h.8M251.4 55l.6-.1 .1 .4-.8 .8h.8M251.4 57.4l.4-.1 .3 .4-.8 .8h.8M252.5 40.6h.7l-.5 1.2M252.5 50.1h.7l-.4 .5 .4 .2v.3l-.1 .2-.6-.1M252.5 52.7l.6-.1 .1 .1v.4l-.7 .7h.7M252.5 55.3l.3-.4v1.2M252.5 56.1h.7M252.6 57.4l.2-.1a.62 .62 0 0 1 .5 .6 .62 .62 0 0 1-.5 .6 .7 .7 0 0 1-.2-1.1zM252.8 47.8l-.3 .8h.7M253.1 43h-.3a.73 .73 0 0 0-.1 1.2l.5-.1v-.4l-.2-.3h-.3l-.2 .3M253.1 48.2v.7"/>
<path d="M253.2 45.4h-.6l-.1 .6 .1-.2h.4l.2 .3v.4h-.7M254.8 41.7l.5-1.2 .4 1.2M254.8 46.4l.5-1.2 .4 1.2M254.8 51.2l.5-1.2 .4 1.2M254.8 44l.5-1.2 .4 1.2M255 54.8h.5l.2 .2v.7l-.3 .3h-.4zM255 57.1h.4l.3 .3v.7l-.3 .2h-.4zM255 59.5h.4l.3 .3v.7l-.2 .2h-.5zM255 41.3h.5M255 43.7h.5M255 50.9h.5M255 46.1h.5"/>
<path d="M256 45.6l.4-.4v1.2M256 50.3l.4-.3v1.2M256 46.4h.7M256 51.2h.7M256.1 54.8h.9l-.5 1.2M256.2 41l-.2-.4 .6-.1v.4l-.6 .2v.5l.5 .1a.35 .35 0 0 0 .2-.4 .35 .35 0 0 0-.2-.3M256.7 43.3l-.2 .3h-.3l-.2-.2v-.5l.5-.1 .2 .3-.2 .8-.4 .1M256.8 57.1l-.6 .3 .1 .9a.36 .36 0 0 0 .6-.2l-.1-.4-.2-.1-.4 .2M256.8 59.5h-.6v.6l.6-.1v.7l-.6-.1M257.1 45.6l.4-.4v1.2M257.1 46.4h.7M257.3 50h.3l.2 .2v.8l-.2 .2a.71 .71 0 0 1-.3-1.2z"/>
<path d="M18.5 62.7h1.8M23.4 61.2h7.7M23.4 63.6h7.7M23.4 66h7.7M23.4 68.3h7.7M23.4 70.8h7.7M23.4 73.2h7.7M23.4 75.5h7.7M23.4 77.9h7.7M24.7 60.7l.4-1.2 .5 1.2M24.7 63.1l.4-1.2 .5 1.2M24.7 65.5l.4-1.2 .5 1.2"/>
<path d="M24.9 76.2l.5 .1 .2 .2v.6l-.2 .3h-.5zM24.9 71.5h.3l.4 .2v.7l-.4 .2h-.3zM24.9 73.8h.3l.4 .3v.7l-.2 .2h-.5zM24.9 66.7h.5l.2 .3v.6l-.4 .3h-.3zM24.9 69.1h.5l.2 .2v.7l-.4 .3h-.3zM24.9 60.4h.5M24.9 62.7h.5M24.9 65.2h.5M25.9 62.2l.3-.3v1.2M25.9 64.5l.3-.2a.68 .68 0 0 1 .4 .6 .68 .68 0 0 1-.4 .6l-.3-.2zM25.9 63.1h.7M26 73.8h.8l-.5 .5 .5 .2v.3l-.2 .2-.6-.1"/>
<path d="M26.1 71.5h.4l.3 .3-.8 .8h.8M26.1 66.9l.1-.2a.6 .6 0 0 1 .6 .4 .6 .6 0 0 1-.2 .7l-.3 .1-.2-.3zM26.1 69.4l.3-.3v1.2M26.1 70.3h.7M26.3 76.2l-.2 .8h.7M26.6 76.6v.8M27.1 60.1h.3M27.1 62.5h.3M27.1 64.9h.3M27.3 67.2h.3M27.3 76.8h.3M27.3 72.1h.3"/>
<path d="M27.3 74.4h.3M27.3 69.7h.3M27.6 61.9h-.5v1.2h.5M27.6 64.3h-.5v1.2h.5M27.8 76.2h-.5v1.2h.5M27.8 71.5h-.5v1.1h.5M27.8 73.8h-.5v1.2h.5M27.8 66.7h-.5v1.2h.5M27.8 69.1h-.5v1.2h.5M28.9 64.4h.7l-.4 .5h.3v.7l-.6-.1M28.9 74h.8l-.5 1.2M29 60l.3-.3v1.2"/>
<path d="M29 62.2l.4-.1 .2 .3-.7 .8h.7M29 60.9h.6M29.2 66.8l-.2 .8h.7M29.2 76.9h-.2a.31 .31 0 0 1 .1-.4 .31 .31 0 0 1 .4 0v.4l-.5 .1v.6h.5l.1-.5-.2-.2M29.5 69.3h-.5v.5h.5v.6h-.4l-.1-.1M29.5 71.6l-.4 .1-.1 .9a.35 .35 0 0 0 .3 .2 .35 .35 0 0 0 .3-.2v-.3l-.2-.2-.4 .2M29.5 67.2v.9M34.6 61.2h7.8M34.6 63.6h7.8M34.6 66h7.8M34.6 68.3h7.8M34.6 70.8h7.8"/>
<path d="M34.6 73.2h7.8M34.6 75.5h7.8M34.6 77.9h7.8M35.6 60l.3-.3v1.2M35.6 62.4l.3-.3v1.1M35.6 64.8l.3-.4v1.2M35.6 67.2l.3-.3v1.2M35.6 69.6l.3-.3v1.1M35.6 72l.3-.4v1.2M35.6 74.3l.3-.3v1.2M35.6 60.9h.6M35.6 63.2h.6"/>
<path d="M35.6 65.6h.6M35.6 68.1h.6M35.6 70.4h.6M35.6 72.8h.6M35.6 75.2h.6M36.7 66.9h.6l-.3 .4 .3 .1v.5l-.1 .2h-.4l-.1-.2M36.7 69.3h.6v.5l-.6 .6h.6M36.7 72l.3-.4v1.2M36.7 72.8h.6M36.8 74.1l.3-.1 .2 .3v.6l-.3 .3a.7 .7 0 0 1-.2-1.1zM36.8 76.9l-.2 .2-.4-.1v-.5l.4-.1a.81 .81 0 0 1 0 1.2h-.4M37 64.4l-.3 .9h.7"/>
<path d="M37.3 64.9v.7M37.3 62.1h-.6v.6l.6-.1v.6h-.6M39 63.1l.5-1.2 .4 1.2M39 60.7l.5-1.2 .4 1.2M39 65.5l.5-1.2 .4 1.2M39.2 69.1h.5l.2 .2v.7l-.4 .3h-.3zM39.2 71.5h.3l.4 .2v.7l-.4 .2h-.3zM39.2 66.7h.5l.2 .3v.6l-.4 .3h-.3zM39.2 73.8h.3l.4 .3v.7l-.2 .2h-.5zM39.2 76.2h.3l.4 .3v.6l-.2 .3h-.5zM39.2 60.4h.5M39.2 62.7h.5"/>
<path d="M39.2 65.2h.5M40.2 62.2l.4-.3v1.2M40.2 64.5l.3-.2a.68 .68 0 0 1 .4 .6 .68 .68 0 0 1-.4 .6l-.3-.2zM40.2 63.1h.7M40.3 73.8h.8l-.5 .5 .5 .2v.3l-.2 .2-.6-.1M40.4 69.4l.3-.3v1.2M40.4 71.5h.4l.3 .3-.8 .8h.8M40.4 66.9l.2-.2a.6 .6 0 0 1 .5 .4 .6 .6 0 0 1-.2 .7l-.3 .1-.2-.3zM40.4 70.3h.7M40.6 76.2l-.2 .8h.7M40.9 76.6v.8M45.6 75.6h1"/>
<path d="M46.1 75.2v.8M47.2 77.9v2.4M47.2 77.9l-.7 1.2M47.2 77.9l.7 1.2M47.5 72.6a.45 .45 0 0 0-.7 .1v.7l.2 .3h.5v-.5h-.2M47.7 74.8h-.5l-.1 .6h.6v.6l-.6-.1M48.1 74.8l.4 1.2 .4-1.2M48.3 68.3v1.2h1.3l-1.3 1.3-1.1-1.3h1.1M48.3 68.3h.1M48.3 61.2h8.4M48.3 63.6h8.4M48.3 66h8.4"/>
<path d="M48.3 68.3h8.4M48.6 78.6l.4 1.2 .4-1.2M48.7 72.5v1.2l-.7-1.2v1.2M48.8 61.9a.66 .66 0 0 1 .6 .4 .66 .66 0 0 1-.2 .8h-.4zM48.8 64.3a.64 .64 0 0 1 .6 .6 .64 .64 0 0 1-.6 .6zM49.3 72.5h.3l.4 .2v.7l-.2 .3h-.5zM49.8 79.2h.6v-.5l-.6-.1v1.2M49.9 62.2h.1l.2-.3v1.2M49.9 64.4l.1-.1h.4l.1 .1v.5l-.6 .6h.6M49.9 63.1h.6M50.8 76v1.2h.6M51 79.2h.6v-.5l-.6-.1v1.2"/>
<path d="M51.1 60.1h.4M51.1 62.5h.4M51.1 64.9h.4M51.6 61.9h-.5v1.2h.5M51.6 64.3h-.5v1.2h.5M51.7 76.9l.6-.2-.1-.2-.5 .1v.4l.1 .2h.4M52.7 76.5h.4M53.1 76l-.3 .1v1.1M53.3 76.5h.5M53.5 76v1l.3 .2M54 60l.4-.3v1.2M54 62.4h.2l.2-.3v1.1"/>
<path d="M54 64.8h.2l.2-.4v1.2M54 67.2l.4-.3v1.2M54 60.9h.7M54 63.2h.7M54 65.6h.7M54 68.1h.7M54.6 79.1l.3-.4v1.2M54.6 79.9h.7M55.1 76.6h.4M55.5 62.1l-.3 .8h.7M55.6 76h-.5v1.2h.5M55.7 66.9h-.3l-.2 .2v.8l.4 .2 .3-.3-.1-.4-.2-.1-.4 .1v.2"/>
<path d="M55.7 62.5v.7M55.8 64.4h-.6v.6l.5-.1 .2 .2v.3l-.2 .2-.5-.1M56.1 76.7h.5l.2-.2v-.3l-.2-.2h-.5v1.2M56.7 61h1.2v.3h-1.2zM56.7 63.5h1.2v.2h-1.2zM56.7 65.9h1.2v.2h-1.2zM56.7 68.2h1.2v.3h-1.2zM57.3 76.7h.5l.3-.4-.3-.3h-.5v1.2M57.7 76.7l.4 .5M58.8 76l.5 .2v.8l-.2 .2h-.4a.86 .86 0 0 1 .1-1.2zM58.8 73.7v.8l-.3 .3h-.2M59.3 73.8l.4-.1 .2 .3-.7 .8h.7"/>
<path d="M59.8 77.2v-1.2l.4 .9 .4-.9v1.2M60.3 61h1.2v.3h-1.2zM60.3 63.5h1.2v.2h-1.2zM60.3 65.9h1.2v.2h-1.2zM60.3 68.2h1.2v.3h-1.2zM61.5 61.2h8.4M61.5 63.6h8.4M61.5 66h8.4M61.5 68.3h8.4M62.3 78.7h.8l-.4 .5 .4 .2v.4l-.2 .1-.6-.1M62.4 62.4l.3-.3v1.1M62.4 64.8l.3-.4v1.2"/>
<path d="M62.4 67.2l.3-.3v1.2M62.4 75.9a1.44 1.44 0 0 0 0 1.8M62.4 63.2h.7M62.4 65.6h.7M62.4 68.1h.7M62.9 76v1.2M63.5 78.9l.2-.2h.3l.2 .2v.3l-.7 .7h.7M63.5 66.9h.8l-.5 1.2M63.8 64.9l-.3-.2 .3-.3h.2l.2 .5h-.4l-.3 .3 .2 .4 .5-.1v-.4l-.2-.2M64.1 76.2l-.3-.2-.4 .4v.6l.2 .2 .5-.1M64.2 62.6v.1l-.4 .1-.3-.2v-.3l.3-.2 .4 .1v.8l-.2 .2h-.3M64.5 76h.8l-.4 .5 .4 .2v.3l-.2 .2-.6-.1"/>
<path d="M65.7 76.2l.4-.2 .3 .4-.8 .8h.8M66.6 64.3h.5l.2 .3v.6l-.3 .3h-.4zM66.6 66.7h.5l.2 .3v.6l-.3 .3h-.4zM66.6 61.9h.4l.3 .3v.6l-.2 .3h-.5zM67.7 66.7h.8l-.4 .4 .3 .1 .1 .4-.3 .3h-.3l-.2-.2M67.8 76.5h.4l.1 .1v.6M67.8 76v1.2M68.1 64.3l-.3 .8h.7M68.3 64.7v.8M68.4 61.9h-.6v.6l.5-.1 .2 .2v.3l-.2 .2-.5-.1M68.9 76v.2M68.9 76.5v.7"/>
<path d="M69 60.1h.3M69 62.5h.3M69 64.9h.3M69 67.2h.3M69.5 64.3h-.5v1.2h.5M69.5 66.7h-.5v1.2h.5M69.5 61.9h-.5v1.2h.5M69.9 76.5v1.1h-.5M69.9 76.5h-.5v.6l.5 .1M70.5 76.5h.4l.1 .1v.6M70.5 76v1.2M71.5 76.9l.6-.2-.1-.2-.5 .1v.4l.1 .2h.5"/>
<path d="M72.6 76.5v.7M73 76.5l-.4 .2M73.2 75.9l.4 .5v.8l-.4 .5M75.4 75.6h1M75.9 75.2v.8M76.1 60.6l-.3-.1-.4 .4v.6l.2 .2h.5v-.5h-.2M77 77.9v4.3M77 77.9l-.7 1.2M77 77.9l.7 1.2M77.3 60.5v1.2l-.7-1.2v1.2M77.5 74.8h-.5l-.1 .6h.6v.6l-.6-.1M77.9 60.5l.5 .1 .2 .3v.6l-.2 .2h-.5z"/>
<path d="M77.9 74.8l.4 1.2 .4-1.2M87.7 63.6v1.2h1.2l-1.2 1.2-1.2-1.2h1.2M87.7 63.6h.1M87.7 61.2v2.4M90.3 79.8l.5-1.2 .3 1.2M90.4 63.8a.45 .45 0 0 0-.7 .1v.7a.45 .45 0 0 0 .7 .2v-.5h-.1M90.4 79.5h.6M90.5 61.7v-1.2l.4 .9 .4-.9v1.2M91.4 79l.4-.4v1.2M91.4 79.8h.7M91.6 63.7v1.2l-.7-1.2v1.2M91.9 61h.5l.1 .6-.2 .1h-.4l-.1-.1z"/>
<path d="M92.2 63.7h.3l.4 .2v.7l-.4 .3h-.3zM92.8 79.2l-.2-.5 .4-.1 .3 .3-.3 .3h-.4v.5l.2 .1h.2l.3-.2v-.3l-.3-.1M93 61v.7l.5-.1M93.5 61v.7M93.8 79.2h.3M93.9 76.6h.3M94.1 61h.3l.2 .1v.6M94.1 61v.7M94.3 78.6h-.5v1.2h.5M94.4 76h-.5v1.2h.5M94.8 76l.8 1.2M94.9 61h.5"/>
<path d="M95.1 60.5v1.1l.1 .1h.2M95.6 76l-.8 1.2M95.8 79.1l.3-.4v1.2M95.8 60.5v.2M95.8 79.9h.6M95.8 61v.7M96.1 76.6l.6-.1v-.3l-.6-.2v1.2h.6l.1-.3-.4-.3M96.4 61h.3l.2 .1v.6M96.4 61v.7M97.2 76.2l.2-.2h.3l.2 .2v.3l-.7 .7h.7M98 61v.9l-.3 .2h-.2M98 61a.36 .36 0 0 0-.6 .2l.1 .5h.5"/>
<path d="M98.1 74.3h.5l.2-.1v-.4l-.2-.1h-.5v1.1M98.4 76.6h.7M98.4 76v1.2M98.5 74.3l.3 .5M98.6 60.5v1.2M98.6 61.1h.6M99.1 76v1.2M99.2 60.5v1.2M99.5 76l.4 1.2 .3-1.2M99.7 61h.5v.7l-.5-.1zM100 73.7v1.1l-.7-1.1v1.1M100.5 73.8l.2-.1h.3l.2 .1v.4l-.7 .6h.7"/>
<path d="M100.8 60.5v1.1l.2 .1M100.9 76l-.3 .9h.7M101.2 76.5v.7M101.4 61.4l.5-.2v-.2h-.5v.7h.5M101.7 76h.8l-.5 1.2M102.2 61.9h.9M102.4 79.1l.3-.4v1.2M102.4 79.9h.6M103 76.1l.3-.1 .2 .3v.7l-.1 .2h-.4l-.1-.4zM103.4 61.2h.5l.2-.2v-.3l-.2-.2h-.5v1.2M104.1 78.7h-.3a.93 .93 0 0 0-.3 1.2h.6v-.5v-.2h-.6v.2M104.4 76v1l-.4 .2"/>
<path d="M104.6 61h.5v.7h-.5v-.3l.5-.2M104.8 76l.4 1.2 .4-1.2M105.8 79.8l.5-1.2 .3 1.2M105.9 79.5h.6M106.2 60.5v1.2h-.5l-.1-.1 .1-.6h.5M106.9 79l.4-.4v1.2M106.9 79.8h.7M108.3 79.2l-.2-.5 .4-.1 .3 .3-.3 .3h-.4v.5l.2 .1h.2l.3-.2v-.3l-.3-.1M110.7 73.7h-.1a.66 .66 0 0 0-.6 .4 .66 .66 0 0 0 .2 .7h.5v-.5h-.2M111.6 69.5v1.3h1.2l-1.2 1.2-1.2-1.2h1.2M111.6 69.5h.1M111.6 61.2h7.1"/>
<path d="M111.6 63.6h7.1M111.9 61.9l.5 .1 .2 .2v.6l-.2 .3h-.5zM111.9 73.7v1.1l-.6-1.1v1.1M112.5 73.7a.66 .66 0 0 1 .7 .4 .66 .66 0 0 1-.3 .7h-.4zM113.1 62.2l.4-.3v1.2M113.1 63.1h.7M113.8 60l-.3 .3-.4-.1v-.6l.4-.1 .3 .3-.2 .8-.4 .1M114.4 62l.2-.1 .3 .2v.8l-.2 .2h-.3l-.2-.4zM116.7 60l.3-.3v1.2M116.7 62.4l.3-.3v1.1M116.7 64.8l.3-.4v1.2M116.7 60.9h.6"/>
<path d="M116.7 63.2h.6M116.7 65.6h.6M117.5 73.2h.1M117.5 70.8v3.8l1 .3-1.9 .7 1.9 .8-1.9 .6 1.9 .8-1.9 .7 .9 .3v25.3h12.5M117.5 70.8l-.7 1.2M117.5 70.8l.8 1.2M118.4 62.1h-.5l-.1 .6 .6-.1v.6h-.6M118.4 64.4h-.3a.93 .93 0 0 0-.2 1.2h.5v-.5v-.2h-.5l-.1 .2M118.4 60.1v.8M118.7 66h-7.1v3.5M118.9 71.5h.9M119.3 71.1v.9"/>
<path d="M119.7 60.5l.5 .1 .2 .3v.6l-.2 .2h-.5zM119.7 62.9h.4l.3 .3v.6l-.3 .4h-.4zM120.3 75.5l.6-.1v-.5l-.6-.1v1.2M120.4 65.4h-.5l-.2 .2v.6l.2 .3h.5v-.5h-.2M120.6 77.2l-.4 .9h.8M120.6 75.5l.4 .5M120.8 77.6v.9M120.9 60.9l.3-.4v1.2M120.9 63.1l.4-.2 .3 .3-.8 1h.8M120.9 70.8h-.6v.6l.5-.1 .2 .2v.3l-.2 .2-.5-.1M120.9 61.7h.7M121.3 70.8l.5 1.2 .3-1.2"/>
<path d="M121.4 78.3v.2M121.6 65.4v1.1l-.7-1.1v1.1M121.9 77.2h.8l-.5 1.3M122.1 74.8h-.6l-.1 .6h.6l.2 .1v.4l-.2 .1-.6-.1M122.2 65.4h.4a.66 .66 0 0 1 .2 .7 .66 .66 0 0 1-.6 .4zM123.2 77.2v1.3M123.3 78l.3 .5M123.4 69.8h-.6l-.1 .6h.6l.1 .6h-.7M123.6 77.6l-.4 .5M124 78.5h.4v-.3l-.4-.3 .1-.5 .3-.2 .5 .2a.6 .6 0 0 1-.2 .8v.3h.3M124.4 68h.7M124.5 69.8h-.6v.6h.5l.1 .1v.4l-.1 .1h-.5"/>
<path d="M124.7 68v1.2M125.1 69.9l.3-.1 .2 .3v.8l-.1 .1h-.4l-.1-.4zM125.5 68v1.2M125.6 78.5v.9l.2 .3 .4-.3v-.9M125.6 68.5l.6 .7M126.1 69.8h.7l-.4 .6 .4 .1v.4l-.1 .1h-.6M126.2 68l-.7 .7M126.6 68.1h.7v.4l-.7 .7h.7M126.7 78.8l.4-.3v1.2M126.7 79.7h.7M127.3 70.2l.3-.4v1.2M127.3 71h.6"/>
<path d="M128.6 70.4l-.2-.3 .2-.3h.3l.1 .5-.4 .1-.2 .2 .1 .4h.5v-.5l-.1-.1M128.6 78.6l-.5-.1-.2 .2 .1 .8 .3 .2 .3-.2M130.3 60.5a.66 .66 0 0 1 .7 .5 .66 .66 0 0 1-.3 .7h-.4zM130.3 62.9a.64 .64 0 0 1 .7 .6 .64 .64 0 0 1-.7 .7zM130.3 65.4h.4a.66 .66 0 0 1 .3 .7 .66 .66 0 0 1-.7 .4zM131.4 65.4h.7l-.4 .4 .4 .1v.5l-.2 .1h-.3l-.2-.1M131.7 62.9l-.3 .9h.8M132 63.3v.9M132.1 60.5h-.6l-.1 .6 .6-.1 .1 .6h-.7M133 61.2h7.2M133 63.6h7.2M133 66h7.2"/>
<path d="M133.4 60l.3-.3v1.2M133.4 62.4l.3-.3v1.1M133.4 64.8l.3-.4v1.2M133.4 60.9h.6M133.4 63.2h.6M133.4 65.6h.6M134.4 64.4h.8l-.5 1.2M134.7 62.6l-.2-.3 .2-.2h.3l.1 .4-.4 .1-.2 .2 .1 .4h.5v-.5l-.1-.1M135.1 60.2l-.1 .3h-.3l-.2-.3v-.4h.6v.8l-.5 .3M137 64.3a.64 .64 0 0 1 .7 .6 .64 .64 0 0 1-.7 .6zM137 61.9a.66 .66 0 0 1 .6 .4 .66 .66 0 0 1-.2 .8h-.4zM138.2 64.6l.3-.3v1.2"/>
<path d="M138.2 62.2l.3-.3v1.2M138.2 63.1h.7M138.2 60.7h.7M138.2 65.5h.7M139.3 64.6l.3-.3v1.2M139.3 62.1l.4-.2 .3 .3-.8 .9h.8M139.3 65.5h.7M150 73.7h-.1a.66 .66 0 0 0-.5 .4 .66 .66 0 0 0 .2 .7h.5v-.5h-.2M151 69.5v1.3h1.1l-1.1 1.2-1.2-1.2h1.2M151 69.5h.1M151 61.2h7.1M151 63.6h7.1"/>
<path d="M151.3 61.9a.66 .66 0 0 1 .7 .4 .66 .66 0 0 1-.3 .8h-.4zM151.3 73.7v1.1l-.7-1.1v1.1M151.8 73.7h.3l.4 .3v.6l-.2 .2h-.5zM152.5 62.2l.3-.3v1.2M152.5 63.1h.7M153.2 60l-.3 .3-.4-.1v-.6l.4-.1 .3 .3-.2 .8-.4 .1M153.8 61.9a.75 .75 0 0 1 .3 1.2h-.3l-.2-.4 .1-.6zM156 60l.3-.3v1.2M156 62.4h.1l.2-.3v1.1M156 64.8h.1l.2-.4v1.2M156 60.9h.6M156 63.2h.6"/>
<path d="M156 65.6h.6M157.6 64.4l-.3 .1-.2 .3v.7l.5 .1 .2-.2v-.3l-.2-.2h-.4l-.1 .2M157.6 60.1v.8M157.7 62.1h-.6v.6l.5-.1 .2 .1v.4l-.2 .1h-.5M158.1 66h-7.1v3.5M159.1 60.5a.66 .66 0 0 1 .6 .5 .66 .66 0 0 1-.2 .7h-.4zM159.1 62.9a.64 .64 0 0 1 .7 .6 .64 .64 0 0 1-.7 .7zM159.7 65.4h-.4a.67 .67 0 0 0-.3 .6 .67 .67 0 0 0 .5 .5l.3-.1v-.4h-.3M160.2 60.9h.2l.1-.4v1.2M160.2 63.1l.2-.2h.3l.2 .2v.3l-.7 .8h.7M160.2 61.7h.7M161 65.4v1.1l-.7-1.1v1.1"/>
<path d="M161.5 65.4h.5a.66 .66 0 0 1 .2 .7 .66 .66 0 0 1-.7 .4zM162.6 69.4h-.5v.5h.5v.6l-.4 .1-.1-.2M163.7 67.5h.7M163.8 69.4h-.6v.5h.6l.1 .5-.2 .2-.5-.2M164.1 67.5v1.2M164.4 69.5l.1-.1a.59 .59 0 0 1 .6 .4 .59 .59 0 0 1-.2 .6l-.1 .2-.4-.2zM164.8 67.5v1.2M165 68l.5 .7M165.4 69.4h.7l-.3 .4 .3 .1v.5l-.2 .2h-.3l-.2-.2M165.5 67.5l-.7 .7M166.2 67.4l-.3 .8h.8M166.5 67.9v.8"/>
<path d="M166.6 69.5l.5-.1 .2 .4-.8 .8h.8M167.9 69.4h.3l.2 .2v.8l-.3 .2a.71 .71 0 0 1-.2-1.2zM169.7 60.5a.66 .66 0 0 1 .6 .5 .66 .66 0 0 1-.2 .7h-.4zM169.7 62.9a.64 .64 0 0 1 .7 .6 .64 .64 0 0 1-.7 .7zM169.7 65.4h.4a.66 .66 0 0 1 .2 .7 .66 .66 0 0 1-.6 .4zM170.7 65.4h.8l-.5 .4 .5 .2-.1 .5h-.5l-.2-.1M171 62.9l-.2 .9h.7M171.4 60.5h-.5l-.1 .6 .6-.1v.7l-.6-.1M171.4 63.3v.9M172.4 61.2h7.2M172.4 63.6h7.2M172.4 66h7.2"/>
<path d="M172.7 60l.4-.3v1.2M172.7 62.4l.4-.3v1.1M172.7 64.8l.4-.4v1.2M172.7 60.9h.7M172.7 63.2h.7M172.7 65.6h.7M173.7 64.4h.9l-.5 1.2M174.1 62.6h-.2a.31 .31 0 0 1 .1-.5 .31 .31 0 0 1 .4 .1v.4l-.5 .1v.5h.5l.1-.1v-.3l-.3-.2M174.5 60.2l-.4 .3-.2-.1-.1-.5a.35 .35 0 0 1 .4-.2 .35 .35 0 0 1 .3 .2l-.2 .9-.4 .1M176.4 64.3a.64 .64 0 0 1 .6 .6 .64 .64 0 0 1-.6 .6zM176.4 61.9a.66 .66 0 0 1 .6 .4 .66 .66 0 0 1-.2 .8h-.4zM177.5 64.6h.1l.2-.3v1.2"/>
<path d="M177.5 62.2h.1l.2-.3v1.2M177.5 63.1h.6M177.5 60.7h.6M177.5 65.5h.6M178.6 64.6l.4-.3v1.2M178.6 62.1l.5-.2 .2 .3-.7 .9h.7M178.6 65.5h.7M189.4 73.7h-.3l-.4 .3v.6l.2 .2h.5v-.5h-.2M190.2 69.5v1.3h1.3l-1.3 1.2-1.1-1.2h1.1M190.2 69.5h.1M190.2 61.2h7.2M190.2 63.6h7.2"/>
<path d="M190.6 73.7v1.1l-.7-1.1v1.1M190.7 61.9a.66 .66 0 0 1 .6 .4 .66 .66 0 0 1-.2 .8h-.4zM191.2 73.7h.3l.4 .3v.6l-.2 .2h-.5zM191.8 62.1l.1-.2h.4l.1 .2v.3l-.6 .7h.6M191.8 60.7h.6M195.3 60l.4-.3v1.2M195.3 62.4l.4-.3v1.1M195.3 64.8l.4-.4v1.2M195.3 60.9h.7M195.3 63.2h.7M195.3 65.6h.7M196.3 79.1v13.1h-11.4"/>
<path d="M197 64.4l-.3 .1-.2 .3v.7l.5 .1 .2-.2v-.3l-.2-.2h-.4l-.1 .2M197 60.1v.8M197.1 62.1h-.6v.6l.5-.1 .2 .1v.4l-.2 .1h-.5M197.4 66h-7.2v3.5M198.5 60.5a.66 .66 0 0 1 .6 .5 .66 .66 0 0 1-.2 .7h-.4zM198.5 62.9a.64 .64 0 0 1 .6 .6 .64 .64 0 0 1-.6 .7zM199.1 65.4h-.5a.67 .67 0 0 0-.2 .6 .67 .67 0 0 0 .5 .5l.2-.1v-.4h-.2M199.6 60.9l.3-.4v1.2M199.6 63.1l.1-.2 .5 .1v.4l-.7 .8h.7M199.6 61.7h.6M199.8 75.5v14.3h-14.9M200.3 65.4v1.1l-.7-1.1v1.1"/>
<path d="M200.9 65.4h.4a.66 .66 0 0 1 .3 .7 .66 .66 0 0 1-.7 .4zM203 69.8h-.6v.6h.5l.1 .6h-.6M204 68h.7M204.1 69.8h-.6v.6h.5l.2 .1v.4l-.2 .1h-.5M204.4 68v1.2M204.9 69.8a.75 .75 0 0 1 .2 1.2h-.3l-.2-.4 .1-.6zM205.1 68v1.2M205.3 68.5l.5 .7M205.7 69.8h.7l-.3 .6h.3v.6h-.7M205.8 68l-.7 .7M206.2 68.3l.4-.3v1.2M206.2 69.2h.7"/>
<path d="M206.9 70.2l.4-.4v1.2M206.9 71h.7M208 69.8h.8l-.5 1.2M209 60.5l.5 .1 .1 .3v.6l-.1 .2h-.5zM209 62.9h.3l.3 .3v.6l-.3 .4h-.3zM209 65.4h.5l.1 .2v.6l-.3 .3h-.3zM210.1 65.4h.7l-.4 .4 .3 .1 .1 .4-.2 .2h-.4l-.1-.1M210.4 62.9l-.3 .9h.7M210.7 63.3v.9M210.7 60.5h-.6v.6l.6-.1 .1 .2v.4l-.1 .1-.6-.1M211.8 61.2h7.1M211.8 63.6h7.1"/>
<path d="M211.8 66h7.1M212 60l.3-.3v1.2M212 62.4h.2l.1-.3v1.1M212 64.8h.2l.1-.4v1.2M212 60.9h.7M212 63.2h.7M212 65.6h.7M213.1 64.4h.8l-.5 1.2M213.4 62.6l-.2-.1 .2-.4h.2l.3 .2-.2 .3h-.3l-.2 .1 .1 .5h.4l.2-.1v-.3l-.3-.2M213.9 60.2l-.3 .3-.4-.2v-.5l.4-.1a.73 .73 0 0 1-.1 1.2h-.2M215.7 61.9a.66 .66 0 0 1 .7 .4 .66 .66 0 0 1-.2 .8h-.5zM215.7 64.3a.64 .64 0 0 1 .7 .6 .64 .64 0 0 1-.7 .6z"/>
<path d="M216.7 64.3h.8l-.4 .5 .4 .2-.1 .4-.5 .1-.2-.1M217.1 61.9l-.3 .8h.8M217.4 62.3v.8M228.7 73.7h-.1a.66 .66 0 0 0-.6 .4 .66 .66 0 0 0 .3 .7h.5v-.5h-.3M229.6 69.5v1.3h1.2l-1.2 1.2-1.2-1.2h1.2M229.6 69.5h.1M229.6 61.2h7.2M229.6 63.6h7.2M230 73.7v1.1l-.7-1.1v1.1M230 61.9a.66 .66 0 0 1 .7 .4 .66 .66 0 0 1-.2 .8h-.5zM230.5 73.7a.66 .66 0 0 1 .7 .4 .66 .66 0 0 1-.2 .7h-.5zM231.1 62.1l.5-.2 .2 .3-.7 .9h.7"/>
<path d="M231.1 60.7h.7M234.7 60l.3-.3v1.2M234.7 62.4l.3-.3v1.1M234.7 64.8l.3-.4v1.2M234.7 60.9h.7M234.7 63.2h.7M234.7 65.6h.7M236.4 64.4l-.4 .2-.2 .8 .2 .2 .5-.1-.1-.6h-.4l-.2 .2M236.4 60.1v.8M236.5 62.1h-.6l-.1 .6 .6-.1 .1 .6h-.7M236.8 66h-7.2v3.5M237.7 60.5a.66 .66 0 0 1 .8 .4 .66 .66 0 0 1-.2 .8h-.6z"/>
<path d="M237.7 62.9a.65 .65 0 0 1 .8 .6 .65 .65 0 0 1-.8 .7zM238.4 65.4h-.5l-.2 .2v.6l.2 .3h.4l.2-.1v-.4h-.2M238.9 60.9l.4-.4v1.2M238.9 63.1l.5-.2 .2 .3-.8 1h.8M238.9 61.7h.7M239.7 65.4v1.1l-.7-1.1v1.1M240.2 65.4h.5l.2 .2v.6l-.4 .3h-.3zM241.6 69.8h-.6v.6h.6v.6h-.6M242.7 68h.6M242.7 69.8h-.5l-.1 .6h.6v.6h-.6M243 68v1.2M243.4 69.9l.3-.1 .2 .3v.8l-.1 .1h-.4l-.2-.4z"/>
<path d="M243.8 68v1.2M243.9 68.5l.5 .7M244.3 69.8h.8l-.4 .6 .4 .1v.4l-.2 .1h-.6M244.4 68l-.6 .7M244.9 68h.6l-.3 .4 .3 .1v.5l-.1 .2h-.4l-.1-.2M245.5 70.2l.4-.4v1.2M245.5 71h.7M247.4 70.4l-.3 .2-.4-.1v-.5l.4-.2a.81 .81 0 0 1 0 1.2h-.3M248.3 60.5a.66 .66 0 0 1 .7 .5 .66 .66 0 0 1-.2 .7h-.5zM248.3 62.9a.64 .64 0 0 1 .7 .6 .64 .64 0 0 1-.7 .7zM248.3 65.4h.5a.66 .66 0 0 1 .2 .7 .66 .66 0 0 1-.7 .4zM249.4 65.4h.8l-.4 .4 .3 .1 .1 .4-.3 .2h-.3l-.2-.1"/>
<path d="M249.8 62.9l-.3 .9h.7M250 63.3v.9M250.1 60.5h-.6v.6l.5-.1 .2 .2v.4l-.2 .1-.5-.1M251.1 61.2h7.1M251.1 63.6h7.1M251.1 66h7.1M251.4 60l.3-.3v1.2M251.4 62.4l.3-.3v1.1M251.4 64.8l.3-.4v1.2M251.4 60.9h.7M251.4 63.2h.7M251.4 65.6h.7"/>
<path d="M252.5 64.4h.7l-.5 1.2M252.7 62.6l-.2-.2 .2-.3h.3l.2 .2-.1 .3h-.4l-.2 .2 .1 .4h.5l.1-.1v-.3l-.2-.2M253.2 60.2l-.2 .3h-.3l-.2-.3 .1-.4h.6a.78 .78 0 0 1-.4 1.1h-.2M255 64.3h.5l.2 .3v.6l-.3 .3h-.4zM255 61.9l.5 .1 .2 .2v.6l-.2 .3h-.5zM256.1 64.3h.8l-.4 .5 .3 .1v.5l-.5 .1-.2-.1M256.5 61.9l-.3 .8h.8M256.8 62.3v.8M276.6 62.7h1.9M19.1 86.1h.4l.1-.2v-.3l-.5-.1v1.2h.5l.1-.4-.2-.2M23.4 87.5h7.7M23.4 89.8h7.7"/>
<path d="M23.4 92.2h7.7M23.4 94.6h7.7M23.4 96.9h7.7M23.4 99.4h7.7M23.5 99.7h3.3M24.7 96.5l.4-1.2 .5 1.2M24.7 98.9l.4-1.2 .5 1.2M24.9 88.1l.5 .1 .2 .3v.6l-.2 .2h-.5zM24.9 90.5l.5 .1 .2 .2v.6l-.2 .3h-.5zM24.9 93.6l.7-.1v-.5l-.2-.1h-.5v1.2M24.9 85.8h.3l.4 .2v.7l-.4 .3h-.3zM24.9 96.2h.5"/>
<path d="M24.9 98.6h.5M25.2 93.6l.4 .5M25.9 95.4l.5-.1 .2 .4-.8 .8h.8M25.9 98l.3-.3v1.2M25.9 98.9h.7M25.9 92.6h1.2M26 92.9l.2 1.2 .3-.8 .3 .8 .2-1.2M26.1 90.8l.3-.3v1.2M26.1 91.7h.7M26.2 86.3l-.1-.1v-.3h.6v.3l-.6 .2v.5l.1 .1 .5-.1 .1-.2-.3-.4M26.8 88.6l-.3 .3-.4-.1v-.6l.4-.1 .3 .3-.2 .8-.4 .1M27.1 95.4l.1-.1a.59 .59 0 0 1 .5 .4 .59 .59 0 0 1-.1 .7l-.2 .1-.3-.1z"/>
<path d="M27.1 83.8h.4M27.4 90.5a.75 .75 0 0 1 .3 1.2h-.4l-.1-.4 .1-.6zM27.7 98.2l-.1 .2a.43 .43 0 0 1-.5-.1 .43 .43 0 0 1 0-.6h.5l.1 .3-.2 .8-.4 .1M27.7 83.2h-.6v1.2h.6M28 83.2l.9 1.2M28.9 90.7h.7l-.4 .5h.3v.7l-.6-.1M28.9 83.2l-.9 1.2M29 86.3l.3-.4v1.2M29 88.4l.4-.1 .2 .3-.7 .9h.7M29 87.1h.6M29.2 93l-.2 .9h.7M29.3 83.8h.4l.2-.1v-.4l-.2-.1h-.4v1.2l.6-.1 .1-.3-.3-.2"/>
<path d="M29.5 95.5h-.5v.5h.5v.6l-.4 .1-.1-.2M29.5 97.9h-.3l-.2 .2v.9h.5l.1-.4a.35 .35 0 0 0-.3-.3 .35 .35 0 0 0-.3 .3M29.5 93.5v.7M30.5 83.3l.4-.1 .3 .4-.8 .8h.8M31.4 81.4h.6l.1-.4-.2-.1h-.5v1.1M31.7 83.8h.6M31.7 83.2v1.2M31.7 81.4l.4 .6M32.3 83.2v1.2M32.7 83.2l.4 1.2 .4-1.2M33.3 80.9v1.1l-.7-1.1v1.1M34.1 83.1l-.2 .9h.6"/>
<path d="M34.4 80.9h-.6v.5h.6l.1 .4-.3 .2-.4-.1M34.4 83.7v.7M34.6 87.5h7.8M34.6 89.8h7.8M34.6 92.2h7.8M34.6 94.6h7.8M34.6 96.9h7.8M34.6 99.4h7.8M34.9 83.2h.8l-.5 1.2M35.6 86.3l.3-.4v1.2M35.6 88.6l.3-.3v1.2M35.6 91l.3-.3v1.2"/>
<path d="M35.6 93.4l.3-.4v1.2M35.6 95.8l.3-.3v1.2M35.6 98.2l.3-.3v1.2M35.6 87.1h.6M35.6 89.5h.6M35.6 91.9h.6M35.6 94.2h.6M35.6 96.7h.6M35.6 99.1h.6M36.2 83.3l.3-.1a.64 .64 0 0 1 .4 .6 .64 .64 0 0 1-.5 .6l-.2-.2zM36.7 93h.6l-.3 .6h.3v.5h-.6M36.7 95.6h.6v.4l-.6 .7h.6"/>
<path d="M36.7 98.2l.3-.3v1.2M36.7 99.1h.6M37 90.7l-.3 .8h.7M37.3 85.9h-.3a.73 .73 0 0 0-.1 1.2l.4-.1v-.5l-.4-.1-.2 .2M37.3 91.1v.8M37.3 88.3h-.6v.6l.1-.2h.4l.1 .2v.5h-.6M37.7 83.2v.9l-.2 .2-.3 .1M37.8 99.7h3.3M38 83.2l.4 1.2 .5-1.2M39 96.5l.5-1.2 .4 1.2M39 98.9l.5-1.2 .4 1.2M39.2 85.8h.3l.4 .2v.7l-.4 .3h-.3z"/>
<path d="M39.2 88.1h.3l.4 .4v.6l-.2 .2h-.5zM39.2 90.5h.3l.4 .3v.6l-.2 .3h-.5zM39.2 93.6l.7-.1v-.5l-.2-.1h-.5v1.2M39.2 96.2h.5M39.2 98.6h.5M39.5 93.6l.4 .5M40.2 95.4l.5-.1 .2 .4-.8 .8h.8M40.2 98l.4-.3v1.2M40.2 98.9h.7M40.2 92.6h1.2M40.3 92.9l.3 1.2 .2-.8 .3 .8 .2-1.2M40.4 90.8l.3-.3v1.2"/>
<path d="M40.4 91.7h.7M40.6 86.3l-.2-.1v-.3h.6v.3l-.6 .2v.5l.2 .1h.2l.3-.3-.3-.4M41.1 88.6l-.3 .3-.4-.1v-.6l.4-.1 .3 .3-.2 .8-.4 .1M41.4 95.4l.1-.1a.59 .59 0 0 1 .5 .4 .59 .59 0 0 1-.1 .7l-.2 .1-.3-.1zM41.6 90.7l.1-.2a.75 .75 0 0 1 .3 1.2l-.4-.1zM41.6 86.4h.3M41.6 88.7h.3M41.7 93.5h.5M42 98.2l-.1 .2a.43 .43 0 0 1-.5-.1 .43 .43 0 0 1 0-.6h.5l.1 .3-.2 .8-.4 .1M42.1 85.8h-.5v1.2h.5M42.1 88.1h-.5v1.2h.5M42.3 92.9h-.6v1.2h.6"/>
<path d="M42.5 95.8h.4M42.5 98.3h.4M42.7 91.1h.4M43.1 95.3h-.6v1.2h.6M43.1 97.7h-.6v1.2h.6M43.3 90.5h-.6v1.2h.6M47.2 80.3h.1M47.2 80.3h9.5M48.3 87.5h8.4M48.3 89.8h8.4M48.3 92.2h8.4M48.3 94.6h8.4"/>
<path d="M48.3 96.9h8.4M48.3 99.4h8.4M48.3 82.6h8.4M48.3 85.1h8.4M48.6 89.3l.4-1.2 .4 1.2M48.6 87l.4-1.2 .4 1.2M48.6 94.1l.4-1.2 .4 1.2M48.6 98.9l.4-1.2 .4 1.2M48.6 96.5l.4-1.2 .4 1.2M48.6 91.7l.4-1.2 .4 1.2M48.6 82.2l.4-1.2 .4 1.2M48.6 84.6l.4-1.2 .4 1.2"/>
<path d="M48.7 96.2h.6M48.7 98.6h.6M48.7 89h.6M48.7 86.6h.6M48.7 93.8h.6M48.7 91.4h.6M48.7 81.9h.6M48.7 84.2h.6M49.7 88.1h.8l-.5 1.2M49.7 86.1l.3-.3v1.2M49.7 97.7h.7l-.4 .4 .4 .2v.5h-.7M49.7 81.4l.3-.4v1.2"/>
<path d="M49.7 83.7l.3-.3v1.2M49.7 87h.7M49.7 82.2h.7M49.7 84.6h.7M50 95.2l-.3 .9h.8M50.3 90.5l-.4 .2-.2 .8 .2 .2 .5-.1-.1-.6h-.4l-.2 .2M50.3 95.7v.8M50.4 92.9h-.6l-.1 .6h.7v.5l-.2 .1h-.3l-.2-.1M50.9 85.9l.4-.1 .3 .3-.8 .9h.8M50.9 88.7h.4M50.9 95.8h.4M50.9 93.5h.4"/>
<path d="M50.9 98.3h.4M50.9 91.1h.4M51.4 81h-.3l-.2 .3v.7l.4 .2 .3-.2v-.3l-.3-.3-.4 .1v.2M51.5 88.1h-.6v1.2h.6M51.5 92.9h-.6v1.2h.6M51.5 97.7h-.6v1.2h.6M51.5 95.3h-.6v1.2h.6M51.5 90.5h-.6v1.2h.6M51.5 83.4h-.6v.6l.4-.2 .3 .3-.1 .4h-.6M52.1 86.4h.4M52.1 81.5h.4M52.1 84h.4"/>
<path d="M52.7 85.8h-.6v1.2h.6M52.7 81h-.6v1.2h.6M52.7 83.4h-.6v1.2h.6M54.5 83.6h.8l-.4 .4 .3 .1v.6l-.5 .1-.2-.2M54.5 93h.9l-.5 1.2M54.6 81.3l.6-.1 .1 .3-.8 .9h.8M54.9 85.9l-.3 .8h.8M54.9 96l-.3-.2 .1-.3h.5v.4l-.5 .1-.1 .2v.2l.3 .3 .4-.3-.1-.4h-.2M55.2 88.3h-.5l-.1 .6 .2-.2 .4 .1v.6h-.6M55.2 90.7h-.3a.93 .93 0 0 0-.2 1.2h.5l.1-.5-.1-.2h-.5l-.1 .2M55.2 86.4v.7M55.3 98.4l-.1 .2h-.5l-.1-.2 .1-.5 .5 .1a.85 .85 0 0 1-.3 1.1h-.2"/>
<path d="M56.7 80.2h1.2v.2h-1.2zM56.7 82.5h1.2v.3h-1.2zM56.7 84.9h1.2v.3h-1.2zM56.7 87.3h1.2v.2h-1.2zM56.7 89.7h1.2v.2h-1.2zM56.7 92.1h1.2v.2h-1.2zM56.7 94.5h1.2v.2h-1.2zM56.7 96.9h1.2v.2h-1.2zM56.7 99.2h1.2v.3h-1.2zM60.3 80.2h1.2v.2h-1.2zM60.3 82.5h1.2v.3h-1.2zM60.3 84.9h1.2v.3h-1.2z"/>
<path d="M60.3 87.3h1.2v.2h-1.2zM60.3 89.7h1.2v.2h-1.2zM60.3 92.1h1.2v.2h-1.2zM60.3 94.5h1.2v.2h-1.2zM60.3 96.9h1.2v.2h-1.2zM60.3 99.2h1.2v.3h-1.2zM61.5 99.4h12.2l.3-1 .8 1.9 .6-1.9 .8 1.9 .7-1.9 .7 1.9 .4-.9h8.5M61.5 87.5h8.4M61.5 89.8h8.4M61.5 92.2h8.4M61.5 94.6h8.4M61.5 96.9h8.4"/>
<path d="M61.5 80.3h15.5M61.5 82.6h8.4M61.5 85.1h8.4M62.3 81.2h.8l-.4 .4 .3 .1 .1 .4-.3 .3h-.3l-.2-.2M62.3 83.6h.8l-.4 .4 .3 .1 .1 .4-.3 .3h-.3l-.2-.2M62.4 86l.4-.1 .3 .4-.8 .8h.8M62.4 88.4l.4-.1 .3 .3-.8 .9h.8M62.4 90.8l.4-.1 .3 .3-.8 .9h.8M62.4 93.2l.4-.2 .3 .4-.8 .8h.8M62.4 95.6l.5-.1 .2 .3-.8 .9h.8M62.4 98l.5-.1 .2 .3-.8 .9h.8M63.5 81.5l.3-.3v1.2"/>
<path d="M63.5 90.7h.8l-.5 1.2M63.5 82.4h.7M63.7 83.6h.3l.2 .1v.8l-.3 .3a.71 .71 0 0 1-.2-1.2zM63.8 88.8l-.3-.2 .3-.3 .4 .1v.3a.51 .51 0 0 0-.6 .7h.6v-.5l-.2-.1M63.8 97.8l-.3 .8h.8M64.1 93l-.4 .2-.2 .9 .2 .1 .5-.1-.1-.5h-.4l-.2 .1M64.1 98.2v.9M64.2 86.4l-.2 .3h-.2l-.3-.3 .1-.4h.6v.9l-.5 .2M64.2 95.5h-.6l-.1 .5h.7v.5l-.2 .2h-.3l-.2-.2M66.5 91.7l.4-1.2 .4 1.2M66.5 82.2l.4-1.2 .4 1.2M66.5 89.3l.4-1.2 .4 1.2"/>
<path d="M66.5 87l.4-1.2 .4 1.2M66.5 84.6l.4-1.2 .4 1.2M66.5 96.5l.4-1.2 .4 1.2M66.5 94.1l.4-1.2 .4 1.2M66.5 97.4h5.6M66.5 96.2h.6M66.5 89h.6M66.5 86.6h.6M66.5 93.8h.6M66.5 91.4h.6M66.5 81.9h.6M66.5 84.2h.6"/>
<path d="M67.3 97.8l-.5-.1a.61 .61 0 0 0-.2 .8 .61 .61 0 0 0 .7 .3M67.6 81.4l.4-.4v1.2M67.6 88.5l.4-.4v1.2M67.6 86.1l.4-.3v1.2M67.6 83.7l.4-.3v1.2M67.6 95.7l.4-.4v1.2M67.6 87h.7M67.6 82.2h.7M67.6 89.3h.7M67.6 84.6h.7M67.6 96.5h.7M67.8 91l-.2-.1v-.2l.5-.2 .2 .3-.7 .4 .1 .5h.5l.1-.2v-.2l-.2-.3"/>
<path d="M67.8 97.7v.9l.3 .3 .4-.1v-1.1M68.3 93.5l-.1 .1h-.5l-.1-.6 .5-.1 .2 .2-.1 .9-.5 .1M68.7 88.1h.7l-.4 .5h.3v.7l-.6-.1M68.7 83.4h.8l-.5 1.2M68.7 95.7l.4-.4v1.2M68.7 96.5h.7M68.8 93.5h.4M68.8 91.1h.4M69 81.5l-.3-.2 .1-.3h.5v.4l-.5 .1-.1 .2v.3l.3 .2 .4-.2-.1-.5h-.1M69 85.7l-.3 .8h.8M69.1 97.7h.4a.66 .66 0 0 1 .2 .8 .66 .66 0 0 1-.6 .4zM69.3 90.5h-.5v1.2h.5"/>
<path d="M69.3 92.9h-.5v1.2h.5M69.3 86.2v.8M69.9 86.4h.5M69.9 88.7h.5M69.9 95.8h.5M69.9 81.5h.5M69.9 84h.5M70.5 81h-.6v1.2h.6M70.5 88.1h-.6v1.2h.6M70.5 85.8h-.6v1.2h.6M70.5 83.4h-.6v1.2h.6M70.5 95.3h-.6v1.2h.6"/>
<path d="M70.9 97.7h-.5l-.2 .3 .2 .3 .5 .2v.3h-.7M71.5 98.3h.3M72 97.7h-.5v1.2h.5M74.5 97.3l-.2-.1 .2-.4h.3l.2 .2-.2 .3h-.3l-.2 .2 .1 .5h.4l.2-.2v-.3l-.2-.2M74.7 95.2h.6l.1-.5h-.7v1.1M75 95.2l.4 .6M75.4 96.9l.5-.1 .2 .3-.7 .9h.7M75.9 94.7h.4l.2 .3-.7 .8h.7M76.1 90.4l-.3-.1-.4 .4v.6l.2 .2h.5v-.5h-.2M76.6 97.5l.6-.1v-.5l-.6-.1v1.2M76.9 97.5l.4 .5M77 86.3v1.2h1.2l-1.2 1.1-1.2-1.1h1.2"/>
<path d="M77 86.3h.1M77 80.3h.1M77 83.1v3.2M77.3 90.3v1.2l-.7-1.2v1.2M77.9 90.3l.5 .1 .2 .3v.6l-.2 .2h-.5zM79.6 97.4h4.6M79.8 83.6l.3-.4v1.2M79.8 84.4h.6M80.4 97.8l-.5-.1a.61 .61 0 0 0-.2 .8 .61 .61 0 0 0 .7 .3M80.4 80.9h-.5l-.1 .2v.8l.3 .1 .3-.1M80.9 97.7v.9l.3 .3 .4-.1v-1.1M80.9 83.3l.4-.1a.78 .78 0 0 1 0 1.2l-.4-.1z"/>
<path d="M80.9 80.9h.5l.2 .3-.7 .8h.7M82.1 83.3l.3-.1 .2 .3v.7l-.3 .2a.7 .7 0 0 1-.2-1.1zM82.2 97.7h.4a.66 .66 0 0 1 .3 .8 .66 .66 0 0 1-.7 .4zM83.1 83.7h.6v.7M83.1 83.7v.7M84 97.7h-.5l-.2 .3 .3 .3 .4 .2v.3h-.7M84.2 83.8h.5M84.8 83.2h-.6v1.2M90.1 87.5h7.8M90.1 89.8h7.8M90.1 92.2h7.8M90.1 94.6h7.8"/>
<path d="M90.1 96.9h7.8M90.1 80.3h7.8M90.1 82.6h7.8M90.1 85.1h7.8M90.3 87l.5-1.2 .3 1.2M90.3 82.2l.5-1.2 .3 1.2M90.3 84.6l.5-1.2 .3 1.2M90.3 89.3l.5-1.2 .3 1.2M90.3 91.7l.5-1.2 .3 1.2M90.3 94.1l.5-1.2 .3 1.2M90.3 96.5l.5-1.2 .3 1.2M90.4 96.2h.6"/>
<path d="M90.4 89h.6M90.4 86.6h.6M90.4 93.8h.6M90.4 91.4h.6M90.4 81.9h.6M90.4 84.2h.6M91.4 86.1l.4-.3v1.2M91.4 81.4l.4-.4v1.2M91.4 83.7l.4-.3v1.2M91.4 93.3l.4-.4v1.2M91.4 95.7l.4-.4v1.2M91.4 87h.7"/>
<path d="M91.4 82.2h.7M91.4 84.6h.7M91.4 96.5h.7M91.4 94.1h.7M91.7 88.6l-.3-.1 .1-.3h.6l-.1 .4h-.3l-.3 .3 .2 .4 .5-.1v-.4l-.2-.2M92.1 91v.2l-.4 .1-.2-.1-.1-.4 .3-.3 .4 .2v.7l-.2 .3h-.3M92.5 85.8h.8l-.4 .4 .4 .2-.1 .5h-.7M92.5 81h.8l-.5 1.2M92.6 93.3l.4-.4v1.2M92.6 95.5l.2-.2a.6 .6 0 0 1 .6 .5 .6 .6 0 0 1-.3 .6l-.2 .1-.3-.2zM92.6 88.7h.4M92.6 91.1h.4"/>
<path d="M92.6 94.1h.7M92.9 83.3l-.3 .9h.7M93.1 83.8v.8M93.2 88.1h-.6v1.2h.6M93.2 90.5h-.6v1.2h.6M93.8 86.4h.3M93.8 95.8h.3M93.8 93.5h.3M93.8 81.5h.3M93.8 84h.3M94.3 85.8h-.5v1.2h.5M94.3 81h-.5v1.2h.5"/>
<path d="M94.3 83.4h-.5v1.2h.5M94.3 92.9h-.5v1.2h.5M94.3 95.3h-.5v1.2h.5M95.7 83.6h.7l-.4 .4 .4 .1v.4l-.2 .3h-.4l-.1-.2M95.7 93h.7l-.5 1.2M95.8 81.3l.5-.1 .1 .3-.7 .9h.7M95.9 96l-.1-.2v-.3h.5l.1 .2-.2 .3-.4 .1v.4l.1 .2h.3l.2-.3v-.2l-.2-.2M96 85.9l-.2 .8h.6M96.3 90.7l-.4 .1-.1 .2v.8l.5 .1 .1-.2v-.3l-.1-.2h-.5v.2M96.3 86.4v.7M96.4 88.3h-.6v.6l.4-.2 .2 .3v.4h-.6M100 99.9v1.2l-.7-1.2v1.2"/>
<path d="M100.8 99.8l-.3 .9h.8M101.4 87.5h7.8M101.4 89.8h7.8M101.4 92.2h7.8M101.4 94.6h7.8M101.4 96.9h7.8M101.4 80.3h7.8M101.4 82.6h7.8M101.4 85.1h7.8M102.4 81.5l.3-.3v1.2M102.4 83.9l.3-.3v1.2M102.4 86.3l.3-.4v1.2"/>
<path d="M102.4 88.6l.3-.3v1.2M102.4 91l.3-.3v1.2M102.4 93.4l.3-.4v1.2M102.4 87.1h.6M102.4 89.5h.6M102.4 91.9h.6M102.4 94.2h.6M102.4 82.4h.6M102.4 84.8h.6M103.4 85.9h.7l-.4 .5h.4v.6h-.7M103.5 88.4l.4-.1 .2 .3-.7 .9h.7M103.5 91l.3-.3v1.2"/>
<path d="M103.5 91.9h.6M103.5 96v.2h-.5l-.1-.2v-.3l.1-.2 .5 .1v.8l-.1 .2-.4 .1M103.7 83.5l-.2 .8h.7M103.7 93a.75 .75 0 0 1 .3 1.2h-.4l-.1-.4v-.6zM104.1 81.2h-.6v.5h.6v.6l-.5 .1-.1-.2M104.1 83.9v.9M105.8 89.3l.5-1.2 .3 1.2M105.8 82.2l.5-1.2 .3 1.2M105.8 87l.5-1.2 .3 1.2M105.8 84.6l.5-1.2 .3 1.2M105.8 96.5l.5-1.2 .3 1.2M105.8 91.7l.5-1.2 .3 1.2"/>
<path d="M105.8 94.1l.5-1.2 .3 1.2M105.9 96.2h.6M105.9 89h.6M105.9 86.6h.6M105.9 93.8h.6M105.9 91.4h.6M105.9 81.9h.6M105.9 84.2h.6M106.9 81.4l.4-.4v1.2M106.9 86.1l.4-.3v1.2M106.9 83.7l.4-.3v1.2M106.9 95.7l.4-.4v1.2"/>
<path d="M106.9 93.3l.4-.4v1.2M106.9 87h.7M106.9 82.2h.7M106.9 84.6h.7M106.9 96.5h.7M106.9 94.1h.7M107.2 88.6l-.3-.1 .1-.3h.6l-.1 .4h-.3l-.3 .3 .2 .4 .5-.1v-.4l-.2-.2M107.6 91v.2l-.4 .1-.2-.1-.1-.4 .3-.3 .4 .2v.7l-.2 .3h-.3M108 81h.8l-.5 1.2M108 85.8h.8l-.4 .4 .4 .2-.1 .5h-.7M108.1 95.5l.2-.2a.6 .6 0 0 1 .6 .5 .6 .6 0 0 1-.3 .6l-.2 .1-.3-.2zM108.1 93.3l.4-.4v1.2"/>
<path d="M108.1 94.1h.7M108.4 83.3l-.3 .9h.7M108.6 83.8v.8M117.5 89.8h6M117.5 85.1h6M119.9 99.4h10.1M120.8 88.6l.4-.3v1.2M120.8 89.5h.7M121.3 97.4h4.3M122.1 84.1l-.2 .1h-.4l-.1-.5 .5-.1 .2 .1-.2 .9-.4 .2M122.1 88.4l.2-.1 .3 .3v.6l-.3 .3a.7 .7 0 0 1-.2-1.1zM122.2 97.8l-.5-.1a.61 .61 0 0 0-.3 .8 .61 .61 0 0 0 .8 .3"/>
<path d="M122.7 97.7v1.2h.6M123.7 97.7h.4a.66 .66 0 0 1 .3 .8 .66 .66 0 0 1-.7 .4zM123.8 80.9h.7l-.5 1.1M125.2 80.8l-.2 .8h.6M125.5 97.7h-.6a.47 .47 0 0 0 0 .5 .47 .47 0 0 0 .5 .2v.4h-.6M125.5 81.2v.8M126.2 80.9v1.1M126.2 81.4h.6M126.8 80.9v1.1M127 98.2l.3-.3v1.2M127 99.1h.7M128.1 80.9h-.5a.67 .67 0 0 0-.3 .6 .67 .67 0 0 0 .5 .5l.3-.1"/>
<path d="M128.2 98l.5-.1 .2 .3-.8 .9h.8M128.6 80.9h.1a.59 .59 0 0 1 .5 .3 .59 .59 0 0 1-.1 .7l-.2 .1-.3-.1zM129.7 95.2h.9l-.6 1.2M129.8 80.9h.3l.2 .1v.8l-.3 .2a.71 .71 0 0 1-.2-1.1zM131.2 95.1l-.3 .8h.8M131.5 95.5v.9M131.6 92.8v1l.1 .2h.3l.2-.3v-.9M131.8 87.5h10.1M131.8 82.6h10.1M132.1 95.2v1.2M132.1 95.7h.7M132.3 86.4l-.2-.2 .2-.3 .5 .1v.4a.51 .51 0 0 0-.6 .6h.6v-.5l-.2-.1"/>
<path d="M132.8 95.2v1.2M133.3 92.8h-.4l-.1 .2v.8l.4 .2 .2-.3v-.4l-.2-.1-.4 .1v.2M133.3 80.7h3.2M133.9 92.8h.5a.66 .66 0 0 1 .2 .7 .66 .66 0 0 1-.7 .5zM134 95.2h-.5a.67 .67 0 0 0-.2 .6 .67 .67 0 0 0 .5 .6l.2-.2M134.1 81.1l-.5-.1a.67 .67 0 0 0-.3 .7 .67 .67 0 0 0 .6 .5l.2-.2M134.5 95.2h.7l-.4 .4 .3 .1 .1 .4-.2 .3h-.4l-.1-.2M135.2 81h-.5l-.2 .2 .2 .3 .5 .2v.3l-.2 .2-.5-.1M135.6 95.2h.6l.1 .3-.7 .9h.7M135.7 81.2l.2-.2a.6 .6 0 0 1 .6 .5 .6 .6 0 0 1-.3 .6l-.2 .1-.3-.2zM137.8 93.4h11.2M137.8 98.2h11.2"/>
<path d="M139.2 97.7l.4-1.2 .4 1.2M139.2 92.9l.4-1.2 .4 1.2M139.4 97.4h.5M139.4 92.5h.5M139.8 81.1l-.3 .9h.7M140 81.5v.9M140.1 85.9h-.6v.6l.5-.1 .2 .2-.1 .4h-.6M140.4 96.9l.3-.4v1.2M140.4 91.9l.4-.2 .3 .3-.8 .9h.8M140.4 97.7h.7M141.6 99.7h2.1M141.7 91.7a.75 .75 0 0 1 .3 1.2h-.4l-.1-.4 .1-.6z"/>
<path d="M142.2 97l-.1 .2h-.5l-.1-.2 .1-.5 .5 .1a.85 .85 0 0 1-.3 1.1h-.2M146.6 92.2l.4-.3v1.1M146.6 96.8l.6-.1 .1 .5-.7 .7h.7M146.6 93h.7M147.6 81.3h.8l-.5 1.2M148.5 85.1h7.2v4.7h25.7M148.8 89.2v1l.1 .1h.5v-1.1M148.9 86.3v1l.3 .2 .4-.1v-1.1M149.1 81.3l-.3 .8h.7M149.4 81.7v.8M150 81.9h.7M150 81.3v1.2"/>
<path d="M150.5 83.6h-.3l-.2 .2v.8l.5 .2 .2-.3-.1-.4-.1-.1-.5 .1v.1M150.5 89.2h-.3l-.2 .3v.8h.5l.2-.1v-.4l-.2-.1h-.4l-.1 .1M150.7 86.3l-.4 .1-.2 .9 .3 .2 .4-.1-.1-.6h-.4l-.2 .2M150.7 81.3v1.2M151 90.3l.4-1.1 .4 1.1M151.1 90h.6M151.3 86.9l.6-.1 .1-.3-.3-.2h-.4v1.2h.5l.2-.1v-.4l-.3-.1M151.9 81.4l-.3-.1-.4 .3v.6l.2 .3 .5-.1M152.3 81.3h.8l-.4 .5 .4 .2v.3l-.2 .2-.6-.1M153.5 81.4l.2-.1h.3l.2 .1v.4l-.8 .7h.8M157.1 94.2h.7l-.4 .5 .4 .3-.1 .4-.5 .1-.1-.2M177.4 86.2h.3"/>
<path d="M177.9 85.6h-.5v1.2h.5M178.3 85.6l.8 1.2M179.1 85.6l-.8 1.2M179.2 93h.7l-.4 .6 .4 .1v.4l-.2 .1-.5-.1M179.2 88.6l.4-.3v1.2M179.2 90.8l.5-.1 .2 .3-.7 .9h.7M179.2 89.5h.7M179.5 95.4l-.3 .9h.7M179.6 86.2l.5-.1v-.4l-.5-.1v1.2h.4l.3-.4-.4-.2M179.7 95.8v.9M180.7 85.7l.4-.1 .3 .3-.8 .9h.8M181.4 94.6h-17.3v11.9h-52.5v22.7h-21.5"/>
<path d="M181.4 92.2h-19.8v3.6h-5.9M181.4 96.9h-13.8v12h-53.6v33.4h-3.6M181.6 83.8h.6l.1-.5-.7-.1v1.2M181.9 83.8l.4 .6M182 86.1l-.2-.2 .2-.3 .5 .1v.3a.51 .51 0 0 0-.6 .7h.6v-.3l-.2-.3M182.9 85.6l.3 1.2 .4-1.2M183.5 83.2v1.2l-.7-1.2v1.2M184.2 85.5l-.2 .9h.7M184.6 83.2h-.3a.73 .73 0 0 0-.1 1.2l.5-.1v-.5l-.5-.1-.2 .2M184.6 86v.8M184.9 96.9h16.1M185.1 85.6h.7l-.5 1.2"/>
<path d="M186.3 90.7h.8l-.5 1.2M186.4 85.7l.2-.1a.64 .64 0 0 1 .4 .6 .64 .64 0 0 1-.5 .6l-.2-.3zM186.6 88.8l-.2-.2v-.2h.6v.3l-.4 .1a.35 .35 0 0 0-.3 .4 .35 .35 0 0 0 .3 .3l.4-.1v-.5l-.1-.1M186.9 93h-.2a.93 .93 0 0 0-.3 1.2l.6-.1v-.5h-.6v.1M187 95.5h-.6v.5h.6v.5l-.1 .2h-.4l-.1-.2M187.8 85.6v.8l-.4 .4M188.2 85.6l.9 1.2M189.1 85.6l-.9 1.2M192.7 82.6v12h-7.8M195.4 95.9l.7-.1v-.4l-.7-.1v1.2M195.7 95.9l.4 .6M196.5 95.3l.3 1.2 .2-.8 .3 .8 .2-1.2"/>
<path d="M198 95.5l.1-.2h.4a.86 .86 0 0 1 0 1.2l-.5-.1zM199.2 95.8h.4M199.8 95.3h-.6v1.2h.6M204.6 92.2h9.5M204.6 94.6h9.5M204.6 99.4h8.3M204.8 94.1l.4-1.2 .4 1.2M204.8 97.4h4.2M204.9 93.8h.6M205 91.2l.6-.1v-.5l-.6-.1v1.2M205.2 91.2l.5 .5M205.7 97.8l-.6-.1a.61 .61 0 0 0-.2 .8 .61 .61 0 0 0 .8 .3"/>
<path d="M206 90.2h1.1M206.1 93l.2-.1 .3 .2v.8l-.3 .2a.71 .71 0 0 1-.2-1.1zM206.1 90.5l.2 1.2 .3-.9 .2 .9 .3-1.2M206.2 97.7v1.2h.6M207.1 97.7h.5l.2 .3v.6l-.4 .3h-.3zM209 97.7l-.7 .1v.3l.7 .5-.3 .3-.4-.1M211.3 90.7h.8l-.4 .5h.3l.1 .2-.1 .5-.7-.1M211.4 93.2l.4-.2 .3 .4-.8 .8h.8M211.4 98.2l.4-.3v1.2M211.4 99.1h.7M215.5 92.8l.3-1.3 .4 1.3M215.5 95.2l.3-1.2 .4 1.2"/>
<path d="M215.6 92.4h.6M215.6 94.8h.6M215.6 99.3h.4M216.2 98.7h-.6v1.2h.6M216.6 91.9l.3-.4v1.3M216.6 92.8h.7M216.7 94.1v-.1a.59 .59 0 0 1 .6 .3 .59 .59 0 0 1-.1 .7l-.2 .2-.3-.2zM217.4 86.8h.8l-.5 1.2M218.9 86.7l-.3 .8h.7M219.1 87.2v.8M219.3 84.4v.9a.42 .42 0 0 0 .7 .2v-1.1M219.8 87.4h.7"/>
<path d="M219.8 86.8v1.2M220.5 84.8l.3-.4v1.2M220.5 86.8v1.2M220.5 85.6h.6M221.7 84.8l.3-.4v1.2M221.7 85.6h.6M221.7 86.9l-.2-.1a.67 .67 0 0 0-.5 .5 .67 .67 0 0 0 .2 .7l.5-.1M222.2 87.1l.3-.3v1.2M222.2 88h.6M222.7 85.6l.3-1.2 .4 1.2M222.8 85.3h.6M223.3 86.8h.6l-.3 .4 .3 .2v.5h-.6"/>
<path d="M225.1 91.7l.5-.2a.86 .86 0 0 1 0 1.3l-.5-.2zM225.1 94.1l.2-.1h.4a.86 .86 0 0 1-.1 1.2l-.5-.2zM225.1 96.5l.2-.1h.4a.86 .86 0 0 1-.1 1.1l-.5-.1zM225.1 98.9l.5-.2a.65 .65 0 0 1 .3 .7 .65 .65 0 0 1-.5 .5l-.3-.2zM225.1 87.3l-.2 .2h-.4v-.6a.36 .36 0 0 1 .6 .1l-.1 .9-.5 .1M226.3 94.3l.4-.3v1.2M226.3 96.4h.7v.5l-.7 .6h.7M226.3 98.7h.7l-.3 .4 .3 .2v.5h-.7M226.3 95.2h.7M226.5 91.6l.2-.1 .3 .3v.7l-.3 .3a.71 .71 0 0 1-.2-1.2zM229.6 92.2h8.4M229.6 94.6h8.4"/>
<path d="M229.6 96.9h8.4M229.6 99.4h8.4M230.5 97.9h.7l-.5 1.2M230.8 90.7l-.3 .8h.7M231.1 95.5l-.5 .1a.82 .82 0 0 0 .1 1.1l.4-.2v-.5l-.4-.1-.2 .3M231.1 91.1v.8M231.1 93h-.6v.6h.6v.5h-.6M233.4 97.4h3.2M233.4 92.6h3.3M233.4 95h3.2M233.4 90.2h3.3M233.5 92.9l.3 1.2 .2-.8 .2 .8 .3-1.2"/>
<path d="M233.5 90.5l.3 1.2 .2-.9 .2 .9 .3-1.2M233.7 97.7h.5l.2 .4-.1 .6-.3 .2-.3-.1-.2-.3zM233.7 95.3h.5a.77 .77 0 0 1-.2 1.2l-.3-.1a.87 .87 0 0 1 0-1.1zM234.9 95.8h.3M234.9 98.3h.3M235 93.5h.4M235 91.1h.4M235.4 97.7h-.5v1.2h.5M235.4 95.3h-.5v1.2h.5M235.5 92.9h-.5v1.2h.5M235.5 90.5h-.5v1.2h.5M235.9 97.8l.5-.1 .2 .3-.8 .9h.8"/>
<path d="M235.9 95.7l.3-.4v1.2M235.9 96.5h.7M236 93l.4-.1 .2 .4-.7 .8h.7M236 90.8l.3-.3v1.2M236 91.7h.6M241.6 92.2h9.5M241.6 94.6h9.5M241.6 99.4h8.3M241.7 94.1l.4-1.2 .5 1.2M241.8 97.4h4.5M241.9 91.2h.5l.3-.4-.3-.3h-.5v1.2M241.9 93.8h.6"/>
<path d="M242.2 91.2l.5 .5M242.7 97.8l-.6-.1-.2 .3v.6l.4 .3 .4-.1M243 90.5l.3 1.2 .2-.9 .3 .9 .2-1.2M243 90.2h1.1M243.2 92.9a.68 .68 0 0 1 .4 .6 .68 .68 0 0 1-.4 .6l-.3-.5 .1-.6zM243.2 97.7v1.1l.1 .1h.3l.2-.3v-.9M244.3 97.7h.6l.1 .3v.6l-.3 .3h-.4zM246.2 97.7l-.7 .1v.3l.7 .5-.2 .3-.5-.1M247.8 91l.4-.3v1.2M247.8 93.4l.4-.4v1.2M247.8 98.2l.4-.3v1.2M247.8 91.9h.7"/>
<path d="M247.8 94.2h.7M247.8 99.1h.7M248.9 90.7h.7l-.3 .5 .3 .1v.5h-.7M249.3 93l-.4 .9h.8M249.5 93.5v.7M249.6 97.9h-.6l-.1 .5h.7v.5l-.2 .2h-.3l-.2-.2M252.4 92.8l.4-1.3 .4 1.3M252.4 95.2l.4-1.2 .4 1.2M252.5 92.4h.6M252.5 94.8h.6M252.6 99.3h.4M253.2 98.7h-.6v1.2h.6"/>
<path d="M253.6 91.9l.3-.4v1.3M253.6 94.1l.1-.1a.6 .6 0 0 1 .6 .4 .6 .6 0 0 1-.2 .7l-.3 .1-.2-.3zM253.6 92.8h.7M254.3 86.8h.9l-.5 1.2M255.4 84.9v1l.3 .2 .4-.2v-1M255.9 86.7l-.4 .8h.8M256.1 87.2v.8M256.6 85.3l.4-.4v1.2M256.6 86.1h.7M256.7 86.8v1.2M256.7 87.4h.7M257.4 86.8v1.2"/>
<path d="M257.8 85.3l.3-.4v1.2M257.8 86.1h.7M258.7 86.9a.45 .45 0 0 0-.7 .1v.7l.1 .3 .6-.1M259 85.4h.5l.1-.4-.6-.1v1.2l.6-.1 .1-.3-.3-.3M259.2 87.1l.3-.3v1.2M259.2 88h.6M260.2 86.8h.7l-.4 .4 .4 .3v.5l-.7-.1M262 87.3l-.1 .2h-.3l-.2-.2 .1-.4h.5v.8l-.1 .3h-.4M262.1 98.9l.2-.2a.46 .46 0 0 1 .6 .4v.4a.46 .46 0 0 1-.6 .4 .82 .82 0 0 1-.2-1zM262.3 91.5a.46 .46 0 0 1 .6 .4v.5a.46 .46 0 0 1-.6 .4 .86 .86 0 0 1 0-1.3zM263.2 98.7h.8l-.4 .4 .3 .1v.6h-.7M263.3 94.3l.4-.3v1.2"/>
<path d="M263.3 96.4h.6l.1 .3-.8 .8h.8M263.3 95.2h.7M263.6 91.5a.68 .68 0 0 1 .4 .7 .68 .68 0 0 1-.4 .6l-.3-.5 .1-.6zM266.6 92.2h8.3M266.6 94.6h8.3M266.6 96.9h8.3M266.6 99.4h8.3M266.9 91l.3-.3v1.2M266.9 93.4l.3-.4v1.2M266.9 95.8l.3-.3v1.2M266.9 91.9h.6M266.9 94.2h.6"/>
<path d="M266.9 96.7h.6M268.1 90.8l.4-.1 .2 .3-.7 .9h.7M268.1 93.4l.3-.4v1.2M268.1 95.7l.1-.2a.6 .6 0 0 1 .6 .4 .6 .6 0 0 1-.2 .7l-.3 .1-.2-.3zM268.1 94.2h.6M268.1 98.4v.2h-.6v-.2v-.5l.6 .1a.85 .85 0 0 1-.3 1.1h-.3M270.4 92.9l.4 1.2 .1-.8 .3 .8 .2-1.2M270.4 90.5l.4 1.2 .1-.9 .3 .9 .2-1.2M270.4 97.4h3.2M270.4 92.6h3.3M270.4 95h3.2M270.4 90.2h3.3"/>
<path d="M270.5 97.9l.2-.2h.4l.2 .2v.8l-.3 .2-.5-.2zM270.7 95.3h.4l.2 .2v.9l-.3 .1-.5-.1v-.9zM271.8 95.8h.4M271.8 98.3h.4M271.9 93.5h.4M271.9 91.1h.4M272.4 95.3h-.6v1.2h.6M272.4 97.7h-.6v1.2h.6M272.5 92.9h-.6v1.2h.6M272.5 90.5h-.6v1.2h.6M272.8 95.3h.7l-.4 .5h.4v.6l-.2 .1h-.3l-.2-.1M272.9 90.5h.7l-.4 .5 .4 .2v.3l-.1 .2-.6-.1"/>
<path d="M273.1 97.6l-.3 .9h.8M273.2 92.9l-.2 .8h.6M273.4 98.1v.8M273.5 93.3v.8M277.3 86.1l.5-.1v-.4l-.5-.1v1.2h.5l.2-.4-.4-.2M18.5 109.6h1.8M23.4 101.8h7.7M23.4 104.1h7.7M23.5 102.1h4.4M24.4 102.5h-.7v.5l.5 .1 .2 .4-.2 .1h-.6M24.4 100.2a.55 .55 0 0 0-.8 .5 .55 .55 0 0 0 .8 .5M24.8 117.9l-.1-.1a.66 .66 0 0 0-.6 .4 .66 .66 0 0 0 .3 .8l.5-.1v-.5h-.3"/>
<path d="M25.5 102.5h-.6v.5l.5 .1 .1 .4-.1 .1h-.6M25.6 100.2h-.7v.3l.7 .4-.3 .4-.4-.1M25.7 113.7v1.2h1.2l-1.2 1.2-1.1-1.2h1.1M25.7 113.7h.1M25.7 111.3v2.4M26.1 100.2l.3-.1a.78 .78 0 0 1 0 1.2l-.3-.1zM26.1 117.8v1.2l-.7-1.2v1.2M26.7 102.5l-.3-.1a.67 .67 0 0 0-.5 .6 .67 .67 0 0 0 .3 .6l.5-.1M26.7 117.8a.66 .66 0 0 1 .6 .4 .66 .66 0 0 1-.2 .8h-.4zM27.8 102.5h-.6a.57 .57 0 0 0 .6 .7l-.1 .4h-.6M28.5 111.8v-1.1l.4 .8 .4-.8v1.1M28.5 108.3v1.2"/>
<path d="M28.5 108.8h.7M28.9 100.2h.8l-.5 1.2M29.2 103.1l-.2-.2a.35 .35 0 0 1 .3-.3 .35 .35 0 0 1 .3 .3l-.2 .2a.36 .36 0 0 0-.4 .4 .36 .36 0 0 0 .5 .3 .36 .36 0 0 0 0-.6l-.1-.1M29.2 108.3v1.2M29.6 108.3h.8l-.4 .4 .3 .1 .1 .4-.3 .3h-.3l-.2-.2M29.9 111.1l.3-.1 .2 .2v.6h-.5zM30.7 115.4v.8l-.1 .4h-.4M30.9 111v.7l.2 .1h.3M31.4 111v.8M31.8 115.4h-.6v.6l.5-.2 .2 .3v.3l-.1 .2-.6-.1M32 111.2l.2-.2 .3 .1v.7M32 111v.8"/>
<path d="M32.9 111h.5M33.1 119.6h.2l.1-.3v1.2M33.1 110.7v1l.3 .1M33.8 110.7h.1M33.8 111v.8M34.4 111.2l.1-.2 .4 .2v.6M34.4 111v.8M34.6 101.8h7.8M34.6 104.1h7.8M35.6 100.6l.3-.4v1.2M35.6 101.4h.6M35.9 111v1.1l-.2 .2-.3-.1"/>
<path d="M35.9 111.1l-.3-.1-.2 .2v.6h.5M36.5 110.7v1.1M36.5 111.2h.7M36.8 100.3l.3-.1 .2 .3v.7l-.3 .2a.7 .7 0 0 1-.2-1.1zM36.8 103.1l-.2 .3-.4-.2v-.5l.4-.1a.73 .73 0 0 1-.1 1.2h-.3M36.8 119.9h1M37.2 110.7v1.1M37.3 119.5v.8M37.7 111.3l.4-.3 .3 .3-.1 .5h-.5zM38.4 119.7l.5-.1v-.4l-.5-.1v1.2h.5l.1-.3-.3-.3M38.7 100.2a.55 .55 0 0 0-.8 .5 .55 .55 0 0 0 .8 .5M38.9 110.7v1.1h.1"/>
<path d="M39 102.1h3.2M39.4 111.4l.6-.1-.2-.3-.4 .2v.5l.1 .1h.4M39.5 120h.5M39.9 102.5h-.7v.5l.7 .3-.2 .3h-.5M39.9 100.2h-.7v.3l.7 .4-.3 .4-.4-.1M40.2 111.9h.9M40.4 100.2l.3-.1a.78 .78 0 0 1 0 1.2l-.3-.1zM40.4 119.1h.7M40.7 119.1v1.2M41.1 102.5l-.3-.1a.67 .67 0 0 0-.5 .6 .67 .67 0 0 0 .3 .6l.5-.1M41.2 119.1h.7M41.4 111.3l.6-.1v-.5h-.6v1.1"/>
<path d="M41.5 100.7h.4M41.6 119.1v1.2M42.1 100.1h-.6v1.2h.6M42.2 102.5h-.6v.5l.5 .1 .1 .4-.1 .1h-.6M42.6 111.1l.3-.1 .2 .2v.6M43.1 111.3h-.4l-.2 .2 .2 .3h.4M43.3 119.1v1.2M44.2 111.1h-.5l-.1 .5a.36 .36 0 0 0 .6 .2M44.2 110.7v1.1M44.5 119.1v1.2l-.6-1.2v1.2M48.3 116.1v1.2h1.3l-1.3 1.1-1.1-1.1h1.1M48.3 116.1h.1"/>
<path d="M48.3 111.3h8.4M48.3 101.8h8.4M48.3 104.1h8.4M48.3 106.5h8.4M48.3 108.9h8.4M48.3 113.7h8.4M48.3 116.1h8.4M48.6 106l.4-1.2 .4 1.2M48.6 103.6l.4-1.2 .4 1.2M48.6 101.3l.4-1.2 .4 1.2M48.7 105.7h.6M48.7 103.3h.6"/>
<path d="M48.7 100.9h.6M48.8 107.2a.64 .64 0 0 1 .6 .6 .64 .64 0 0 1-.6 .7zM48.8 109.6h.4a.66 .66 0 0 1 .2 .8 .66 .66 0 0 1-.6 .4zM48.8 112h.4a.66 .66 0 0 1 .2 .8 .66 .66 0 0 1-.6 .4zM49.7 102.8h.2l.1-.4v1.2M49.7 100.2h.7v.4l-.7 .7h.7M49.7 103.6h.7M49.9 104.9l.2-.1 .3 .3v.7l-.2 .2h-.3l-.2-.4zM49.9 112.4l.3-.4v1.2M49.9 113.2h.6M50.1 107.8l-.2-.4 .2-.2h.3l.1 .4-.6 .3v.3l.2 .3 .4-.2v-.4l-.1-.1M50.5 110.2v.1h-.5l-.1-.1v-.4l.1-.2 .5 .1v.8l-.1 .2-.4 .1"/>
<path d="M50.9 105.4h.4M50.9 103h.4M50.9 100.7h.4M51.1 117.9l-.1-.1a.66 .66 0 0 0-.6 .4 .66 .66 0 0 0 .2 .8l.5-.1v-.5h-.2M51.1 110.2h.4M51.1 107.8h.4M51.1 112.1l.5-.1a.72 .72 0 0 1-.3 1.2l-.2-.3zM51.5 104.8h-.6v1.2h.6M51.5 102.4h-.6v1.2h.6M51.5 100.1h-.6v1.2h.6M51.6 107.2h-.5v1.3h.5M51.6 109.6h-.5v1.2h.5"/>
<path d="M52.2 112.6h.5M52.3 117.8v1.2l-.7-1.2v1.2M52.8 112h-.6v1.2h.6M52.8 117.8l.5 .1 .2 .2v.6l-.2 .3h-.5zM54 100.6l.4-.4v1.2M54 103l.4-.4v1.2M54 105.3h.2l.2-.3v1.2M54 107.7h.2l.2-.3v1.1M54 110.2l.4-.4v1.2M54 112.5l.4-.3v1.2M54 114.9l.4-.3v1.1M54 101.4h.7"/>
<path d="M54 103.8h.7M54 106.2h.7M54 108.5h.7M54 111h.7M54 113.4h.7M54 115.7h.7M55.1 107.4h.8l-.4 .5 .4 .1v.4l-.2 .1h-.6M55.2 103l.3-.4v1.2M55.2 105.2l.4-.2 .3 .3-.8 .9h.8M55.2 103.8h.7M55.3 100.3l.2-.1a.64 .64 0 0 1 .4 .7 .64 .64 0 0 1-.4 .5l-.3-.2zM55.5 109.7l-.3 .9h.7"/>
<path d="M55.7 114.6l-.5 .2v.9h.6l.1-.5-.3-.2h-.2l-.2 .2M55.7 110.2v.8M55.8 112.2h-.6v.5h.6l.1 .4-.3 .3-.4-.2M56 118.9h.3M56.5 118.3h-.5v1.2M56.7 101.6h1.2v.3h-1.2zM56.7 104.1h1.2v.1h-1.2zM56.7 106.4h1.2v.2h-1.2zM56.7 108.8h1.2v.3h-1.2zM56.7 111.2h1.2v.2h-1.2zM56.7 113.5h1.2v.3h-1.2zM56.7 115.9h1.2v.3h-1.2z"/>
<path d="M56.9 118.6l.3-.3v1.2M56.9 119.5h.7M60.3 101.6h1.2v.3h-1.2zM60.3 104.1h1.2v.1h-1.2zM60.3 106.4h1.2v.2h-1.2zM60.3 108.8h1.2v.3h-1.2zM60.3 111.2h1.2v.2h-1.2zM60.3 113.5h1.2v.3h-1.2zM60.3 115.9h1.2v.3h-1.2zM61.5 111.3h8.4M61.5 101.8h8.4M61.5 104.1h15.5"/>
<path d="M61.5 106.5h8.4M61.5 108.9h8.4M61.5 113.7h8.4M61.5 116.1h8.4M61.9 119.9h.9M62.3 119.5v.8M62.4 100.3l.4-.1 .3 .4-.8 .8h.8M62.4 102.7l.4-.1 .3 .4-.8 .8h.8M62.4 105.2l.4-.2 .3 .3-.8 .9h.8M62.4 107.5l.4-.1 .3 .3-.8 .8h.8M62.4 110.2l.3-.4v1.2M62.4 112.5l.3-.3v1.2"/>
<path d="M62.4 114.9l.3-.3v1.1M62.4 111h.7M62.4 113.4h.7M62.4 115.7h.7M63.3 119.7l.6-.1 .1-.2-.2-.3h-.5v1.2h.6l.1-.5-.2-.1M63.5 100.2h.7l-.4 .5 .4 .1v.5h-.7M63.5 102.7h.7v.4l-.7 .7h.7M63.5 105.3h.2l.1-.3v1.2M63.5 114.6h.8l-.5 1.1M63.5 106.2h.7M63.7 107.4h.2l.3 .2v.8l-.2 .1h-.3l-.2-.4zM63.8 112.7l-.3-.3 .2-.2h.4l.1 .3-.7 .4v.2l.3 .3 .4-.2v-.4l-.2-.1"/>
<path d="M64.2 110.3l-.1 .2h-.4l-.2-.2v-.3l.2-.2 .5 .1v.8l-.2 .2-.3 .1M64.5 120h.5M65.4 119.1h.6M65.7 119.1v1.2M66.3 119.1h.7M66.5 101.3l.4-1.2 .4 1.2M66.5 100.9h.6M66.6 114.4h.4l.3 .2v.7l-.3 .3h-.4zM66.6 112h.5l.2 .3v.6l-.3 .3h-.4zM66.6 104.8h.4l.3 .4v.5l-.2 .3h-.5zM66.6 109.6h.5l.2 .3v.6l-.3 .3h-.4zM66.6 107.2h.4l.3 .3v.6l-.3 .4h-.4z"/>
<path d="M66.6 119.1v1.2M67.6 100.4l.4-.3v1.2M67.6 101.3h.7M67.8 114.7l.4-.3v1.2M67.8 112.4l.4-.4v1.2M67.8 105.2l.4-.4v1.2M67.8 110l.4-.4v1.2M67.8 107.6l.4-.4v1.3M67.8 115.6h.7M67.8 113.2h.7M67.8 106h.7M67.8 110.8h.7"/>
<path d="M67.8 108.5h.7M68.8 109.6h.8l-.4 .5 .3 .1v.5l-.5 .1-.2-.1M68.8 100.2l.4-.1a.78 .78 0 0 1 0 1.2l-.4-.1zM68.9 114.7l.4-.3v1.2M68.9 112.1l.6-.1 .1 .4-.8 .8h.8M68.9 115.6h.7M69.2 107.2l-.3 .8h.8M69.5 104.8h-.5l-.1 .6 .6-.1v.7l-.6-.1M69.5 107.6v.9M69.9 100.7h.5M70.1 115h.4M70.1 112.6h.4"/>
<path d="M70.1 105.4h.4M70.1 110.2h.4M70.1 107.8h.4M70.5 100.1h-.6v1.2h.6M70.7 114.4h-.6v1.2h.6M70.7 112h-.6v1.2h.6M70.7 104.8h-.6v1.2h.6M70.7 109.6h-.6v1.2h.6M70.7 107.2h-.6v1.3h.6M73.1 110.4v-1.2l.4 .9 .4-.9v1.2M74.4 109.7l.5-.1v.7h-.5zM75.5 109.6v.6l.2 .2 .3-.1"/>
<path d="M76 109.6v.8M76.6 109.7l.4-.1 .1 .8M76.6 109.6v.8M77 117.3v1.1h1.2l-1.2 1.2-1.2-1.2h1.2M77 117.3h.1M77 104.1v1.2h1.2l-1.2 1.2-1.2-1.2h1.2M77 104.1h.1M77 114.9v2.4M77.6 109.6h.4M77.7 109.2v1.1l.3 .1M78.4 109.2v.1M78.4 109.6v.8"/>
<path d="M78.9 109.7l.5-.1v.8M78.9 109.6v.8M79.8 111.8v1.2M79.8 112.4h.6M79.9 103.8a.45 .45 0 0 0-.7 .2v.6a.45 .45 0 0 0 .7 .2v-.4h-.1M80.4 111.8v1.2M80.5 110.3h-.5l-.1-.5 .2-.2h.4v1.1l-.2 .1-.3-.1M81.1 109.2v1.2M81.1 109.8h.7M81.2 103.7v1.2l-.7-1.2v1.2M81.3 111.8l-.4 .8h.8M81.5 112.3v.7"/>
<path d="M81.7 103.7h.3l.4 .3v.6l-.4 .3h-.3zM81.8 109.2v1.2M82.4 109.6l.5 .1v.6h-.5zM83.4 109.2v1l.2 .2M84 110l.6-.1-.1-.3h-.4l-.1 .2v.4l.2 .2 .3-.1M84.8 110.5h.9M86 109.8h.5l.2-.2-.1-.3-.6-.1v1.2M87.2 109.6h.4l.1 .8M87.7 109.9l-.5 .1-.1 .2 .2 .2 .4-.1M88.7 109.6l-.5 .1v.6h.5M88.7 109.2v1.2M90.1 111.3h7.8"/>
<path d="M90.1 106.5h7.8M90.1 108.9h7.8M90.1 113.7h7.8M90.1 116.1h7.8M90.1 118.4h7.8M90.5 119.1a.66 .66 0 0 1 .7 .5 .66 .66 0 0 1-.3 .7h-.4zM90.5 116.8a.66 .66 0 0 1 .7 .4 .66 .66 0 0 1-.3 .7h-.4zM90.5 112h.4a.66 .66 0 0 1 .3 .8 .66 .66 0 0 1-.7 .4zM90.5 114.4l.6 .2 .1 .3-.1 .5-.3 .2h-.3zM91.6 119.5h.2l.1-.4v1.2M91.6 117.1h.2l.1-.3v1.1M91.6 112.4l.3-.4v1.2"/>
<path d="M91.6 114.7l.3-.3v1.2M91.6 115.6h.7M91.6 113.2h.7M91.6 117.9h.7M91.7 107.2a.64 .64 0 0 1 .7 .6 .64 .64 0 0 1-.7 .7zM91.7 109.6h.4a.66 .66 0 0 1 .2 .8 .66 .66 0 0 1-.6 .4zM91.7 104.8a.66 .66 0 0 1 .6 .5 .66 .66 0 0 1-.2 .7h-.4zM92.7 116.8h.8l-.5 .5 .5 .1v.4l-.2 .1h-.6M92.8 119.3l.4-.2 .3 .4-.8 .8h.8M92.8 104.8h.8l-.6 1.2M93 114.3l-.2 .8h.7M93.3 114.8v.8"/>
<path d="M93.4 107.2a.72 .72 0 0 0-.6 .5 .72 .72 0 0 0 .2 .8l.5-.2v-.5l-.5-.1-.2 .2M93.4 112h-.6v.6l.4-.2 .3 .3-.1 .4h-.6M93.5 109.6h-.6l-.1 .6h.7v.5l-.2 .1h-.3l-.2-.1M93.9 102.9h.3M94 115h.3M94 112.6h.3M94 105.4h.4M94 110.2h.4M94 107.8h.4M94 119.7h.3M94 117.3h.3M94.4 102.3h-.5v1.2h.5"/>
<path d="M94.5 119.1h-.5v1.2h.5M94.5 116.8h-.5v1.1h.5M94.5 112h-.5v1.2h.5M94.5 114.4h-.5v1.2h.5M94.6 107.2h-.6v1.3h.6M94.6 109.6h-.6v1.2h.6M94.6 104.8h-.6v1.2h.6M94.8 102.3l.8 1.2M95.6 102.3l-.8 1.2M95.7 109.8h.7l-.4 .4 .4 .1v.4l-.2 .3h-.4l-.1-.2M95.7 119.3h.7l-.5 1.2M95.8 105.3l.3-.3v1.2"/>
<path d="M95.8 107.5l.4-.1 .2 .3-.7 .8h.7M95.8 106.2h.6M96 112.1l-.2 .8h.6M96.1 102.9l.6-.1-.1-.4-.5-.1v1.2h.6l.1-.4-.4-.2M96.3 116.9l-.5 .3v.8h.6v-.4l-.2-.3h-.3l-.1 .3M96.3 112.5v.9M96.4 114.6h-.6v.5l.4-.1 .2 .2v.5h-.6M97.2 102.4l.2-.1h.3l.2 .1v.4l-.7 .7h.7M98.1 100.5h.6l.1-.5-.7-.1v1.2M98.4 102.3v1.2M98.4 102.9h.7M98.5 100.5l.3 .6"/>
<path d="M99.1 102.3v1.2M99.5 102.3l.4 1.2 .3-1.2M100.9 102.3l-.3 .8h.7M101.1 100.3v.8M101.2 102.7v.8M101.4 111.3h7.8M101.4 106.5h7.8M101.4 108.9h7.8M101.4 113.7h7.8M101.4 116.1h7.8M101.4 118.4h7.8M101.7 102.3h.8l-.5 1.2"/>
<path d="M102.4 105.3l.3-.3v1.2M102.4 107.7l.3-.3v1.1M102.4 110.2l.3-.4v1.2M102.4 112.5l.3-.3v1.2M102.4 114.9l.3-.3v1.1M102.4 117.3l.3-.4v1.2M102.4 119.6l.3-.3v1.2M102.4 106.2h.6M102.4 108.5h.6M102.4 111h.6M102.4 113.4h.6M102.4 115.7h.6"/>
<path d="M102.4 118.1h.6M103 102.4l.3-.1 .2 .2v.8l-.1 .2h-.4l-.1-.5zM103.4 112.2h.7l-.4 .4 .4 .1v.6l-.6 .1-.1-.2M103.5 114.6h.4l.2 .3-.7 .8h.7M103.5 117.3l.3-.4v1.2M103.5 118.1h.6M103.7 109.7l-.2 .9h.7M103.7 119.3a.75 .75 0 0 1 .3 1.2h-.4l-.1-.4v-.6zM104.1 105h-.3a.93 .93 0 0 0-.3 1.2h.6v-.5v-.2h-.6v.2M104.1 107.4h-.6v.5h.6v.6h-.6M104.1 110.2v.8M104.4 102.3v1l-.4 .2"/>
<path d="M104.8 102.3l.4 1.2 .4-1.2M106 114.4l.6 .2 .1 .3-.1 .5-.3 .2h-.3zM106 119.1a.66 .66 0 0 1 .7 .5 .66 .66 0 0 1-.3 .7h-.4zM106 104.8a.66 .66 0 0 1 .7 .5 .66 .66 0 0 1-.3 .7h-.4zM106 107.2a.64 .64 0 0 1 .7 .6 .64 .64 0 0 1-.7 .7zM106 109.6h.4a.66 .66 0 0 1 .3 .8 .66 .66 0 0 1-.7 .4zM106 116.8a.66 .66 0 0 1 .7 .4 .66 .66 0 0 1-.3 .7h-.4zM106 112h.4a.66 .66 0 0 1 .3 .8 .66 .66 0 0 1-.7 .4zM107.1 114.7l.3-.3v1.2M107.1 119.5h.2l.1-.4v1.2M107.1 104.8h.8l-.5 1.2M107.1 117.1h.2l.1-.3v1.1"/>
<path d="M107.1 112.4l.3-.4v1.2M107.1 115.6h.7M107.1 113.2h.7M107.1 117.9h.7M107.7 107.2a.72 .72 0 0 0-.6 .5 .72 .72 0 0 0 .3 .8l.4-.2v-.5l-.4-.1-.3 .2M107.8 109.6h-.6l-.1 .6h.7v.5l-.2 .1h-.3l-.2-.1M108.2 116.8h.8l-.5 .5 .5 .1v.4l-.2 .1h-.6M108.3 119.3l.4-.2 .3 .4-.8 .8h.8M108.5 114.3l-.2 .8h.7M108.8 114.8v.8M108.9 112h-.6v.6l.4-.2 .3 .3-.1 .4h-.6M124.4 115h.9"/>
<path d="M124.8 114.5v.9M125.9 119.6h.1M125.9 117.3v19h8.3v16.7h-4.7M125.9 117.3l-.8 1.1M125.9 117.3l.7 1.1M126.4 114.2h-.6v.6l.4-.2 .3 .3-.1 .4h-.6M126.8 114.2l.4 1.2 .4-1.2M127 103l.3-.4v1.2M127 103.8h.7M128.1 102.6h.8l-.5 .4 .5 .3-.1 .4h-.7M132.5 110.5h.7M132.5 109.9v1.2"/>
<path d="M133.2 109.9v1.2M134.3 109.9h-.6v.6l.6-.1v.7l-.6-.1M136.7 101.8h4.7M137.5 100.6l.3-.4v1.2M137.5 101.4h.7M137.8 116.1v1.2h1.2l-1.2 1.1-1.1-1.1h1.1M137.8 116.1h.1M137.8 113.7v2.4M138.6 100.6l.3-.4v1.2M138.6 101.4h.8M140.1 111.1v-1.2l.4 .8 .4-.8v1.2M141.5 110.4h.5l.1 .5-.2 .2h-.3l-.2-.2z"/>
<path d="M142.4 100.2a.45 .45 0 0 0-.7 .1v.7a.45 .45 0 0 0 .7 .2M142.6 110.3v.8l.5-.1M143.1 110.3v.8M143.6 100.2l-.4-.1-.3 .2 .1 .3 .5 .2v.4h-.6M143.6 110.4h.5v.7M143.6 110.3v.8M144.5 110.3h.5M144.7 109.9v1l.1 .2h.2M145.4 109.9v.2M145.4 110.3v.8M146 110.4l.3-.1 .2 .2v.6M146 110.3v.8"/>
<path d="M147.6 100.6h.8l-.5 1.3M147.6 110.3v1l-.3 .2-.2-.1M147.6 110.4a.36 .36 0 0 0-.6 .2l.1 .5h.5M148.1 110.5h.7M148.1 109.9v1.2M148.5 117.3h7.2M148.5 119.6h7.2M148.8 109.9v1.2M149.1 100.6l-.3 .8h.7M149.4 110.4h.5v.7h-.5l-.1-.2zM149.4 101v.9M149.9 116.8l.5-1.2 .3 1.2"/>
<path d="M149.9 119.1l.5-1.2 .3 1.2M150 118.8h.6M150 116.4h.6M150 100.6v1.3M150 101.2h.7M150.5 109.9v1l.1 .2M150.7 100.6v1.3M151 115.9l.4-.3v1.2M151 118.3h.2l.2-.4v1.2M151 110.7l.6-.1v-.2h-.6v.7h.6M151 119.1h.7M151 116.8h.7"/>
<path d="M151.8 111.3h.9M151.9 100.8l-.3-.2-.4 .3 .1 .8 .3 .2 .3-.2M152.1 117.9h.9l-.5 1.2M152.3 100.6h.8l-.4 .5 .3 .1 .1 .4-.3 .3h-.3l-.2-.2M152.9 116.1l-.4 .2-.2-.1-.1-.4a.35 .35 0 0 1 .4-.2 .35 .35 0 0 1 .3 .2l-.2 .9-.4 .1M153 110.6l.6-.1v-.5l-.6-.1v1.2M153.5 100.8l.2-.2h.3l.2 .2v.4l-.8 .7h.8M154.2 116.1l.3-.4v1.2M154.2 118.2l.4-.1 .3 .3-.8 .9h.8M154.2 110.4h.5v.7h-.5v-.4l.5-.1M154.2 116.9h.7M155.7 116.1h14.3v38.1h-14.3z"/>
<path d="M155.8 109.9v1.2h-.4l-.2-.2 .1-.5h.5M156.3 115.4l.4-1.2 .4 1.2M156.5 115.1h.5M156.5 117.8l.4-1.2 .4 1.2M156.6 117.4h.6M156.6 119.8h.6M157.6 116.9h.2l.2-.3v1.2M157.6 119.3h.2l.2-.3v1.1M157.6 117.8h.7M158.2 114.3h-.7v.3l.7 .5-.3 .3-.4-.1M159 117.1l-.2-.1 .2-.4h.3l.2 .2-.2 .3h-.3l-.2 .2 .1 .5h.4l.2-.2v-.3l-.2-.2M159.2 114.2l-.4 .1-.2 .8a.35 .35 0 0 0 .3 .3 .35 .35 0 0 0 .4-.3v-.2l-.3-.3-.4 .3"/>
<path d="M159.3 119h-.3l-.2 .3v.8h.5l.2-.1v-.4l-.2-.1h-.4l-.1 .1M160.4 114.3a.55 .55 0 0 0-.7 .5 .55 .55 0 0 0 .7 .5M161.2 114.1l-.3 .9h.7M161.4 111.8v1a.35 .35 0 0 0 .3 .2 .35 .35 0 0 0 .4-.2v-1M161.5 114.6v.8M162.1 114.3l.4-.1a.78 .78 0 0 1 0 1.2l-.4-.1zM162.6 112.2l.3-.4v1.2M162.6 113h.6M163.3 114.3l.3-.1 .2 .3v.6l-.3 .3a.7 .7 0 0 1-.2-1.1zM163.8 111.9l.3-.1a.64 .64 0 0 1 .3 .7 .64 .64 0 0 1-.4 .5l-.3-.2zM164.5 114.7l-.2-.1v-.3h.6v.3l-.6 .2v.5l.2 .1h.3l.2-.3-.2-.4M166 116.6l.4 1.2 .4-1.2"/>
<path d="M166.2 119.8h.6M166.5 112.5v1.2h1.1l-1.1 1.2-1.2-1.2h1.2M166.5 112.5h.1M167.2 119.3h.2l.2-.3v1.1M167.9 116.8l-.3-.2a.67 .67 0 0 0-.5 .5 .67 .67 0 0 0 .3 .7l.5-.1M168.7 113.5h-.6l-.1 .3v.6l.1 .2h.6v-.4h-.2M169 119h-.5l-.1 .5h.6v.6h-.6M169.1 116.8l-.3-.2a.67 .67 0 0 0-.5 .5 .67 .67 0 0 0 .3 .7l.5-.1M169.8 113.5v1.2l-.6-1.2v1.2M170 119.6h7.1M170.3 115.7h.6l-.3 .5 .3 .1v.5h-.6M170.3 118.1h.6l-.3 .5 .3 .1v.5h-.6"/>
<path d="M170.4 113.5h.5a.66 .66 0 0 1 .2 .8 .66 .66 0 0 1-.7 .4zM170.7 111.3h-4.2v1.2M171.5 115.8l.4-.1 .2 .4-.7 .8h.7M171.5 118.4l.3-.3v1.2M171.5 119.3h.6M171.7 111.3h4.2M173.1 112.4l-.3-.1a.6 .6 0 0 0-.5 .6 .6 .6 0 0 0 .7 .6l.1-.1M173.5 112.7l.3-.4v1.2M173.5 113.5h.7M173.8 119.1l.4-1.2 .4 1.2M173.9 118.8h.6M174.4 105.4h.9"/>
<path d="M174.7 112.4l.4-.1 .2 .4-.7 .8h.7M174.8 105v.8M174.9 118.3l.4-.4v1.2M174.9 119.1h.7M175.7 104.6l.4 1.2 .4-1.2M175.9 110.1h.1M175.9 107.7l-.6 1.2M175.9 107.7l.8 1.2M175.9 107.7v9.6h-5.9M176.6 117.9l-.3 .1-.2 .3v.7l.5 .1 .2-.1v-.4l-.2-.2h-.4l-.1 .2M176.9 105.2h.6v-.5l-.6-.1v1.2h.6l.1-.3-.3-.3M177.5 112.7l.3-.4v1.2"/>
<path d="M177.5 113.5h.7M178.9 112.3a.68 .68 0 0 1 .4 .6 .68 .68 0 0 1-.4 .6l-.3-.5 .1-.6zM179.9 112.4l.3-.1 .2 .2v.8l-.2 .2a.71 .71 0 0 1-.3-1.1zM180.8 117.3h7.1M180.8 119.6h7.1M180.9 112.9l.2-.2 .3 .1v.7M180.9 112.7v.8M182 112.9h.5M182.1 116.8l.4-1.2 .5 1.2M182.1 119.1l.4-1.2 .5 1.2M182.3 118.8h.5M182.3 116.4h.5"/>
<path d="M182.6 112.3h-.6v1.2M183.3 115.9l.3-.3v1.2M183.3 118.3l.3-.4v1.2M183.3 119.1h.7M183.3 116.8h.7M184.3 117.9h.9l-.5 1.2M185.1 116.1l-.4 .2-.3-.2v-.3a.35 .35 0 0 1 .3-.2 .35 .35 0 0 1 .4 .2l-.2 .9-.4 .1M186.4 116.1l.3-.4v1.2M186.4 118.2h.6v.4l-.7 .7h.7M186.4 116.9h.6M187.9 116.1h14.3v38.1h-14.3zM188.3 115.4l.3-1.2 .5 1.2"/>
<path d="M188.4 115.1h.6M188.7 117.8l.4-1.2 .4 1.2M188.8 117.4h.6M188.8 119.8h.6M189.8 116.9h.2l.2-.3v1.2M189.8 119.3h.2l.2-.3v1.1M189.8 117.8h.7M190.1 114.3h-.6v.4l.5 .2 .1 .2-.3 .3-.4-.1M191.1 114.2h-.3a.73 .73 0 0 0 0 1.2l.4-.1v-.5l-.4-.2-.3 .3M191.3 117.1h-.2a.31 .31 0 0 1 .1-.4 .31 .31 0 0 1 .4 .1v.3l-.5 .1v.6h.5l.1-.5-.3-.2M191.6 119h-.3a.93 .93 0 0 0-.2 1.1h.5l.1-.5-.1-.1h-.5l-.1 .1M192.4 114.3l-.2-.1a.6 .6 0 0 0-.5 .6 .6 .6 0 0 0 .5 .6l.2-.1"/>
<path d="M193.1 114.1l-.2 .9h.7M193.5 114.6v.8M194.1 114.3l.3-.1 .2 .3v.6l-.3 .3a.7 .7 0 0 1-.2-1.1zM194.1 111.8v1a.35 .35 0 0 0 .4 .2 .35 .35 0 0 0 .3-.2v-1M195.2 114.3l.3-.1a.64 .64 0 0 1 .4 .6 .64 .64 0 0 1-.5 .6l-.2-.3zM195.6 112.4l-.3-.3a.35 .35 0 0 1 .4-.3 .35 .35 0 0 1 .3 .3l-.3 .3a.36 .36 0 0 0-.4 .4 .36 .36 0 0 0 .5 .2 .36 .36 0 0 0 .1-.6h-.2M196.5 114.7l-.2-.2 .2-.3 .4 .1v.3a.51 .51 0 0 0-.6 .7h.6v-.5l-.1-.1M198.2 116.6l.4 1.2 .4-1.2M198.5 119.8h.5M198.6 112.5v1.2h1.2l-1.2 1.2-1.2-1.2h1.2M198.6 112.5h.1M199.5 119.3l.3-.3v1.1"/>
<path d="M200.1 116.8l-.3-.2a.67 .67 0 0 0-.5 .5 .67 .67 0 0 0 .3 .7l.5-.1M200.8 113.5h-.4a.67 .67 0 0 0-.2 .7 .67 .67 0 0 0 .5 .5l.2-.1v-.4h-.2M200.9 107.4l.4-.3v1.2M200.9 108.3h.7M201.2 119h-.5l-.1 .5h.6v.6h-.6M201.3 116.8l-.3-.2a.67 .67 0 0 0-.5 .5 .67 .67 0 0 0 .2 .7l.6-.1M202.1 113.5v1.2l-.7-1.2v1.2M202.1 107.2l.1-.1a.59 .59 0 0 1 .5 .4 .59 .59 0 0 1-.1 .6l-.2 .2-.3-.2zM202.2 119.6h7.2M202.4 115.7h.8l-.4 .5 .4 .2-.1 .4h-.7M202.4 118.1h.8l-.4 .5 .4 .2v.3l-.2 .2-.6-.1M202.6 113.5h.5l.2 .3v.6l-.4 .3h-.3z"/>
<path d="M202.6 104.8l-.3-.2-.4 .4v.6l.2 .2 .5-.1M202.9 111.3h-4.3v1.2M203.1 105l.4-.4v1.2M203.1 105.8h.7M203.3 107.1h.3l.2 .2v.7l-.3 .3a.71 .71 0 0 1-.2-1.2zM203.6 115.8l.4-.1 .3 .4-.8 .8h.8M203.6 118.4l.4-.3v1.2M203.6 119.3h.7M203.9 111.3h4.3M204.1 104.6h.8l-.4 .6h.4v.5h-.8M204.3 107.6l.2-.2 .4 .2v.7M204.3 107.4v.9"/>
<path d="M205.4 107.6h.4M206 119.1l.4-1.2 .4 1.2M206 107.1h-.6v1.2M206.1 118.8h.6M206.6 105.4h.9M207.1 118.3h.2l.1-.4v1.2M207.1 119.1h.7M207.1 105v.8M207.9 104.6l.4 1.2 .4-1.2M208.2 110.1h.1M208.2 107.7v9.6h-6M208.2 107.7l-.8 1.2"/>
<path d="M208.2 107.7l.7 1.2M208.8 117.9l-.4 .1-.1 .3v.7l.5 .1 .2-.1v-.4l-.2-.2h-.4l-.1 .2M209.1 105.2h.5v-.5l-.5-.1v1.2h.5l.2-.3-.3-.3M212.9 117.3h7.2M212.9 119.6h7.2M214.4 119.1l.3-1.2 .4 1.2M214.4 116.8l.3-1.2 .4 1.2M214.5 118.8h.6M214.5 116.4h.6M215.5 118.3l.3-.4v1.2M215.5 115.9l.3-.3v1.2M215.5 119.1h.7"/>
<path d="M215.5 116.8h.7M216.6 117.9h.7l-.5 1.2M217.3 116.1l-.2 .2h-.3l-.2-.2 .1-.4h.6v.8l-.6 .3M218.5 116.1l.4-.4v1.2M218.5 118.2h.7v.4l-.7 .7h.7M218.5 116.9h.7M220 115.4l.4-1.2 .4 1.2M220.1 116.1h14.3v38.1h-14.3zM220.1 115.1h.5M220.9 117.8l.4-1.2 .4 1.2M221.1 117.4h.5M221.1 119.8h.5"/>
<path d="M221.8 114.3h-.7v.3l.7 .5-.2 .3-.5-.1M222.1 116.9l.3-.3v1.2M222.1 119.3l.3-.3v1.1M222.1 117.8h.7M222.8 114.2l-.4 .1-.1 .8a.35 .35 0 0 0 .3 .3 .35 .35 0 0 0 .3-.3v-.2l-.2-.3-.4 .3M223.4 117.1h-.1a.31 .31 0 0 1 .1-.4 .31 .31 0 0 1 .4 .1v.3l-.5 .1v.6h.5l.1-.2v-.3l-.3-.2M223.8 119h-.3a.93 .93 0 0 0-.2 1.1h.5l.1-.5-.1-.1h-.5l-.1 .1M224.1 114.3a.55 .55 0 0 0-.8 .5 .55 .55 0 0 0 .8 .5M224.9 114.1l-.3 .9h.7M225.1 114.6v.8M225.8 114.3l.3-.1a.78 .78 0 0 1 0 1.2l-.3-.1zM226.3 111.8v1l.3 .2 .4-.1v-1.1"/>
<path d="M227 114.3l.2-.1 .3 .3v.6l-.3 .3a.7 .7 0 0 1-.2-1.1zM228.2 114.7l-.2-.1v-.3h.6v.3l-.6 .2v.5l.4 .1a.35 .35 0 0 0 .3-.3 .35 .35 0 0 0-.3-.4M228.2 112.4l-.2 .2h-.2l-.3-.2 .1-.5h.6v.9l-.5 .2M230.4 116.6l.4 1.2 .4-1.2M230.6 119.8h.6M230.8 112.5v1.2h1.2l-1.2 1.2-1.2-1.2h1.2M230.8 112.5h.1M231.6 119.3l.4-.3v1.1M232.2 116.8l-.3-.2-.3 .3v.6l.1 .3 .5-.1M233 113.5h-.4a.67 .67 0 0 0-.3 .7 .67 .67 0 0 0 .5 .5l.3-.1v-.4h-.3M233.1 107.4l.3-.3v1.2M233.1 108.3h.7"/>
<path d="M233.4 116.8l-.3-.2-.4 .3v.6l.2 .3 .5-.1M233.4 119h-.6l-.1 .5h.6l.1 .6h-.7M234.3 113.5v1.2l-.7-1.2v1.2M234.4 107.1h.3l.2 .2v.7l-.3 .3a.71 .71 0 0 1-.2-1.2zM234.4 119.6h7.2M234.6 115.7h.8l-.4 .5h.3v.6h-.7M234.6 118.1h.8l-.4 .5h.3v.7l-.7-.1M234.9 113.5h.4a.66 .66 0 0 1 .2 .8 .66 .66 0 0 1-.6 .4zM234.9 104.8l-.3-.2a.67 .67 0 0 0-.5 .6 .67 .67 0 0 0 .3 .6l.5-.1M235.1 111.3h-4.3v1.2M235.3 105l.3-.4v1.2M235.3 105.8h.7"/>
<path d="M235.4 107.3l.1-.2a.6 .6 0 0 1 .6 .4 .6 .6 0 0 1-.2 .7l-.3 .1-.2-.3zM235.8 115.8h.7v.4l-.7 .7h.7M235.8 118.4l.3-.3v1.2M235.8 119.3h.7M236.1 111.3h4.3M236.6 107.6l.1-.2 .4 .2v.7M236.6 107.4v.9M236.7 104.6l-.3 .9h.8M237 105.1v.7M237.6 107.6h.4M238.2 119.1l.4-1.2 .4 1.2M238.2 107.1h-.6v1.2"/>
<path d="M238.3 118.8h.5M238.8 105.4h.9M239.3 105v.8M239.4 118.3l.3-.4v1.2M239.4 119.1h.6M240.1 104.6l.4 1.2 .4-1.2M240.4 110.1h.1M240.4 107.7v9.6h-6M240.4 107.7l-.8 1.2M240.4 107.7l.6 1.2M241 117.9h-.2a.93 .93 0 0 0-.3 1.2h.5l.1-.5-.1-.2h-.5v.2M241.3 105.2h.6v-.4l-.2-.2h-.4v1.2h.6l.1-.3-.3-.3"/>
<path d="M245.1 117.3h7.2M245.1 119.6h7.2M246.5 119.1l.5-1.2 .3 1.2M246.5 116.8l.5-1.2 .3 1.2M246.6 118.8h.6M246.6 116.4h.6M247.7 118.3h.1l.2-.4v1.2M247.7 115.9l.3-.3v1.2M247.7 119.1h.6M247.7 116.8h.6M248.8 117.9h.7l-.5 1.2M249.5 116.1l-.2 .2-.5-.1v-.5l.5-.1a.73 .73 0 0 1-.1 1.2h-.3"/>
<path d="M250.8 116.1l.3-.4v1.2M250.8 118.2l.4-.1 .3 .3-.8 .9h.8M250.8 116.9h.7M252.3 116.1h14.3v38.1h-14.3zM252.4 115.4l.4-1.2 .4 1.2M252.6 115.1h.5M253.2 117.8l.3-1.2 .4 1.2M253.2 117.4h.6M253.2 119.8h.6M254.3 116.9l.3-.3v1.2M254.3 119.3l.3-.3v1.1M254.3 114.3h-.7v.3l.7 .5-.3 .3-.4-.1"/>
<path d="M254.3 117.8h.6M255.3 114.2l-.5 .1-.1 .8 .2 .3 .5-.1v-.5l-.2-.2h-.3l-.2 .3M255.6 117.1l-.2-.3 .2-.2h.3l.1 .4-.4 .1-.2 .2 .1 .5 .5-.1v-.4l-.1-.2M255.9 119l-.4 .1-.1 .9 .1 .1h.5l-.1-.6h-.4l-.1 .1M256.5 114.3a.45 .45 0 0 0-.6 .2v.6a.45 .45 0 0 0 .6 .2M257.3 114.1l-.3 .9h.7M257.6 114.6v.8M258.2 114.3l.4-.1a.78 .78 0 0 1 0 1.2l-.4-.1zM258.6 111.8v1.1l.1 .1h.3l.2-.2v-1M259.4 114.3l.3-.1a.64 .64 0 0 1 .3 .6 .64 .64 0 0 1-.4 .6 .7 .7 0 0 1-.2-1.1zM259.7 111.8h.7l-.5 1.2M260.7 114.7l-.3-.2a.35 .35 0 0 1 .4-.3 .35 .35 0 0 1 .3 .3l-.2 .2a.36 .36 0 0 0-.5 .4 .36 .36 0 0 0 .6 .3 .36 .36 0 0 0 0-.6l-.1-.1"/>
<path d="M262.6 116.6l.4 1.2 .4-1.2M262.8 119.8h.6M263.1 112.5v1.2h1.1l-1.1 1.2-1.3-1.2h1.3M263.1 112.5h.1M263.8 119.3h.2l.2-.3v1.1M264.5 116.8l-.3-.2a.67 .67 0 0 0-.5 .5 .67 .67 0 0 0 .3 .7l.5-.1M265.2 113.5h-.4a.67 .67 0 0 0-.3 .7 .67 .67 0 0 0 .5 .5l.3-.1v-.4h-.3M265.3 107.4l.3-.3v1.2M265.3 108.3h.6M265.6 119h-.6v.5h.5l.2 .1v.4l-.2 .1h-.5M265.7 116.8l-.3-.2a.67 .67 0 0 0-.5 .5 .67 .67 0 0 0 .3 .7l.5-.1M266.4 107.3l.2-.2a.6 .6 0 0 1 .6 .4 .6 .6 0 0 1-.2 .7l-.3 .1-.3-.3z"/>
<path d="M266.4 113.5v1.2l-.6-1.2v1.2M266.6 119.6h7.1M266.8 115.7h.7l-.4 .5 .4 .1v.5h-.7M266.8 118.1h.7l-.4 .5 .4 .1v.5h-.7M267 113.5h.5a.66 .66 0 0 1 .2 .8 .66 .66 0 0 1-.7 .4zM267 104.8l-.2-.2a.67 .67 0 0 0-.5 .6 .67 .67 0 0 0 .2 .6l.5-.1M267.3 111.3h-4.2v1.2M267.5 105h.1l.2-.4v1.2M267.5 105.8h.6M267.6 107.2l.1-.1a.59 .59 0 0 1 .6 .4 .59 .59 0 0 1-.2 .6l-.1 .2-.4-.2zM268.1 115.8l.4-.1 .2 .4-.7 .8h.7M268.1 118.4l.3-.3v1.2"/>
<path d="M268.1 119.3h.6M268.3 111.3h4.2M268.7 107.6l.2-.2 .3 .2v.7M268.7 107.4v.9M269.2 104.6h-.6v.6h.6l.1 .1v.4l-.1 .1-.6-.1M269.8 107.6h.4M270.3 119.1l.5-1.2 .4 1.2M270.3 107.1h-.5v1.2M270.5 118.8h.6M271 105.4h.9M271.4 105v.8M271.5 118.3l.4-.4v1.2"/>
<path d="M271.5 119.1h.7M272.3 104.6l.4 1.2 .4-1.2M272.5 110.1h.1M272.5 107.7l-.6 1.2M272.5 107.7l.8 1.2M272.5 107.7v9.6h-5.9M273.2 117.9l-.4 .2-.2 .9 .2 .1 .5-.1-.1-.6h-.4l-.2 .2M273.5 105.2h.6l.1-.3-.3-.3h-.4v1.2h.6l.1-.5-.3-.1M276.6 109.6h1.9M19.7 132.6l-.2-.2a.65 .65 0 0 0-.5 .7 .65 .65 0 0 0 .5 .6l.2-.2M22.2 133.9h5.9M22.5 132.2v1.2"/>
<path d="M23.8 132.2v1.2l-.7-1.2v1.2M24.2 132.2l.4 1.2 .4-1.2M25.1 133.6h.9M25.1 124.5h.7l-.3 .5 .3 .1v.5h-.7M26.2 132.2v1.2M26.3 125.6h.1M27.4 124.5h-.4a.94 .94 0 0 0 0 1.1h.5v-.5l-.5-.1-.2 .1M27.5 132.2v1.2l-.7-1.2v1.2M27.9 124.5l.4 1.1 .4-1.1M29.5 139.3v1l-.5 .2M30 139.3h.7l-.4 .4 .3 .1v.6h-.6M30.5 120.7h.8v.3h-.8z"/>
<path d="M30.5 123.1h.8v.3h-.8zM30.6 124.5v1.1l-.6-1.1v1.1M31.2 124.5h.1M31.2 124.9v.7M31.3 120.8h35M31.3 123.2h13.5v1.2M31.4 130.4l.4-.4v1.2M31.4 135.1l.4-.3v1.2M31.4 131.2h.7M31.4 136h.7M31.8 125.6v-1.1l.4 .8 .4-.8v1.1M32.4 134.8h.8l-.4 .5h.3v.7l-.7-.1"/>
<path d="M32.5 130.1l.4-.1 .3 .4-.8 .8h.8M33.1 121.8l.2-.1h.3l.2 .1v.4l-.7 .7h.7M33.1 120.5h.7M33.2 124.5v1.1M33.2 125.1h.7M33.9 124.5v1.1M34 131.6h-5.9v4.7h5.9M34.3 127.3h.8l-.5 1.2M35.8 127.3l-.3 .8h.7M36.1 127.8v.7M36.2 125v1.1a.36 .36 0 0 0 .6-.2v-.9M36.7 127.3v1.2"/>
<path d="M36.7 127.9h.7M37.3 125.3l.4-.3v1.2M37.3 126.2h.7M37.4 127.3v1.2M38.5 125h.4a.66 .66 0 0 1 .3 .7 .66 .66 0 0 1-.7 .5zM38.6 127.4a.45 .45 0 0 0-.7 .2v.7a.45 .45 0 0 0 .7 .1M39.2 127.4l.3-.1a.64 .64 0 0 1 .3 .7 .64 .64 0 0 1-.4 .5l-.3-.2zM39.4 120.3l.3-1.2 .4 1.2M40.3 127.4l.3-.1a.78 .78 0 0 1 0 1.2l-.3-.1zM42.1 132.8h.1l.2-.4v1.2M42.1 133.6h.7M42.1 120.5h.9"/>
<path d="M42.4 133.9h9.6M43.3 132.8l.3-.4v1.2M43.3 133.6h.6M43.9 128.6a.54 .54 0 0 0-.7 .6 .54 .54 0 0 0 .7 .4v-.4h-.2M44.8 124.4v1.2h1.2l-1.2 1.2-1.2-1.2h1.2M44.8 124.4h.1M45.1 128.5v1.2l-.6-1.2v1.2M45.2 132.2v1.2M45.7 128.5l.6 .2 .1 .3-.1 .5-.3 .2h-.3zM46.4 132.2v1.2l-.7-1.2v1.2M46.8 132.2l.4 1.2 .4-1.2M47.5 138.7l.6-.1v-.5h-.6v1.2"/>
<path d="M47.8 133.6h.9M47.8 138.7l.4 .6M48.5 127l-.2-.2a.67 .67 0 0 0-.5 .5 .67 .67 0 0 0 .2 .7l.5-.1M48.6 138.1h.8l-.5 .4 .4 .1 .1 .4-.3 .3h-.3l-.2-.2M48.9 132.4l.3-.2 .3 .1a.87 .87 0 0 1 0 1.1h-.5l-.1-.3zM48.9 127.2h.2l.2-.4v1.2M48.9 128h.7M50.2 132.2l.1 1.2h.4l.2-.1v-1.1M50.6 126.8l-.3 .1-.2 .3v.7l.5 .1 .2-.2v-.3l-.2-.2h-.4l-.1 .2M51.2 132.2h.7M51.6 132.2v1.2M52 128v1.2h1.2l-1.2 1.2-1.2-1.2h1.2"/>
<path d="M52 128h.1M52 120.8v4.3M52 126.1v1.9M54.2 125.3l.3-.3v1.2M54.2 126.2h.7M54.4 122.9l-.2-.3 .1-.3h.5v.5l-.5 .1a.35 .35 0 0 0 0 .5 .35 .35 0 0 0 .5 0 .35 .35 0 0 0 0-.5h-.2M54.6 128.9a.54 .54 0 0 0-.7 .5 .54 .54 0 0 0 .8 .5v-.4h-.3M55.4 125.1l.1-.1a.6 .6 0 0 1 .6 .5 .6 .6 0 0 1-.4 .7l-.3-.3zM55.5 122.3h.3l.2 .2v.8l-.4 .2a.84 .84 0 0 1-.1-1.2zM55.5 120.3h2.4v1h-2.4zM55.9 128.8v1.2l-.7-1.2v1.2M56.5 122.5l.1-.2h.4a.86 .86 0 0 1-.1 1.2l-.4-.2z"/>
<path d="M56.5 128.8a.6 .6 0 0 1 .7 .6 .6 .6 0 0 1-.7 .6zM56.6 125.1l.4-.1a.91 .91 0 0 1-.1 1.2l-.3-.1zM57.7 122.9l.1-.2 .4 .2v.6M57.7 125.5l.1-.2 .4 .2v.7M57.7 122.7v.8M57.7 125.3v.9M58.2 122.9l.1-.2 .4 .2v.6M58.8 125.5h.3M59.1 123.5l.3-1.2 .5 1.2M59.2 123.2h.6M59.4 125h-.6v1.2M61.5 128v3.8l1 .4-2 .6 2 .8-2 .7 2 .7-2 .7 1 .4v6.2l-1.8 1.8"/>
<path d="M61.5 130.4h.1M61.5 128l-.7 1.2M61.5 128l.7 1.2M61.5 138.7h8.4M62.3 128.3h.9M62.7 127.8v1M63.7 127.6l.3 1.2 .4-1.2M64.3 132.8l.6-.1v-.5l-.6-.1v1.2M64.3 120.3l.5-1.2 .4 1.2M64.5 134.5l-.3 .8h.7M64.5 132.8l.4 .5M64.8 134.9v.8"/>
<path d="M64.9 128.1h.5v-.5h-.5v1.2h.4l.2-.4-.3-.3M65.3 136.7h4.4M65.4 135.6v.1M65.7 132.1l-.3 .8h.7M65.9 134.5h.7l-.5 1.2M66 132.5v.8M66 137.1h-.5l-.1 .1 .1 .4 .5 .2v.3l-.1 .2-.5-.1M67.1 134.5v1.2M67.2 137.1l-.7 .1v.3l.7 .4-.2 .4-.5-.1M67.2 135.2l.4 .5M67.6 134.9l-.5 .5M68 135.7h.3v-.2l-.3-.4 .1-.5 .2-.1 .5 .1a.6 .6 0 0 1-.1 .9v.2h.2"/>
<path d="M68.4 137.2l-.5-.1a.67 .67 0 0 0-.3 .6 .67 .67 0 0 0 .6 .6l.2-.2M69.5 137.1h-.5l-.2 .1 .2 .4 .5 .2v.3l-.2 .2-.5-.1M71 126.8h10.8M72.5 126.3l.3-1.2 .4 1.2M72.6 126h.6M73.6 125.5l.3-.4v1.2M73.6 126.3h.7M75.4 125.6l-.1 .2h-.5l-.1-.2v-.3l.1-.2 .6 .1v.8l-.2 .2-.4 .1M76.1 121.4h-.5l-.2 .3v.6l.2 .2h.5v-.4h-.2M77.3 121.4v1.2l-.7-1.2v1.2M77.9 121.4h.5l.2 .3v.6l-.4 .3h-.3zM79.9 125.2l-.2 .9h.6"/>
<path d="M80.2 125.6v.9M80.3 130h-.6v.6l.4-.1 .2 .2v.4h-.6M81.8 131.6h-7.2v19M82 122.6h.8l-.5 1.2M83.5 122.5l-.3 .9h.8M83.8 120.1v1.1l.3 .2 .4-.2v-1.1M83.8 122.9v.9M84.4 122.6v1.2M84.4 123.1h.7M85 120.5h.2l.1-.4v1.3M85 121.4h.7M85.1 122.6v1.2"/>
<path d="M86.2 120.7l.6-.1 .1-.2-.3-.3h-.4v1.3h.5l.2-.2v-.4l-.3-.1M86.4 122.7l-.5-.1a.67 .67 0 0 0-.3 .7 .67 .67 0 0 0 .5 .5l.3-.2M86.5 139.9h17.2M86.9 122.7l.1-.1a.59 .59 0 0 1 .5 .4 .59 .59 0 0 1-.1 .6l-.2 .2-.3-.2zM88 137.9h2M88.1 122.6a.61 .61 0 0 1 .6 .4 .61 .61 0 0 1-.2 .7 .61 .61 0 0 1-.7-.4 .61 .61 0 0 1 .3-.7zM88.8 138.3h-.5a.67 .67 0 0 0-.2 .6 .67 .67 0 0 0 .5 .5l.2-.1M89.9 138.3h-.6v.5l.5 .1 .1 .3-.2 .2h-.5M90.1 120.8h7.8M90.1 123.2h7.8M90.4 138.6l.4-.3v1.1M90.4 139.4h.7"/>
<path d="M90.5 121.5a.64 .64 0 0 1 .7 .6 .64 .64 0 0 1-.7 .7zM90.9 127.7l-.4 .1-.2 .8 .3 .3 .4-.1v-.5l-.2-.2h-.2l-.3 .3M91.6 121.9l.3-.4v1.3M91.6 120.3h.7M91.6 122.8h.7M91.6 138.8h.3M92.1 138.3h-.5v1.1h.5M92.8 121.9l.3-.4v1.3M92.8 122.8h.7M94 122.1h.3M94.5 121.5h-.5v1.3h.5M95.9 122.2l-.1-.1v-.3l.4-.1 .2 .3-.6 .3v.5l.5 .1 .1-.5-.2-.2"/>
<path d="M96.1 132.8h.1M96.1 130.4v3.8l.9 .3-1.8 .8 1.8 .7-1.8 .7 1.8 .7-1.8 .7 .9 .4v1.4M96.1 130.4l-.8 1.2M96.1 130.4l.7 1.2M97.4 131.4h.9M97.9 131v.8M98.9 135.1h.4l.3-.4-.3-.2h-.4v1.2M99.1 136.8l-.3 .9h.8M99.1 135.1l.5 .6M99.4 137.2v.9M99.5 130.6h-.6l-.1 .6 .6-.1 .1 .6h-.7M99.8 130.6l.4 1.2 .5-1.2"/>
<path d="M100 137.9v.2M100.4 136.9h.9l-.5 1.2M100.6 134.5h-.3a.93 .93 0 0 0-.2 1.1h.5l.1-.5-.1-.1h-.5l-.1 .1M101.4 120.8h7.8M101.4 123.2h7.8M101.7 136.9v1.2M101.8 137.6l.3 .5M102 138.9l-.1 .2h-.5l-.1-.2 .1-.5 .5 .1a.85 .85 0 0 1-.2 1.1h-.3M102.1 137.2l-.4 .6M102.4 120.5h.6M102.6 138.1h.3v-.3l-.3-.1v-.6l.2-.2h.6l.1 .6-.3 .3v.3h.3M103.5 135.7h.8l-.5 1.2"/>
<path d="M103.5 122.2v.1l-.4 .1-.2-.2v-.3l.2-.2 .4 .1v.8l-.1 .3h-.4M105 135.6l-.4 .9h.8M105.2 136.1v.8M105.3 133.3l.1 1.2h.4l.2-.2v-1M105.8 136.2h.8M105.8 135.7v1.2M106 121.5a.64 .64 0 0 1 .7 .6 .64 .64 0 0 1-.7 .7zM106.6 135.7v1.2M107.1 121.9l.3-.4v1.3M107.1 133.3h-.3a.93 .93 0 0 0-.2 1.2h.5l.1-.6-.1-.1h-.5l-.1 .1M107.1 120.3h.7M107.1 122.8h.7"/>
<path d="M107.8 135.8l-.5-.1-.2 .3 .1 .7 .2 .2 .4-.2M108.2 135.7h.8l-.5 .4 .4 .1 .1 .5-.3 .2h-.3l-.2-.2M108.3 121.9l.3-.4v1.3M108.3 122.8h.7M108.4 133.4l-.3-.1a.67 .67 0 0 0-.5 .5 .67 .67 0 0 0 .3 .7l.5-.1M109.4 135.8l.6-.1 .1 .4-.8 .8h.8M125.9 120.8h3.6v4.3M126.7 139.3v1l-.5 .2M127.8 139.3l-.5 .1-.1 .8 .2 .3 .4-.1v-.6l-.4-.1-.2 .3M128.5 132.2l-.1-.1a.66 .66 0 0 0-.5 .5 .66 .66 0 0 0 .2 .7l.5-.1v-.4h-.2M129.5 128v1.2h1.1l-1.1 1.2-1.2-1.2h1.2M129.5 128h.1"/>
<path d="M129.5 126.1v1.9M129.8 132.1v1.2l-.7-1.2v1.2M130.4 132.1a.66 .66 0 0 1 .6 .4 .66 .66 0 0 1-.2 .8h-.4zM132.2 126.5l.3-.3v1.1M132.2 127.3h.6M132.9 123.9l-.5-.1a.67 .67 0 0 0-.2 .7 .67 .67 0 0 0 .5 .5l.2-.1M133.4 124.1l.3-.3v1.2M133.4 125h.6M133.4 126.2h.3a.64 .64 0 0 1 .4 .6 .64 .64 0 0 1-.5 .5l-.2-.2zM134.5 123.8h.7l-.5 1.2M134.5 126.2h.4a.78 .78 0 0 1 0 1.1h-.4zM135.6 126.7l.5-.1v.7"/>
<path d="M135.6 126.6v.7M136.7 126.7h.5M136.9 120.2l-.1-.1a.64 .64 0 0 0-.6 .6 .64 .64 0 0 0 .5 .7l.3-.2v-.4h-.3M137.3 126.2h-.6v1.1M138.2 120.1v1.3l-.7-1.3v1.3M138.7 120.1a.65 .65 0 0 1 .7 .7 .65 .65 0 0 1-.7 .6zM148.5 126.8h7.2M148.5 131.6h7.2M148.5 129.2h7.2M148.5 136.3h7.2M148.5 133.9h7.2M148.5 122h7.2"/>
<path d="M148.5 124.4h7.2M148.5 138.7h7.2M149.9 126.3l.5-1.2 .3 1.2M149.9 131.1l.5-1.2 .3 1.2M149.9 128.7l.5-1.2 .3 1.2M149.9 138.3l.5-1.2 .3 1.2M149.9 135.9l.5-1.3 .3 1.3M149.9 133.4l.5-1.2 .3 1.2M149.9 124l.5-1.2 .3 1.2M149.9 121.5l.5-1.2 .3 1.2M150 126h.6M150 137.9h.6"/>
<path d="M150 130.7h.6M150 128.4h.6M150 133.1h.6M150 135.5h.6M150 121.2h.6M150 123.6h.6M151 127.5h.8l-.5 1.2M151 139.5h.7v.5l-.7 .6h.7M151 137.1h.7l-.3 .4 .3 .1v.5l-.1 .2h-.4l-.2-.2M151 123.1l.4-.3v1.2M151 120.6h.2l.2-.3v1.2M151 121.5h.7"/>
<path d="M151 124h.7M151.3 125.6l-.3-.3 .2-.2h.4l.1 .4-.7 .3v.3l.3 .2 .4-.1v-.5l-.1-.1M151.4 134.6l-.4 .9h.8M151.6 129.9h-.2a.73 .73 0 0 0-.1 1.2l.4-.1v-.5l-.4-.2-.3 .3M151.6 135v.9M151.7 132.2h-.6l-.1 .6h.6l.1 .5h-.7M152.1 122.8h.8l-.4 .4 .4 .2-.1 .5-.5 .1-.2-.2M152.8 120.3h-.5l-.1 .6 .6-.1v.7l-.6-.1M153.6 137.6l.3-.4v1.2M153.6 140l.3-.4v1.2M153.6 138.4h.7M154.1 120.5h.8l-.5 .5h.4v.7l-.7-.1"/>
<path d="M154.1 130h.8l-.5 1.2M154.4 122.9l-.2 .8h.7M154.4 132.9h-.1l-.1-.2a.34 .34 0 0 1 .4-.3 .34 .34 0 0 1 .3 .4l-.1 .1-.5 .1v.6h.5l.1-.4-.3-.3M154.8 125.3h-.5l-.1 .5h.6v.6l-.5 .1-.1-.2M154.8 127.7l-.5 .1-.1 .8a.35 .35 0 0 0 .3 .3 .35 .35 0 0 0 .4-.3v-.2l-.3-.3-.4 .3M154.8 140l.3-.4v1.2M154.8 123.3v.8M154.9 135.3a.35 .35 0 0 1-.4 .3 .35 .35 0 0 1-.3-.3l.1-.4h.5v.8l-.2 .3h-.3M155 137.2a.68 .68 0 0 1 .5 .6 .68 .68 0 0 1-.5 .6l-.2-.2v-.8zM156.5 120.1l.4-1.1 .4 1.1M156.5 122.6l.4-1.2 .4 1.2M156.5 125l.4-1.2 .4 1.2"/>
<path d="M156.5 127.3l.4-1.1 .4 1.1M156.5 129.7l.4-1.2 .4 1.2M156.5 132.1l.4-1.2 .4 1.2M156.5 134.5l.4-1.2 .4 1.2M156.5 136.9l.4-1.2 .4 1.2M156.5 139.3l.4-1.2 .4 1.2M156.6 122.3h.6M156.6 124.6h.6M156.6 127h.6M156.6 129.4h.6M156.6 131.7h.6M156.6 134.1h.6"/>
<path d="M156.6 136.6h.6M156.6 138.9h.6M157.6 121.8l.4-.4v1.2M157.6 124.1l.4-.3v1.2M157.6 126.2h.8l-.5 1.1M157.6 135.7h.7l-.3 .4 .3 .1v.5l-.1 .2h-.4l-.2-.2M157.6 138.2h.7v.4l-.7 .7h.7M157.6 120.1h.7M157.6 122.6h.7M157.6 125h.7M158 133.3l-.4 .8h.8M158.2 128.5h-.2a.73 .73 0 0 0-.1 1.2l.4-.1v-.5l-.4-.2-.3 .3"/>
<path d="M158.2 133.7v.8M158.3 130.9h-.6l-.1 .6 .6-.1 .1 .6h-.7M158.8 123.9l.5-.1 .2 .3-.7 .9h.7M159.1 121.3l-.3 .9h.7M159.3 121.8v.8M166.1 120.1l.4-1.1 .4 1.1M166.1 122.6l.4-1.2 .4 1.2M166.1 127.3l.4-1.1 .4 1.1M166.1 134.5l.4-1.2 .4 1.2M166.1 139.3l.4-1.2 .4 1.2M166.2 122.3h.6M166.2 127h.6"/>
<path d="M166.2 134.1h.6M166.2 138.9h.6M166.7 123.7l-1 1.5M166.9 135.6l-1 1.6M167 123.8l.3 1.2 .3-.9 .1 .9 .4-1.2M167.2 121.8l.4-.4v1.2M167.2 126.5l.4-.3v1.1M167.2 129.7l.4-1.2 .5 1.2M167.2 132.1l.4-1.2 .5 1.2M167.2 133.6h.2l.2-.3v1.2M167.2 135.9l.2-.2h.4a.86 .86 0 0 1-.1 1.2l-.5-.2zM167.2 138.4l.4-.3v1.2"/>
<path d="M167.2 120.1h.7M167.2 122.6h.7M167.2 127.3h.7M167.2 134.5h.7M167.2 139.3h.7M167.4 129.4h.5M167.4 131.7h.5M168.3 121.4h.9l-.5 1.2M168.3 126.2h.8l-.4 .4 .4 .2-.1 .5h-.7M168.4 133.6l.3-.3v1.2M168.4 134.5h.7M168.5 138.2l.1-.1a.59 .59 0 0 1 .5 .4 .59 .59 0 0 1-.1 .6l-.2 .2-.3-.2z"/>
<path d="M168.5 124.3h.4M168.5 136.2h.4M168.7 129l-.3-.2a.35 .35 0 0 1 .3-.3 .35 .35 0 0 1 .4 .3l-.3 .2a.36 .36 0 0 0-.4 .4 .36 .36 0 0 0 .5 .3 .36 .36 0 0 0 .1-.6l-.2-.1M169.1 123.8h-.6v1.2h.6M169.1 131.4a.35 .35 0 0 1-.4 .3 .35 .35 0 0 1-.3-.3l.1-.4h.5v.8l-.2 .3h-.3M169.1 135.7h-.6v1.2h.6M170 126.8h7.1M170 131.6h7.1M170 129.2h7.1M170 136.3h7.1M170 133.9h7.1M170 122h7.1"/>
<path d="M170 124.4h7.1M170 138.7h7.1M170.3 120.5h.6l-.3 .5 .3 .1v.5h-.6M170.3 123l.1-.1h.4l.1 .1v.4l-.6 .7h.6M170.3 125.4h.6v.4l-.6 .7h.6M170.3 127.8h.6v.4l-.6 .7h.6M170.3 130.1h.6v.5l-.6 .6h.6M170.3 132.5h.6v.4l-.6 .7h.6M170.3 135l.1-.2h.4l.1 .2v.3l-.6 .7h.6M170.3 137.3l.1-.1h.4l.1 .1v.5l-.6 .6h.6M170.3 139.7h.6v.4l-.6 .7h.6M171.4 127.7h.7l-.5 1.2"/>
<path d="M171.4 137.2h.7l-.4 .5 .3 .1 .1 .4-.2 .2h-.4l-.1-.1M171.5 139.7l.5-.1 .1 .4-.7 .8h.7M171.6 125.8l-.1-.4 .5-.1 .1 .3-.2 .2-.4 .1v.4l.1 .2h.3l.2-.3v-.2l-.2-.2M171.7 120.5a.71 .71 0 0 1 .3 1.2h-.4l-.1-.2v-.8zM171.7 134.8l-.2 .8h.6M172 130l-.5 .3v.8h.5l.1-.4-.2-.2h-.3l-.1 .2M172 135.2v.8M172 132.4h-.5v.6l.5-.1 .1 .2v.3l-.1 .2-.5-.1M172.1 123.4l-.1 .2h-.5v-.6l.4-.1 .2 .2-.1 .9-.5 .1M173.8 126.3l.4-1.2 .4 1.2M173.8 121.5l.4-1.2 .4 1.2M173.8 128.7l.4-1.2 .4 1.2"/>
<path d="M173.8 122.8l.4 1.2 .1-.9 .3 .9 .2-1.2M173.8 133.4l.4-1.2 .4 1.2M173.8 131.1l.4-1.2 .4 1.2M173.8 138.3l.4-1.2 .4 1.2M173.8 139.1h3.2M173.8 122.4h3.3M173.8 134.4h3.2M173.9 126h.6M173.9 137.9h.6M173.9 130.7h.6M173.9 128.4h.6M173.9 133.1h.6"/>
<path d="M173.9 121.2h.6M174.2 134.6l.5 .2v.8l-.3 .3h-.2a.86 .86 0 0 1 0-1.3zM174.6 139.4h-.6l-.1 .2 .1 .4 .5 .1v.4h-.6M174.9 125.5l.4-.4v1.2M174.9 120.6l.4-.3v1.2M174.9 132.6l.4-.4v1.2M174.9 130.2l.4-.3v1.2M174.9 137.4l.4-.3v1.2M174.9 126.3h.7M174.9 121.5h.7M174.9 133.4h.7M174.9 131.1h.7"/>
<path d="M174.9 138.3h.7M175.2 135.2h.4M175.3 123.3h.5M175.6 128l-.4 .3-.2-.1-.1-.4a.35 .35 0 0 1 .4-.3 .35 .35 0 0 1 .3 .3l-.2 .8-.4 .1M175.8 139.5l-.5-.1a.67 .67 0 0 0-.3 .7 .67 .67 0 0 0 .5 .5l.3-.1M175.8 134.6h-.6v1.3h.6M175.9 122.8h-.6v1.2h.6M176.1 132.4l.4-.2 .3 .4-.8 .8h.8M176.1 137.4l.3-.3v1.2M176.1 138.3h.7M176.2 130l.2-.1a.64 .64 0 0 1 .4 .6 .64 .64 0 0 1-.4 .6l-.3-.3zM176.3 120.8l-.2-.1v-.2l.4-.2 .3 .3-.7 .4 .1 .5h.4l.2-.2v-.2l-.3-.3"/>
<path d="M176.3 135l.3-.4v1.3M176.3 135.9h.7M176.4 125.1l-.3 .8h.7M176.4 123.1l.3-.3v1.2M176.4 124h.6M176.6 125.5v.8M177 139.4l-.7 .1v.4l.7 .4-.3 .3-.4-.1M180.8 126.8h7.1M180.8 131.6h7.1M180.8 129.2h7.1M180.8 136.3h7.1M180.8 133.9h7.1"/>
<path d="M180.8 122h7.1M180.8 124.4h7.1M180.8 138.7h7.1M182.1 126.3l.4-1.2 .5 1.2M182.1 131.1l.4-1.2 .5 1.2M182.1 128.7l.4-1.2 .5 1.2M182.1 133.4l.4-1.2 .5 1.2M182.1 138.3l.4-1.2 .5 1.2M182.1 135.9l.4-1.3 .5 1.3M182.1 121.5l.4-1.2 .5 1.2M182.1 124l.4-1.2 .5 1.2M182.3 126h.5"/>
<path d="M182.3 137.9h.5M182.3 130.7h.5M182.3 128.4h.5M182.3 133.1h.5M182.3 135.5h.5M182.3 121.2h.5M182.3 123.6h.5M183.2 127.5h.8l-.5 1.2M183.2 137.1h.8l-.4 .4 .3 .1 .1 .4-.3 .3h-.3l-.2-.2M183.3 139.5l.5-.1 .2 .4-.8 .8h.8M183.3 120.6l.3-.3v1.2M183.3 123.1l.3-.3v1.2"/>
<path d="M183.3 121.5h.7M183.3 124h.7M183.5 125.6l-.2-.1 .1-.4h.4l.2 .2-.3 .3-.4 .1v.5l.2 .1h.2l.3-.2v-.3l-.3-.2M183.6 134.6l-.3 .9h.7M183.8 129.9l-.5 .2v.9h.6l.1-.4-.3-.3h-.2l-.2 .3M183.8 135v.9M183.9 132.2h-.6v.6h.5l.2 .1v.4l-.2 .1-.5-.1M184.3 122.8h.8l-.4 .4 .4 .2-.1 .5-.5 .1-.2-.2M185 120.3h-.5l-.1 .6 .6-.1v.7l-.6-.1M185.8 137.6l.3-.4v1.2M185.8 140l.3-.4v1.2M185.8 138.4h.6"/>
<path d="M186.3 120.5h.7l-.4 .5 .4 .1v.5h-.7M186.3 130h.8l-.5 1.2M186.6 122.9l-.2 .8h.7M186.6 132.9l-.2-.1v-.3h.6l-.1 .4-.5 .1v.6l.6-.1v-.4l-.1-.2M186.9 127.7l-.4 .1-.1 .8 .2 .3 .4-.1v-.5l-.1-.2h-.3l-.2 .3M186.9 140l.4-.4v1.2M186.9 123.3v.8M187 125.3h-.6v.5h.6v.5l-.1 .2h-.4l-.1-.2M187 135.3l-.1 .3-.5-.1v-.6l.5-.1 .1 .2v.7l-.1 .3h-.5M187.2 137.2a.68 .68 0 0 1 .4 .6 .68 .68 0 0 1-.4 .6l-.3-.5 .1-.6zM188.7 120.1l.4-1.1 .4 1.1M188.7 122.6l.4-1.2 .4 1.2"/>
<path d="M188.7 125l.4-1.2 .4 1.2M188.7 127.3l.4-1.1 .4 1.1M188.7 129.7l.4-1.2 .4 1.2M188.7 132.1l.4-1.2 .4 1.2M188.7 134.5l.4-1.2 .4 1.2M188.7 136.9l.4-1.2 .4 1.2M188.7 139.3l.4-1.2 .4 1.2M188.8 122.3h.6M188.8 124.6h.6M188.8 127h.6M188.8 129.4h.6M188.8 131.7h.6"/>
<path d="M188.8 134.1h.6M188.8 136.6h.6M188.8 138.9h.6M189.8 121.8l.4-.4v1.2M189.8 124.1l.4-.3v1.2M189.8 126.2h.8l-.5 1.1M189.8 135.7h.7l-.3 .4 .3 .1v.5l-.2 .2h-.3l-.2-.2M189.8 138.2h.7v.4l-.7 .7h.7M189.8 120.1h.7M189.8 122.6h.7M189.8 125h.7M190.2 133.3l-.4 .8h.8"/>
<path d="M190.4 128.5h-.2a.73 .73 0 0 0-.1 1.2l.4-.1v-.5l-.4-.2-.3 .3M190.4 133.7v.8M190.5 130.9h-.6l-.1 .6 .6-.1 .1 .6h-.7M191 123.9l.6-.1 .1 .3-.8 .9h.8M191.3 121.3l-.3 .9h.8M191.6 121.8v.8M198.3 120.1l.4-1.1 .4 1.1M198.3 122.6l.4-1.2 .4 1.2M198.3 127.3l.4-1.1 .4 1.1M198.3 134.5l.4-1.2 .4 1.2M198.3 139.3l.4-1.2 .4 1.2M198.5 122.3h.5"/>
<path d="M198.5 127h.5M198.5 134.1h.5M198.5 138.9h.5M199 123.7l-1 1.5M199.1 135.6l-1.1 1.6M199.2 123.8l.3 1.2 .2-.9 .3 .9 .2-1.2M199.5 121.8l.3-.4v1.2M199.5 126.5l.3-.3v1.1M199.5 129.7l.3-1.2 .4 1.2M199.5 132.1l.3-1.2 .4 1.2M199.5 133.6l.3-.3v1.2M199.5 138.4l.3-.3v1.2"/>
<path d="M199.5 120.1h.7M199.5 122.6h.7M199.5 127.3h.7M199.5 134.5h.7M199.5 139.3h.7M199.6 135.7h.4l.2 .2v.8l-.6 .2a.86 .86 0 0 1 0-1.2zM199.6 129.4h.6M199.6 131.7h.6M200.5 121.4h.8l-.5 1.2M200.5 126.2h.8l-.5 .4 .4 .1v.6h-.7M200.6 133.6l.3-.3v1.2M200.6 134.5h.7"/>
<path d="M200.7 138.2v-.1a.59 .59 0 0 1 .6 .4 .59 .59 0 0 1-.1 .6l-.2 .2-.3-.2zM200.7 124.3h.4M200.7 136.2h.4M200.8 129l-.2-.2a.35 .35 0 0 1 .3-.3 .35 .35 0 0 1 .4 .3l-.3 .2a.36 .36 0 0 0-.4 .4 .36 .36 0 0 0 .5 .3 .36 .36 0 0 0 .1-.6l-.2-.1M201.3 123.8h-.6v1.2h.6M201.3 131.4a.35 .35 0 0 1-.4 .3 .35 .35 0 0 1-.3-.3l.1-.4h.5v.8l-.2 .3h-.3M201.3 135.7h-.6v1.2h.6M202.2 126.8h7.2M202.2 131.6h7.2M202.2 129.2h7.2M202.2 136.3h7.2M202.2 133.9h7.2"/>
<path d="M202.2 122h7.2M202.2 124.4h7.2M202.2 138.7h7.2M202.4 120.5h.8l-.4 .5 .4 .2v.3l-.2 .2-.6-.1M202.5 123l.4-.1 .3 .4-.8 .8h.8M202.5 125.4l.5-.1 .2 .3-.8 .9h.8M202.5 127.8l.5-.1 .2 .3-.8 .9h.8M202.5 130.1l.4-.1 .3 .4-.8 .8h.8M202.5 132.5l.4-.1 .3 .4-.8 .8h.8M202.5 135l.4-.2 .3 .3-.8 .9h.8M202.5 137.3l.4-.1 .3 .4-.8 .8h.8M202.5 139.7l.5-.1 .2 .4-.8 .8h.8"/>
<path d="M203.5 127.7h.9l-.5 1.2M203.5 137.2h.8l-.4 .5 .4 .2-.1 .4-.5 .1-.2-.1M203.6 139.7l.6-.1 .1 .4-.8 .8h.8M203.9 120.5a.75 .75 0 0 1 .2 1.2h-.3l-.2-.5 .1-.6zM203.9 125.8l-.3-.2 .1-.3h.5v.4l-.5 .1-.1 .2v.2l.3 .3 .4-.3-.1-.4h-.2M203.9 134.8l-.3 .8h.8M204.2 130l-.4 .1-.2 .9a.35 .35 0 0 0 .4 .2 .35 .35 0 0 0 .3-.2l-.1-.4-.2-.1-.4 .2M204.2 132.4h-.5l-.1 .6 .6-.1v.7l-.6-.1M204.2 135.2v.8M204.3 123.4l-.1 .2h-.5l-.1-.2 .1-.5h.3l.2 .1a.85 .85 0 0 1-.2 1.1h-.3M206 121.5l.4-1.2 .4 1.2M206 126.3l.4-1.2 .4 1.2"/>
<path d="M206 131.1l.4-1.2 .4 1.2M206 128.7l.4-1.2 .4 1.2M206 133.4l.4-1.2 .4 1.2M206 138.3l.4-1.2 .4 1.2M206 139.1h3.2M206 122.4h3.3M206 134.4h3.2M206.1 122.8l.2 1.2 .3-.9 .2 .9 .3-1.2M206.1 126h.6M206.1 137.9h.6M206.1 130.7h.6M206.1 128.4h.6"/>
<path d="M206.1 133.1h.6M206.1 121.2h.6M206.2 134.8l.2-.2 .4 .1a.8 .8 0 0 1-.2 1.2h-.2a.79 .79 0 0 1-.2-1.1zM206.8 139.4h-.6l-.1 .2 .1 .4 .6 .1v.4l-.2 .1-.5-.1M207.1 120.6h.2l.1-.3v1.2M207.1 125.5l.3-.4v1.2M207.1 130.2l.3-.3v1.2M207.1 132.6h.2l.1-.4v1.2M207.1 137.4l.3-.3v1.2M207.1 126.3h.7M207.1 121.5h.7M207.1 133.4h.7"/>
<path d="M207.1 131.1h.7M207.1 138.3h.7M207.4 135.2h.4M207.5 123.3h.4M207.8 128l-.2 .3h-.3l-.2-.3 .1-.4h.6v.8l-.5 .3M207.9 139.5l-.5-.1-.1 .3v.8l.3 .1 .3-.1M207.9 134.6h-.5v1.3h.5M208.1 122.8h-.6v1.2h.6M208.3 132.4l.4-.2 .3 .4-.8 .8h.8M208.3 137.4l.3-.3v1.2M208.3 138.3h.7M208.4 130l.2-.1a.64 .64 0 0 1 .4 .6 .64 .64 0 0 1-.5 .6l-.2-.3z"/>
<path d="M208.4 120.8l-.1-.1v-.2l.4-.2 .3 .3-.7 .4 .1 .5h.4l.2-.2v-.2l-.3-.3M208.4 134.8l.5-.2 .2 .4-.7 .9h.7M208.5 122.9l.6-.1 .1 .5-.8 .7h.8M208.5 125.1l-.2 .8h.7M208.8 125.5v.8M209.1 139.4l-.7 .1v.4l.7 .4-.2 .3-.5-.1M212.9 126.8h7.2M212.9 131.6h7.2M212.9 129.2h7.2M212.9 136.3h7.2M212.9 133.9h7.2M212.9 122h7.2"/>
<path d="M212.9 124.4h7.2M212.9 138.7h7.2M214.4 124l.3-1.2 .4 1.2M214.4 121.5l.3-1.2 .4 1.2M214.4 133.4l.3-1.2 .4 1.2M214.4 135.9l.3-1.3 .4 1.3M214.4 138.3l.3-1.2 .4 1.2M214.4 126.3l.3-1.2 .4 1.2M214.4 131.1l.3-1.2 .4 1.2M214.4 128.7l.3-1.2 .4 1.2M214.5 126h.6M214.5 137.9h.6"/>
<path d="M214.5 130.7h.6M214.5 128.4h.6M214.5 133.1h.6M214.5 135.5h.6M214.5 121.2h.6M214.5 123.6h.6M215.4 137.1h.8l-.5 .4 .4 .1v.6l-.5 .1-.2-.2M215.4 127.5h.8l-.5 1.2M215.5 139.5l.6-.1 .1 .4-.8 .8h.8M215.5 123.1l.3-.3v1.2M215.5 120.6l.3-.3v1.2M215.5 121.5h.7"/>
<path d="M215.5 124h.7M215.7 134.6l-.2 .9h.7M215.7 125.6l-.2-.2 .1-.3h.5v.5h-.5l-.1 .2v.3l.2 .2 .5-.2-.1-.5h-.2M216.1 132.2h-.5l-.1 .6h.6v.6l-.6-.1M216.1 129.9l-.5 .1-.1 .8a.35 .35 0 0 0 .3 .3 .35 .35 0 0 0 .4-.3l-.1-.4-.2-.1-.4 .3M216.1 135v.9M216.6 122.8h.7l-.4 .4 .4 .1v.5l-.2 .2h-.4l-.1-.2M217.3 120.3h-.6l-.1 .6 .6-.1 .1 .6h-.7M218 137.6l.4-.4v1.2M218 140l.4-.4v1.2M218 138.4h.7M218.5 120.5h.7l-.3 .5 .3 .1v.5h-.7"/>
<path d="M218.5 130h.8l-.5 1.2M218.8 132.9l-.3-.1 .1-.3h.6l-.1 .4h-.3l-.3 .3 .2 .4 .5-.1v-.4l-.2-.2M218.9 122.9l-.4 .8h.8M219.1 127.7l-.4 .1-.2 .8 .3 .3 .4-.1v-.5l-.2-.2h-.2l-.3 .3M219.1 140l.4-.4v1.2M219.1 123.3v.8M219.2 125.3h-.6l-.1 .5h.7v.5l-.2 .2h-.3l-.2-.2M219.2 135.3v.2l-.4 .1-.3-.3v-.3l.3-.2 .4 .2v.7l-.2 .3h-.3M219.2 137.3l.2-.1a.68 .68 0 0 1 .4 .6 .68 .68 0 0 1-.4 .6l-.3-.5zM220.9 120.1l.4-1.1 .4 1.1M220.9 122.6l.4-1.2 .4 1.2M220.9 125l.4-1.2 .4 1.2"/>
<path d="M220.9 127.3l.4-1.1 .4 1.1M220.9 129.7l.4-1.2 .4 1.2M220.9 132.1l.4-1.2 .4 1.2M220.9 134.5l.4-1.2 .4 1.2M220.9 136.9l.4-1.2 .4 1.2M220.9 139.3l.4-1.2 .4 1.2M221.1 122.3h.5M221.1 124.6h.5M221.1 127h.5M221.1 129.4h.5M221.1 131.7h.5M221.1 134.1h.5"/>
<path d="M221.1 136.6h.5M221.1 138.9h.5M222 126.2h.8l-.5 1.1M222 135.7h.8l-.5 .4 .4 .1 .1 .5-.3 .2h-.3l-.2-.2M222.1 121.8l.3-.4v1.2M222.1 124.1l.3-.3v1.2M222.1 138.2l.5-.1 .2 .3-.8 .9h.8M222.1 120.1h.7M222.1 122.6h.7M222.1 125h.7M222.3 133.3l-.2 .8h.7M222.6 128.5l-.5 .3v.8h.6l.1-.4-.3-.3h-.2l-.2 .3"/>
<path d="M222.6 133.7v.8M222.7 130.9h-.6v.6l.5-.1 .2 .2v.3l-.2 .2-.5-.1M223.2 123.9l.6-.1 .1 .3-.8 .9h.8M223.4 121.3l-.2 .9h.7M223.8 121.8v.8M230.5 120.1l.4-1.1 .4 1.1M230.5 122.6l.4-1.2 .4 1.2M230.5 127.3l.4-1.1 .4 1.1M230.5 134.5l.4-1.2 .4 1.2M230.5 139.3l.4-1.2 .4 1.2M230.6 122.3h.6M230.6 127h.6"/>
<path d="M230.6 134.1h.6M230.6 138.9h.6M231.1 123.7l-1 1.5M231.2 135.6l-1 1.6M231.4 123.8l.3 1.2 .2-.9 .3 .9 .2-1.2M231.6 121.8l.4-.4v1.2M231.6 126.5l.4-.3v1.1M231.6 129.7l.5-1.2 .3 1.2M231.6 132.1l.5-1.2 .3 1.2M231.6 133.6l.4-.3v1.2M231.6 138.4l.4-.3v1.2M231.6 120.1h.7"/>
<path d="M231.6 122.6h.7M231.6 127.3h.7M231.6 134.5h.7M231.6 139.3h.7M231.7 135.7h.5a.77 .77 0 0 1-.1 1.2l-.4-.1a.87 .87 0 0 1 0-1.1zM231.7 129.4h.6M231.7 131.7h.6M232.7 121.4h.8l-.5 1.2M232.7 126.2h.7l-.3 .4 .3 .1v.6h-.7M232.7 133.6h.2l.2-.3v1.2M232.7 134.5h.7M232.9 138.1h.4l.1 .2v.7l-.2 .3a.71 .71 0 0 1-.3-1.2z"/>
<path d="M232.9 124.3h.4M232.9 136.2h.4M233 129l-.3-.2 .3-.3 .4 .1v.3a.51 .51 0 0 0-.6 .7h.6v-.5l-.1-.1M233.4 123.8h-.5v1.2h.5M233.4 131.4v.2l-.4 .1-.3-.3v-.3l.3-.2 .4 .2v.7l-.1 .3h-.4M233.4 135.7h-.5v1.2h.5M234.4 126.8h7.2M234.4 131.6h7.2M234.4 129.2h7.2M234.4 136.3h7.2M234.4 133.9h7.2M234.4 122h7.2"/>
<path d="M234.4 124.4h7.2M234.4 138.7h7.2M234.6 120.5h.8l-.4 .5h.3v.7l-.7-.1M234.7 123l.4-.1 .3 .4-.8 .8h.8M234.7 125.4l.6-.1 .1 .3-.8 .9h.8M234.7 127.8l.6-.1 .1 .3-.8 .9h.8M234.7 130.1l.4-.1 .3 .4-.8 .8h.8M234.7 132.5l.4-.1 .3 .4-.8 .8h.8M234.7 135l.4-.2 .3 .3-.8 .9h.8M234.7 137.3l.4-.1 .3 .4-.8 .8h.8M234.7 139.7l.6-.1 .1 .4-.8 .8h.8M235.8 127.7h.8l-.5 1.2"/>
<path d="M235.8 137.2h.7l-.4 .5 .4 .1v.5l-.2 .1h-.3l-.2-.1M235.8 139.7h.7v.4l-.7 .7h.7M236 120.6l.2-.1 .3 .2v.8l-.2 .2h-.3l-.2-.5zM236.1 125.8l-.3-.3 .2-.2h.4l.1 .3-.7 .4v.2l.3 .3 .4-.2v-.4l-.2-.1M236.1 134.8l-.3 .8h.8M236.4 130h-.3a.73 .73 0 0 0 0 1.2l.4-.1v-.5l-.4-.1-.3 .2M236.4 135.2v.8M236.5 123.4l-.1 .2h-.4l-.2-.2v-.3l.3-.2 .4 .1v.8l-.2 .2-.3 .1M236.5 132.4h-.6l-.1 .6 .6-.1 .1 .6h-.7M238.2 133.4l.4-1.2 .4 1.2M238.2 131.1l.4-1.2 .4 1.2M238.2 128.7l.4-1.2 .4 1.2"/>
<path d="M238.2 126.3l.4-1.2 .4 1.2M238.2 138.3l.4-1.2 .4 1.2M238.2 121.5l.4-1.2 .4 1.2M238.2 139.1h3.2M238.2 122.4h3.4M238.2 134.4h3.2M238.3 122.8l.2 1.2 .3-.9 .2 .9 .3-1.2M238.3 134.8l.5-.2a.86 .86 0 0 1 0 1.3h-.2l-.3-.3zM238.3 126h.5M238.3 137.9h.5M238.3 130.7h.5M238.3 128.4h.5"/>
<path d="M238.3 133.1h.5M238.3 121.2h.5M239 139.4l-.7 .1v.4l.7 .4-.2 .3-.5-.1M239.4 132.6l.3-.4v1.2M239.4 130.2l.3-.3v1.2M239.4 125.5l.3-.4v1.2M239.4 137.4l.3-.3v1.2M239.4 120.6l.3-.3v1.2M239.4 126.3h.6M239.4 121.5h.6M239.4 133.4h.6M239.4 131.1h.6"/>
<path d="M239.4 138.3h.6M239.6 135.2h.4M239.7 123.3h.4M240 128l-.2 .3-.4-.2v-.5l.4-.1a.73 .73 0 0 1-.1 1.2h-.3M240.2 134.6h-.6v1.3h.6M240.2 139.5l-.5-.1a.67 .67 0 0 0-.3 .7 .67 .67 0 0 0 .5 .5l.3-.1M240.3 122.8h-.6v1.2h.6M240.5 132.4l.4-.2 .2 .4-.7 .8h.7M240.5 137.4l.3-.3v1.2M240.5 138.3h.6M240.5 134.6h.8l-.4 .5h.3l.1 .2-.1 .5-.5 .1-.2-.2M240.5 130l.4-.1a.78 .78 0 0 1 0 1.2l-.4-.1z"/>
<path d="M240.7 125.1l-.2 .8h.7M240.7 120.8h-.2a.31 .31 0 0 1 .1-.4 .31 .31 0 0 1 .4 .1v.3h-.3l-.2 .3v.4h.5l.1-.2v-.2l-.2-.3M240.7 122.8h.7l-.4 .4 .4 .1v.5l-.2 .2h-.3l-.2-.2M241 125.5v.8M241.3 139.4h-.6v.6l.5 .1 .1 .3-.3 .2-.4-.1M245.1 126.8h7.2M245.1 131.6h7.2M245.1 129.2h7.2M245.1 136.3h7.2M245.1 133.9h7.2M245.1 122h7.2M245.1 124.4h7.2"/>
<path d="M245.1 138.7h7.2M246.5 135.9l.5-1.3 .3 1.3M246.5 138.3l.5-1.2 .3 1.2M246.5 131.1l.5-1.2 .3 1.2M246.5 128.7l.5-1.2 .3 1.2M246.5 133.4l.5-1.2 .3 1.2M246.5 126.3l.5-1.2 .3 1.2M246.5 121.5l.5-1.2 .3 1.2M246.5 124l.5-1.2 .3 1.2M246.6 126h.6M246.6 137.9h.6M246.6 130.7h.6"/>
<path d="M246.6 128.4h.6M246.6 133.1h.6M246.6 135.5h.6M246.6 121.2h.6M246.6 123.6h.6M247.7 139.5h.6v.5l-.6 .6h.6M247.7 137.1h.6l-.3 .4 .3 .1v.5l-.1 .2h-.4l-.1-.2M247.7 127.5h.7l-.5 1.2M247.7 120.6h.1l.2-.3v1.2M247.7 123.1l.3-.3v1.2M247.7 121.5h.6M247.7 124h.6"/>
<path d="M247.9 125.6l-.2-.3 .1-.2h.4l.1 .4-.6 .3v.3l.2 .2 .4-.1v-.5l-.1-.1M248 134.6l-.3 .9h.7M248.2 129.9h-.2a.73 .73 0 0 0-.1 1.2l.4-.1v-.5l-.4-.2-.2 .3M248.2 135v.9M248.3 132.2h-.6v.6h.5l.1 .5h-.6M248.8 122.8h.7l-.4 .4 .3 .1 .1 .4-.2 .3h-.4l-.1-.2M249.4 120.3h-.6v.6l.5-.1 .2 .2v.3l-.2 .2-.5-.1M250.2 137.6l.3-.4v1.2M250.2 140l.3-.4v1.2M250.2 138.4h.7M250.7 120.5h.8l-.5 .5 .5 .2v.3l-.2 .2-.6-.1M250.7 130h.8l-.5 1.2"/>
<path d="M251 132.9l-.2-.1v-.3h.6l.1 .3-.7 .3v.4l.5 .1 .2-.4-.3-.3M251 122.9l-.2 .8h.7M251.3 127.7h-.3l-.2 .2v.9h.6l.1-.4-.3-.3h-.2l-.2 .3M251.3 140l.3-.4v1.2M251.3 123.3v.8M251.4 125.3h-.6v.5h.6l.1 .4-.3 .3-.4-.2M251.5 135.3l-.3 .3-.4-.1v-.5l.4-.2a.81 .81 0 0 1 0 1.2h-.3M251.5 137.2h.2l.3 .2v.8l-.3 .2a.71 .71 0 0 1-.2-1.2zM253.2 120.1l.3-1.1 .4 1.1M253.2 122.6l.3-1.2 .4 1.2M253.2 125l.3-1.2 .4 1.2M253.2 127.3l.3-1.1 .4 1.1"/>
<path d="M253.2 129.7l.3-1.2 .4 1.2M253.2 132.1l.3-1.2 .4 1.2M253.2 134.5l.3-1.2 .4 1.2M253.2 136.9l.3-1.2 .4 1.2M253.2 139.3l.3-1.2 .4 1.2M253.2 122.3h.6M253.2 124.6h.6M253.2 127h.6M253.2 129.4h.6M253.2 131.7h.6M253.2 134.1h.6M253.2 136.6h.6"/>
<path d="M253.2 138.9h.6M254.2 126.2h.8l-.5 1.1M254.2 135.7h.7l-.4 .4 .3 .1v.6l-.5 .1-.1-.2M254.3 121.8l.3-.4v1.2M254.3 124.1l.3-.3v1.2M254.3 138.2l.5-.1 .1 .3-.7 .9h.7M254.3 120.1h.6M254.3 122.6h.6M254.3 125h.6M254.5 133.3l-.2 .8h.7M254.8 128.5l-.4 .1-.1 .9a.35 .35 0 0 0 .3 .2 .35 .35 0 0 0 .3-.2l-.1-.5-.1-.1-.4 .3M254.8 130.9h-.5v.6l.5-.1v.7l-.5-.1"/>
<path d="M254.8 133.7v.8M255.4 123.9h.6v.4l-.6 .7h.6M255.7 121.3l-.3 .9h.7M255.9 121.8v.8M262.7 120.1l.4-1.1 .4 1.1M262.7 122.6l.4-1.2 .4 1.2M262.7 127.3l.4-1.1 .4 1.1M262.7 134.5l.4-1.2 .4 1.2M262.7 139.3l.4-1.2 .4 1.2M262.8 122.3h.6M262.8 127h.6M262.8 134.1h.6"/>
<path d="M262.8 138.9h.6M263.3 123.7l-1 1.5M263.5 135.6l-1.1 1.6M263.7 123.8l.2 1.2 .3-.9 .1 .9 .4-1.2M263.8 121.8l.4-.4v1.2M263.8 126.5l.4-.3v1.1M263.8 129.7l.4-1.2 .5 1.2M263.8 132.1l.4-1.2 .5 1.2M263.8 133.6h.2l.2-.3v1.2M263.8 138.4l.4-.3v1.2M263.8 120.1h.7M263.8 122.6h.7"/>
<path d="M263.8 127.3h.7M263.8 134.5h.7M263.8 139.3h.7M264 135.7h.4a.86 .86 0 0 1-.1 1.2l-.5-.2v-.8zM264 129.4h.5M264 131.7h.5M264.9 121.4h.8l-.5 1.2M264.9 126.2h.8l-.4 .4 .4 .2-.1 .5h-.7M265 133.6l.3-.3v1.2M265 138.3l.2-.2a.6 .6 0 0 1 .6 .4 .6 .6 0 0 1-.3 .7l-.2 .1-.3-.3zM265 134.5h.7M265.1 124.3h.4"/>
<path d="M265.1 136.2h.4M265.2 129l-.2-.1v-.3h.6v.3l-.6 .2v.5l.2 .1h.2l.3-.2-.3-.5M265.7 123.8h-.6v1.2h.6M265.7 131.4l-.3 .3-.4-.1v-.5l.4-.2a.81 .81 0 0 1 0 1.2h-.3M265.7 135.7h-.6v1.2h.6M266.6 126.8h7.1M266.6 131.6h7.1M266.6 129.2h7.1M266.6 136.3h7.1M266.6 133.9h7.1M266.6 122h7.1M266.6 124.4h7.1"/>
<path d="M266.6 138.7h7.1M266.8 120.5h.7l-.4 .5 .4 .1v.5h-.7M266.9 123l.1-.1h.4l.1 .1v.4l-.7 .7h.7M266.9 125.4l.6-.1v.5l-.7 .7h.7M266.9 127.8l.6-.1v.5l-.7 .7h.7M266.9 130.1h.6v.5l-.7 .6h.7M266.9 132.5h.6v.4l-.7 .7h.7M266.9 135l.1-.2h.4l.1 .2v.3l-.7 .7h.7M266.9 137.3l.1-.1h.4l.1 .1v.5l-.7 .6h.7M266.9 139.7l.6-.1v.5l-.7 .7h.7M268 127.7h.7l-.5 1.2M268 137.2h.7l-.4 .5 .3 .1 .1 .4-.2 .2h-.4l-.1-.1"/>
<path d="M268.1 139.7l.5-.1 .1 .4-.7 .8h.7M268.2 125.8l-.1-.4 .5-.1 .1 .3-.2 .2-.4 .1v.4l.1 .2h.3l.2-.3v-.2l-.2-.2M268.3 120.5a.71 .71 0 0 1 .3 1.2h-.4l-.1-.2v-.8zM268.3 134.8l-.2 .8h.6M268.6 130l-.5 .3v.8h.5l.1-.4-.2-.2h-.3l-.1 .2M268.6 135.2v.8M268.6 132.4h-.5v.6l.5-.1 .1 .2v.3l-.1 .2-.5-.1M268.7 123.4l-.1 .2h-.5v-.6l.4-.1 .2 .2-.1 .9-.5 .1M270.3 128.7l.5-1.2 .4 1.2M270.3 126.3l.5-1.2 .4 1.2M270.3 131.1l.5-1.2 .4 1.2M270.3 138.3l.5-1.2 .4 1.2"/>
<path d="M270.3 133.4l.5-1.2 .4 1.2M270.3 121.5l.5-1.2 .4 1.2M270.4 122.8l.4 1.2 .1-.9 .3 .9 .2-1.2M270.4 139.1h3.2M270.4 122.4h3.3M270.4 134.4h3.2M270.5 134.8l.3-.2 .5 .2v.8l-.3 .3h-.2l-.3-.3zM270.5 126h.6M270.5 137.9h.6M270.5 130.7h.6M270.5 128.4h.6M270.5 133.1h.6"/>
<path d="M270.5 121.2h.6M271.2 139.4l-.7 .1v.4l.7 .4-.3 .3-.4-.1M271.5 125.5l.4-.4v1.2M271.5 130.2l.4-.3v1.2M271.5 137.4l.4-.3v1.2M271.5 132.6l.4-.4v1.2M271.5 120.6l.4-.3v1.2M271.5 126.3h.7M271.5 121.5h.7M271.5 133.4h.7M271.5 131.1h.7M271.5 138.3h.7"/>
<path d="M271.8 135.2h.4M271.9 123.3h.4M272.2 128l-.4 .3-.2-.1-.1-.4a.35 .35 0 0 1 .4-.3 .35 .35 0 0 1 .3 .3l-.2 .8-.4 .1M272.4 134.6h-.6v1.3h.6M272.4 139.5l-.5-.1a.67 .67 0 0 0-.3 .7 .67 .67 0 0 0 .5 .5l.3-.1M272.5 122.8h-.6v1.2h.6M272.6 137.4l.4-.3v1.2M272.6 132.4l.2-.2h.3l.2 .2v.4l-.7 .6h.7M272.6 138.3h.7M272.8 130l.3-.1 .2 .2v.7l-.3 .3a.7 .7 0 0 1-.2-1.1zM272.9 120.8l-.3-.2 .3-.3h.2l.2 .4-.4 .1-.3 .3 .2 .4 .5-.1v-.4l-.2-.2M273 125.1l-.4 .8h.8"/>
<path d="M273.1 134.6l-.3 .9h.8M273.2 122.7l-.2 .8h.6M273.2 125.5v.8M273.4 135v.9M273.5 139.4h-.5l-.2 .2 .2 .4 .5 .1v.4l-.2 .1-.5-.1M273.5 123.1v.9M278 132.6l-.3-.2a.65 .65 0 0 0-.5 .7 .65 .65 0 0 0 .5 .6l.3-.2M18.5 156.5h1.8M29.3 144.5h.8v.3h-.8zM29.3 147h.8v.2h-.8zM29.3 149.4h.8v.2h-.8zM29.3 151.7h.8v.3h-.8z"/>
<path d="M29.3 154.1h.8v.2h-.8zM29.3 156.5h.8v.2h-.8zM29.3 158.8h.8v.3h-.8zM30.1 144.7h16.1l.4-.9 .7 1.8 .7-1.8 .8 1.8 .6-1.8 .8 1.8 .3-.9h9.2M30.1 147.1h11.1M30.1 149.4h11.1M30.1 151.8h15.9M30.1 154.2h11.1M30.1 156.6h11.1M30.1 159h11.1M31.9 143.5l.4-.3v1.2M31.9 145.6h.7v.4l-.7 .7h.7"/>
<path d="M31.9 147.9h.7l-.3 .5 .3 .1v.5h-.7M31.9 157.5h.8l-.5 1.2M31.9 144.4h.7M32.3 150.3l-.4 .8h.8M32.5 155.1l-.4 .1a.82 .82 0 0 0 .1 1.1l.4-.2v-.5l-.4-.1-.3 .3M32.5 150.7v.8M32.6 152.7h-.6l-.1 .5h.7v.6l-.2 .1h-.3l-.2-.1M35.5 156.1l.4-1.2 .3 1.2M35.5 153.8l.4-1.2 .3 1.2M35.5 142.7h5.1M35.5 157h3.2M35.6 155.8h.6"/>
<path d="M35.6 153.4h.6M35.6 143.6h.6v-.5l-.6-.1v1.2M35.6 148.4l.6-.1v-.5l-.6-.1v1.2M35.6 150.9h1M35.9 143.6l.4 .6M35.9 148.4l.4 .5M36.1 150.5v.9M36.3 157.4a.55 .55 0 0 0-.7 .5 .55 .55 0 0 0 .7 .5M36.5 145.4l-1 1.5M36.5 159.7l-1 1.5M36.6 155.3l.3-.4v1.2M36.6 152.7h.7v.4l-.7 .7h.7"/>
<path d="M36.6 156.1h.7M36.7 147.4h1.1M36.7 147.7l.3 1.2 .3-.8 .1 .8 .4-1.2M36.8 143.6h.5M36.9 145.4a.66 .66 0 0 1 .7 .4 .66 .66 0 0 1-.3 .8h-.4zM36.9 150.2l.4 1.2 .5-1.2M36.9 159.7v1.2M37.4 143h-.6v1.2h.6M37.4 157.4l-.4-.1-.3 .3 .3 .3 .4 .2v.3h-.7M37.8 152.7l.1-.1a.6 .6 0 0 1 .6 .4 .6 .6 0 0 1-.2 .7l-.3 .1-.2-.3zM37.8 157.3h.8l-.4 .4 .4 .3-.1 .4h-.7M37.9 145.4h.7"/>
<path d="M38.1 150.7h.6v-.5h-.6v1.2h.5l.3-.4-.4-.3M38.2 148.3h.4M38.3 145.4v1.2M38.4 155.4l-.2 .3h-.3l-.1-.2v-.5l.4-.1 .2 .3-.1 .8-.5 .1M38.5 143.1l-.4-.1-.3 .3 .1 .2 .6 .3v.3h-.7M38.7 159.9l.2-.2 .5 .2v.8l-.2 .2h-.3a.74 .74 0 0 1-.2-1zM38.8 147.7h-.6v1.2h.6M38.9 146.6l.3-1.2 .4 1.2M38.9 146.2h.6M38.9 155.5h.5M38.9 153.1h.5M39 143.6h.5"/>
<path d="M39.5 154.9h-.6v1.2h.6M39.5 152.6h-.6v1.2h.6M39.6 143h-.6v1.2h.6M40 143h.6M40.3 143v1.2M40.4 159.7l-.4 .1-.1 .2v.8l.5 .1 .2-.2v-.3l-.2-.2h-.4l-.1 .2M40.7 145.5l-.2-.1a.67 .67 0 0 0-.5 .5 .67 .67 0 0 0 .2 .7l.5-.1M41.2 145.4v1.2M41.4 145.9l.5 .7M41.9 145.4l-.7 .6M46.1 140.5h.4l.2 .3-.7 .8h.7M47.2 141.6h.1"/>
<path d="M47.7 140.5h.7l-.5 1.1M48.9 140.5v1.1M49 141.2l.4 .4M49.4 140.9l-.5 .4M49.9 141.6h.2v-.2l-.2-.2v-.6l.3-.1 .5 .1v.6l-.2 .2v.2h.2M52.2 157.2l-.2-.1a.61 .61 0 0 0-.4 .7 .61 .61 0 0 0 .5 .5l.2-.1v-.4h-.2M53.2 153v1.2h1.2l-1.2 1.2-1.2-1.2h1.2M53.2 153h.1M53.2 144.7v5.5M53.2 151.1v1.9M53.5 157.1v1.2l-.7-1.2v1.2M54.1 157.1a.6 .6 0 0 1 .7 .6 .6 .6 0 0 1-.7 .6z"/>
<path d="M55.2 143.5l.3-.3v1.2M55.2 144.4h.7M56.5 151.2h-.4l-.1 .3v.8h.5l.1-.4a.35 .35 0 0 0-.4-.3 .35 .35 0 0 0-.3 .3M56.6 148.9l-.5-.1a.67 .67 0 0 0-.2 .7 .67 .67 0 0 0 .5 .5l.2-.1M57.1 152.2v.2M57.3 149.4l-.2-.3 .1-.3h.5v.5l-.5 .1-.1 .1 .1 .4 .1 .1 .4-.2v-.4h-.2M57.8 151.7l-.2-.2 .1-.3h.5v.4l-.5 .1-.1 .2 .1 .4 .1 .1 .5-.3-.1-.4h-.2M58.8 151.6h.3l.3 .2v.3l-.3 .3-.3-.1M58.8 151.6v1.1M59.7 145.3l1.8 1.8v3.5h19.1M59.9 151.7h.4M59.9 141.5v-.8l.6 .4v-.3l.5-.1 .2 .3v.3l-.2 .2"/>
<path d="M59.9 155.5h1M60.3 146.3l.5-.4 .5 .9zM60.5 151.2h-.6v1.2M60.5 155v1M61.2 147.9v.8l-.8-.8-.5 .3 .2 .4M61.5 157.8v9.5M61.5 157.8l-.7 1.2M61.5 157.8l.7 1.2M62 154.8h-.5l-.1 .6 .2-.2 .4 .1v.6h-.6M62.4 154.8l.4 1.2 .4-1.2M64.3 145.8l.6-.1v-.3l-.2-.2h-.4v1.2h.6v-.4l-.2-.2M64.3 143l.2-.2a.6 .6 0 0 1 .5 .6 .6 .6 0 0 1-.5 .6l-.3-.4z"/>
<path d="M64.4 143.8h.3l.4 .3M65.4 143.2l.4-.4v1.2M65.4 144h.7M66.1 145.4l-.3-.2-.4 .3v.6l.2 .3 .5-.1M66.8 145.7l-.2-.1v-.2l.5-.2 .2 .3-.7 .4 .1 .5h.4l.2-.2v-.2l-.2-.3M68 145.2l-.3 .8h.8M68.3 145.6v.8M68.8 145.2h.8l-.5 1.2M79.1 155.5h.8M79.5 155v1M79.6 149.1h.7l-.4 .5 .4 .2v.3l-.1 .2-.6-.1M80.6 157.8v9.5"/>
<path d="M80.6 157.8l-.8 1.2M80.6 157.8l.7 1.2M81.1 154.8h-.6l-.1 .6 .2-.2h.3l.2 .2v.5h-.7M81.4 154.8l.5 1.2 .4-1.2M82 144h.8l-.5 1.2M83.5 143.9l-.3 1h.8M83.8 144.4v.8M83.9 141.6v1l.3 .2 .4-.1v-1.1M84.4 144v1.2M84.4 144.6h.7M85.1 142l.3-.4v1.2M85.1 144v1.2"/>
<path d="M85.1 142.8h.8M86.2 142.8l.3-1.2 .5 1.2M86.3 142.5h.6M86.4 144.1l-.3-.1a.67 .67 0 0 0-.5 .5 .67 .67 0 0 0 .3 .7l.5-.1M87 144.1l.2-.1 .3 .3v.7l-.2 .2-.3-.1a.78 .78 0 0 1 0-1zM88.1 144.1l.2-.1a.84 .84 0 0 1 .2 1.2h-.4l-.1-.2zM88.9 153h10.8M88.9 148.3h10.8M90.3 151.9l.4-.4v1.2M90.3 146.8h.7v.4l-.7 .7h.7M90.3 152.7h.7M92.7 152.6l.4-1.2 .4 1.2"/>
<path d="M92.7 146.2h5.2M92.8 152.2h.6M92.9 147.2h.6v-.6h-.6v1.1M93.1 147.2l.5 .5M93.7 144.7h10M93.8 151.5h.7v.4l-.7 .7h.7M94.1 147.2h.4M94.7 146.6h-.6v1.1h.6M95 151.6l.2-.2a.59 .59 0 0 1 .5 .3 .59 .59 0 0 1-.1 .7l-.3 .2-.3-.3zM95.8 146.6h-.5l-.2 .2 .1 .3 .6 .2v.4h-.7M96.3 147.2h.4M96.4 143.6h.6l.1-.5-.7-.1v1.2"/>
<path d="M96.8 143.6l.3 .6M96.9 146.6h-.6v1.1h.6M97.2 146.6h.7M97.5 142.7h1.1M97.5 143l.3 1.2 .2-.9 .3 .9 .3-1.2M97.5 146.6v1.1M98.1 155.5h1M98.6 155v1M99.7 157.8l-.7 1.2M99.7 157.8l.6 1.2M99.7 157.8v9.5M100.2 154.8h-.6v.6l.4-.2 .2 .2v.5h-.6"/>
<path d="M100.6 154.8l.3 1.2 .4-1.2M100.8 143.5l.3-.3v1.2M100.8 144.4h.6M102 143.3l.3-.1a.64 .64 0 0 1 .3 .6 .64 .64 0 0 1-.4 .6l-.3-.3zM105.2 158.7l.4-.4v1.2M105.2 159.5h.7M106.2 156.3l-.5-.1-.2 .3v.6a.45 .45 0 0 0 .7 .2M106.5 158.4l.3-.1 .2 .3v.7l-.2 .2-.3-.1a.78 .78 0 0 1 0-1zM106.7 156.5l.3-.3v1.2M106.7 157.4h.7M107.6 158.4l.3-.1a.84 .84 0 0 1 .1 1.2h-.3l-.2-.2zM107.8 156.5l.3-.3v1.2"/>
<path d="M107.8 157.4h.7M108.7 158.8l.4-.1 .1 .8M108.7 158.7v.8M109.8 158.9h.4M110.3 158.3h-.5v1.2M112.1 141.3l-.3-.2 .1-.3h.5v.4l-.5 .1-.1 .2v.2l.3 .3 .4-.3-.1-.4h-.1M116.3 153h8.4M116.3 148.3h8.4M116.3 150.6h8.4M116.3 155.4h8.4M116.3 157.8h8.4M116.6 154.9l.3-1.1 .4 1.1"/>
<path d="M116.6 150.2l.3-1.3 .4 1.3M116.6 152.6l.3-1.2 .4 1.2M116.6 157.3l.3-1.2 .4 1.2M116.6 159.7l.3-1.2 .4 1.2M116.6 146.2h2M116.7 152.2h.6M116.7 157h.6M116.7 154.6h.6M116.7 149.8h.6M116.7 159.3h.6M117.4 146.7l-.2-.1a.67 .67 0 0 0-.5 .5 .67 .67 0 0 0 .2 .6h.5M117.6 158.5h.8l-.5 .4 .5 .3-.1 .5-.7-.1"/>
<path d="M117.7 154.1l.3-.3v1.1M117.7 156.2l.4-.1 .3 .4-.8 .8h.8M117.7 154.9h.7M117.8 151.5l.1-.1a.59 .59 0 0 1 .5 .3 .59 .59 0 0 1-.1 .7l-.2 .2-.3-.2zM117.9 148.9l-.2 .9h.7M118.3 149.4v.8M118.5 146.6h-.4l-.2 .2v.3l.5 .1v.5h-.5M122 156.6l.3-.3v1.2M122 159l.3-.3v1.2M122 157.5h.7M122 159.9h.7M122.5 146.7h.8l-.4 .5 .4 .2v.3l-.2 .2-.6-.1"/>
<path d="M122.5 151.5h.8l-.5 1.2M122.6 144.7l.3-.3v1.1M122.6 145.5h.7M123.1 156.6l.3-.3v1.2M123.1 158.7h.7l-.4 .4 .4 .2v.5h-.7M123.1 157.5h.7M123.2 149.1h-.6v.6l.5-.1 .2 .2v.3l-.2 .2-.5-.1M123.3 154.4l-.2 .2h-.4l-.1-.6 .5-.1 .2 .2-.2 .8-.4 .2M124.7 145.7h1.2v.3h-1.2zM124.7 148.2h1.2v.1h-1.2zM124.7 150.5h1.2v.3h-1.2zM124.7 152.9h1.2v.3h-1.2z"/>
<path d="M124.7 155.3h1.2v.2h-1.2zM124.7 157.6h1.2v.3h-1.2zM124.7 145.9h-11.9v41.7h28.6v-25h-11.9M126 141.7l-.4-.1-.3 .3 .1 .3 .5 .1v.4h-.6M127.2 141.7a.55 .55 0 0 0-.8 .5 .55 .55 0 0 0 .8 .5M128.3 145.7h1.2v.3h-1.2zM128.3 148.2h1.2v.1h-1.2zM128.3 150.5h1.2v.3h-1.2zM128.3 152.9h1.2v.3h-1.2zM128.3 155.3h1.2v.2h-1.2zM128.3 157.6h1.2v.3h-1.2zM128.3 141.7l-.5-.1-.2 .3 .2 .3 .5 .2v.3h-.7"/>
<path d="M128.8 141.6v1.2M129.5 148.3h4.7M129.5 150.6h4.7M129.5 145.9h10.7M129.5 155.4h14.3v16.7h3.8M129.5 157.8h9.5M130.4 154.3l.3-.4v1.2M130.4 156.6l.3-.3v1.2M130.4 159l.3-.3v1.2M130.4 157.5h.7M130.4 159.9h.7M130.4 155.1h.7"/>
<path d="M130.9 144.4h.7v.5l-.7 .6h.7M131.1 152.1l-.2-.4 .2-.2h.3l.2 .4-.7 .3v.3l.2 .2 .5-.1v-.5h-.2M131.2 146.6l-.3 1h.8M131.5 149.1l-.4 .2-.2 .8 .2 .2 .5-.1-.1-.6h-.4l-.2 .2M131.5 156.4l.6-.1 .1 .3-.8 .9h.8M131.5 147.2v.7M131.7 153.9a.59 .59 0 0 1 .5 .4 .59 .59 0 0 1-.1 .6l-.2 .2a.75 .75 0 0 1-.2-1.2zM131.7 158.6l-.2 .8h.7M132.1 159.1v.8M134.5 159.7l.4-1.2 .3 1.2M134.5 155.8h5.1M134.5 159.3h.6"/>
<path d="M134.6 156.7h.6v-.5l-.6-.1v1.2M134.9 156.7l.4 .6M135.8 156.7h.4M136.2 158.5h-.6v.6l.1-.2h.4l.1 .2v.5h-.6M136.4 156.1h-.6v1.2h.6M137 144.8h.6v-.5l-.6-.1v1.2M137.2 144.8l.5 .6M137.5 156.2h-.6v.4l.5 .2 .1 .3-.3 .2-.4-.1M138 143.8h1.2M138 156.7h.4M138.1 144.2l.2 1.2 .3-.9 .3 .9 .2-1.2M138.6 156.1h-.6v1.2h.6"/>
<path d="M138.9 156.1h.7M139.3 156.1v1.2M148.5 155.4v1.2h1.3l-1.3 1.2-1.2-1.2h1.2M148.5 155.4h.1M148.5 148.3h7.2M148.5 150.6h7.2M148.5 141.1h7.2M148.5 143.5h7.2M148.5 145.9h7.2M149.9 143l.5-1.2 .3 1.2M149.9 140.6l.5-1.2 .3 1.2M150 142.7h.6"/>
<path d="M150 140.3h.6M150.1 144.2a.66 .66 0 0 1 .7 .4 .66 .66 0 0 1-.3 .8h-.4zM150.1 148.9a.64 .64 0 0 1 .7 .7 .64 .64 0 0 1-.7 .6zM150.1 146.6a.66 .66 0 0 1 .7 .4 .66 .66 0 0 1-.3 .7h-.4zM151 155.3h-.5a.67 .67 0 0 0-.2 .7 .67 .67 0 0 0 .5 .5l.2-.2v-.3h-.2M151 142.2l.4-.4v1.2M151 143h.7M151.2 149.1l.2-.2h.3l.2 .2v.3l-.7 .8h.7M151.2 146.9h.2l.2-.3v1.1M151.2 147.7h.7M151.4 144.3l.2-.1 .3 .2-.1 .9-.4 .1a.94 .94 0 0 1 0-1.1zM152.2 155.3v1.2l-.6-1.2v1.2"/>
<path d="M152.8 155.3h.4a.66 .66 0 0 1 .3 .7 .66 .66 0 0 1-.7 .5zM153.6 142.3l.3-.3v1.2M153.6 144.7l.3-.3v1.1M153.6 147.1h.2l.1-.4v1.2M153.6 149.4h.2l.1-.3v1.2M153.6 151.9l.3-.4v1.2M153.6 152.7h.7M153.6 140.8h.7M153.6 143.2h.7M153.6 145.5h.7M153.6 147.9h.7M153.6 150.3h.7"/>
<path d="M154.7 144.4h.7l-.4 .4 .4 .2v.5h-.7M154.8 142.1l.5-.1 .1 .3-.7 .9h.7M154.8 140.8h.6M155 146.6l-.2 1h.6M155.3 151.5l-.4 .1-.1 .2v.8l.4 .1 .2-.2v-.3l-.2-.2-.4 .1v.1M155.3 147.2v.7M155.4 149.1h-.6v.6l.5-.1 .1 .2v.3l-.1 .2-.5-.1M155.7 153h-7.2v2.4M156.5 141.6l.4-1.1 .4 1.1M156.5 144l.4-1.2 .4 1.2M156.6 141.3h.6M156.6 143.7h.6"/>
<path d="M156.7 145.2a.66 .66 0 0 1 .7 .4 .66 .66 0 0 1-.3 .8h-.4zM156.7 147.6a.66 .66 0 0 1 .7 .4 .66 .66 0 0 1-.3 .8h-.4zM156.7 150h.4a.66 .66 0 0 1 .3 .8 .66 .66 0 0 1-.7 .4zM157.3 152.4h-.4a.67 .67 0 0 0-.3 .7 .67 .67 0 0 0 .5 .5l.3-.2v-.3h-.3M157.6 140.8l.4-.3v1.1M157.6 141.6h.7M157.8 142.9l.3-.1 .2 .3v.7l-.3 .2a.7 .7 0 0 1-.2-1.1zM157.8 147.9h.2l.2-.3v1.2M157.8 150.1h.7v.4l-.7 .7h.7M157.8 148.8h.7M158 145.3l.2-.1 .3 .3v.7l-.2 .2h-.3l-.2-.4zM158.6 152.4v1.2l-.7-1.2v1.2"/>
<path d="M159.2 152.4h.4a.66 .66 0 0 1 .2 .8 .66 .66 0 0 1-.6 .4zM166.9 140.4l-1 1.5M167.2 142.8h.4l.3 .3v.7l-.3 .2h-.4zM167.2 145.2h.4l.3 .3v.6l-.2 .3h-.5zM167.2 147.6h.4l.3 .3v.6l-.2 .3h-.5zM167.2 150h.5l.2 .3v.6l-.3 .3h-.4zM167.2 152.4h.5l.2 .3v.5l-.3 .4h-.4zM168 140.5a.55 .55 0 0 0-.8 .6 .55 .55 0 0 0 .8 .5M168.3 142.8h.9l-.5 1.2M168.3 152.4h.8l-.4 .4 .4 .3-.1 .4-.5 .1-.2-.2M168.5 141.1h.4M168.7 149.9l-.3 .9h.8"/>
<path d="M169 145.2h-.3a.93 .93 0 0 0-.2 1.2h.5l.1-.5-.1-.2h-.5l-.1 .2M169 147.6h-.5l-.1 .6 .6-.1v.7l-.6-.1M169 150.4v.8M169.1 140.5h-.6v1.1h.6M170 153h7.1M170 148.3h7.1M170 150.6h7.1M170 141.1h7.1M170 143.5h7.1M170 145.9h7.1M170.3 142.1h.6v.4l-.6 .7h.6M170.3 144.4h.6v.5l-.6 .6h.6"/>
<path d="M170.3 147.1h.1l.2-.4v1.2M170.3 149.4h.1l.2-.3v1.2M170.3 151.9l.3-.4v1.2M170.3 152.7h.6M170.3 147.9h.6M170.3 150.3h.6M171.4 151.5h.7l-.5 1.2M171.5 142.3l.3-.3v1.2M171.5 143.2h.6M171.5 144.4h.3a.64 .64 0 0 1 .4 .6 .64 .64 0 0 1-.5 .5l-.2-.2zM171.6 149.6l-.1-.1v-.2l.4-.2 .2 .3-.6 .4v.5h.5l.1-.2v-.2l-.2-.3M172.1 147.2l-.2 .3-.4-.1v-.6l.4-.1 .2 .3-.1 .8-.5 .1"/>
<path d="M174 144.2a.66 .66 0 0 1 .6 .4 .66 .66 0 0 1-.2 .8h-.4zM174 141.8a.6 .6 0 0 1 .7 .6 .6 .6 0 0 1-.7 .6zM174 148.9a.64 .64 0 0 1 .7 .7 .64 .64 0 0 1-.7 .6zM174 151.4h.4a.66 .66 0 0 1 .2 .7 .66 .66 0 0 1-.6 .5zM174 146.6a.66 .66 0 0 1 .6 .4 .66 .66 0 0 1-.2 .7h-.4zM175 141.8h.9l-.6 1.2M175 151.4h.8l-.5 .4 .5 .1v.5l-.3 .2h-.3l-.2-.2M175.3 148.9l-.2 .9h.8M175.7 144.2l-.4 .1-.2 .8 .1 .3 .6-.1-.1-.6-.4-.1-.2 .3M175.7 149.4v.8M175.8 146.6h-.6l-.1 .6 .6-.1 .1 .6h-.7M179.8 159.6l-.1-.1a.66 .66 0 0 0-.5 .5 .66 .66 0 0 0 .2 .7l.5-.1v-.4h-.2"/>
<path d="M180.8 155.4v1.2h1.1l-1.1 1.2-1.2-1.2h1.2M180.8 155.4h.1M180.8 148.3h7.1M180.8 150.6h7.1M180.8 141.1h7.1M180.8 143.5h7.1M180.8 145.9h7.1M181.1 159.5v1.2l-.7-1.2v1.2M181.6 159.5a.66 .66 0 0 1 .7 .4 .66 .66 0 0 1-.2 .8h-.5zM182.1 140.6l.4-1.2 .5 1.2M182.1 143l.4-1.2 .5 1.2M182.3 146.6h.3l.4 .3v.6l-.2 .2h-.5z"/>
<path d="M182.3 148.9l.5 .1 .2 .3v.6l-.4 .3h-.3zM182.3 144.2h.3l.4 .2v.7l-.2 .3h-.5zM182.3 142.7h.5M182.3 140.3h.5M183.3 142.2l.3-.4v1.2M183.3 143h.7M183.5 146.9l.3-.3v1.1M183.5 149.1l.4-.2 .3 .4-.8 .9h.8M183.5 147.7h.7M183.6 144.3l.2-.1a.77 .77 0 0 1 .2 1.2h-.4l-.1-.3zM185.8 142.3l.3-.3v1.2M185.8 144.7l.3-.3v1.1"/>
<path d="M185.8 147.1h.1l.2-.4v1.2M185.8 149.4h.1l.2-.3v1.2M185.8 151.9l.3-.4v1.2M185.8 152.7h.6M185.8 140.8h.6M185.8 143.2h.6M185.8 145.5h.6M185.8 147.9h.6M185.8 150.3h.6M186.9 144.4h.7l-.4 .4 .4 .2-.1 .5h-.6M186.9 142.1l.6-.1 .1 .3-.7 .9h.7M186.9 140.8h.7"/>
<path d="M187.2 146.6l-.3 1h.8M187.5 149.1h-.5l-.1 .6 .6-.1v.7l-.6-.1M187.5 151.5a.72 .72 0 0 0-.5 .5 .72 .72 0 0 0 .2 .7h.3l.1-.5a.35 .35 0 0 0-.3-.2 .35 .35 0 0 0-.4 .2M187.5 147.2v.7M187.9 153h-7.1v2.4M188.7 141.6l.4-1.1 .4 1.1M188.7 144l.4-1.2 .4 1.2M188.8 141.3h.6M188.8 143.7h.6M188.9 145.2a.66 .66 0 0 1 .6 .4 .66 .66 0 0 1-.2 .8h-.4zM188.9 147.6a.66 .66 0 0 1 .6 .4 .66 .66 0 0 1-.2 .8h-.4zM188.9 150h.4a.66 .66 0 0 1 .2 .8 .66 .66 0 0 1-.6 .4z"/>
<path d="M189.5 152.4h-.4a.67 .67 0 0 0-.3 .7 .67 .67 0 0 0 .5 .5l.3-.2v-.3h-.3M189.8 140.8l.4-.3v1.1M189.8 141.6h.7M190 142.9l.2-.1 .3 .3v.7l-.3 .2a.7 .7 0 0 1-.2-1.1zM190 147.9h.2l.1-.3v1.2M190 150.1l.6-.1 .2 .2-.1 .3-.7 .7h.8M190 148.8h.8M190.2 145.3l.1-.1a.61 .61 0 0 1 .5 .7 .61 .61 0 0 1-.6 .5l-.2-.4zM190.8 152.4v1.2l-.7-1.2v1.2M191.3 152.4h.5a.66 .66 0 0 1 .2 .8 .66 .66 0 0 1-.7 .4zM199.1 140.4l-1 1.5M199.5 142.8a.6 .6 0 0 1 .7 .6 .6 .6 0 0 1-.7 .6z"/>
<path d="M199.5 145.2a.66 .66 0 0 1 .6 .4 .66 .66 0 0 1-.2 .8h-.4zM199.5 147.6a.66 .66 0 0 1 .6 .4 .66 .66 0 0 1-.2 .8h-.4zM199.5 150h.4a.66 .66 0 0 1 .2 .8 .66 .66 0 0 1-.6 .4zM199.5 152.4h.4a.66 .66 0 0 1 .2 .8 .66 .66 0 0 1-.6 .4zM200.2 140.5a.45 .45 0 0 0-.7 .2v.7a.45 .45 0 0 0 .7 .2M200.5 142.8h.8l-.5 1.2M200.5 152.4h.8l-.5 .4 .4 .1v.6l-.5 .1-.2-.2M200.7 141.1h.4M200.8 149.9l-.2 .9h.7M201.2 145.2h-.3a.93 .93 0 0 0-.2 1.2h.5l.1-.5-.1-.2h-.5l-.1 .2M201.2 147.6h-.5l-.1 .6 .6-.1v.7l-.6-.1M201.2 150.4v.8"/>
<path d="M201.3 140.5h-.6v1.1h.6M202.2 153h7.2M202.2 148.3h7.2M202.2 150.6h7.2M202.2 141.1h7.2M202.2 143.5h7.2M202.2 145.9h7.2M202.5 142.1l.5-.1 .2 .3-.8 .9h.8M202.5 144.4h.4l.3 .3-.8 .8h.8M202.5 147.1l.4-.4v1.2M202.5 149.4l.4-.3v1.2M202.5 151.9l.4-.4v1.2"/>
<path d="M202.5 152.7h.7M202.5 147.9h.7M202.5 150.3h.7M203.5 151.5h.9l-.5 1.2M203.6 142.3l.4-.3v1.2M203.6 143.2h.7M203.7 144.4h.3a.78 .78 0 0 1 0 1.1h-.3zM203.9 149.6h-.2a.31 .31 0 0 1 .1-.4 .31 .31 0 0 1 .4 .1v.3h-.3l-.3 .3 .1 .4h.5l.1-.2v-.2l-.3-.3M204.3 147.2a.35 .35 0 0 1-.3 .3 .35 .35 0 0 1-.4-.3v-.2a.35 .35 0 0 1 .4-.3 .35 .35 0 0 1 .3 .3l-.2 .8-.4 .1M206.2 148.9a.64 .64 0 0 1 .6 .7 .64 .64 0 0 1-.6 .6zM206.2 151.4h.4a.66 .66 0 0 1 .2 .7 .66 .66 0 0 1-.6 .5zM206.2 146.6a.66 .66 0 0 1 .6 .4 .66 .66 0 0 1-.2 .7h-.4z"/>
<path d="M206.2 144.2a.66 .66 0 0 1 .6 .4 .66 .66 0 0 1-.2 .8h-.4zM206.2 141.8l.6 .2v.3v.5l-.4 .2h-.2zM207.3 151.4h.6l-.3 .4 .3 .1v.5l-.1 .2h-.4l-.1-.2M207.3 141.8h.7l-.5 1.2M207.6 148.9l-.3 .9h.7M207.9 144.2l-.5 .1-.1 .8 .1 .3 .5-.1v-.5l-.1-.2h-.3l-.2 .3M207.9 149.4v.8M207.9 146.6h-.6v.6l.6-.1v.6h-.6M212 159.6l-.1-.1a.66 .66 0 0 0-.6 .5 .66 .66 0 0 0 .3 .7l.5-.1v-.4h-.3M212.9 155.4v1.2h1.2l-1.2 1.2-1.1-1.2h1.1M212.9 155.4h.1M212.9 148.3h7.2"/>
<path d="M212.9 150.6h7.2M212.9 141.1h7.2M212.9 143.5h7.2M212.9 145.9h7.2M213.3 159.5v1.2l-.7-1.2v1.2M213.9 159.5a.66 .66 0 0 1 .6 .4 .66 .66 0 0 1-.2 .8h-.4zM214.4 140.6l.3-1.2 .4 1.2M214.4 143l.3-1.2 .4 1.2M214.5 142.7h.6M214.5 140.3h.6M214.5 146.6a.66 .66 0 0 1 .7 .4 .66 .66 0 0 1-.2 .7h-.5zM214.5 144.2a.66 .66 0 0 1 .7 .4 .66 .66 0 0 1-.2 .8h-.5z"/>
<path d="M214.5 148.9a.64 .64 0 0 1 .7 .7 .64 .64 0 0 1-.7 .6zM215.5 142.2l.3-.4v1.2M215.5 143h.7M215.6 149.3l.4-.4v1.3M215.6 150.2h.7M215.9 144.7l-.3-.3a.35 .35 0 0 1 .4-.2 .35 .35 0 0 1 .3 .2l-.2 .3a.4 .4 0 0 0-.4 .2 .4 .4 0 0 0 0 .5l.5-.1a.36 .36 0 0 0-.1-.6M216.3 147.1a.35 .35 0 0 1-.3 .2 .35 .35 0 0 1-.4-.2l.1-.5h.5v.9l-.1 .2h-.4M216.9 149l.3-.1 .2 .3v.7l-.2 .3a.71 .71 0 0 1-.3-1.2zM218 142.3l.4-.3v1.2M218 144.7l.4-.3v1.1M218 147.1l.4-.4v1.2M218 149.4l.4-.3v1.2"/>
<path d="M218 151.9l.4-.4v1.2M218 152.7h.7M218 140.8h.7M218 143.2h.7M218 145.5h.7M218 147.9h.7M218 150.3h.7M219 144.4h.8l-.4 .4 .3 .1v.6h-.7M219.1 142.1l.6-.1 .1 .3-.8 .9h.8M219.1 140.8h.7M219.4 146.6l-.3 1h.8M219.7 149.1h-.5l-.1 .6 .6-.1v.7l-.6-.1"/>
<path d="M219.7 151.5a.72 .72 0 0 0-.6 .5 .72 .72 0 0 0 .3 .7h.3l.1-.5a.35 .35 0 0 0-.3-.2 .35 .35 0 0 0-.4 .2M219.7 147.2v.7M220.1 153h-7.2v2.4M220.9 141.6l.4-1.1 .4 1.1M220.9 144l.4-1.2 .4 1.2M221.1 145.2h.3l.3 .3v.6l-.1 .3h-.5zM221.1 147.6h.3l.3 .3v.6l-.1 .3h-.5zM221.1 150h.5l.1 .3v.6l-.3 .3h-.3zM221.1 141.3h.5M221.1 143.7h.5M221.7 152.4h-.5l-.1 .3v.5l.1 .3h.5v-.4h-.1M222.1 140.8l.3-.3v1.1"/>
<path d="M222.1 141.6h.7M222.2 142.9l.2-.1a.64 .64 0 0 1 .4 .7 .64 .64 0 0 1-.5 .5l-.2-.2zM222.3 147.9l.3-.3v1.2M222.3 150.1l.5-.1 .1 .4-.7 .8h.7M222.3 148.8h.6M222.5 145.2a.71 .71 0 0 1 .3 1.2h-.4l-.1-.2v-.7zM222.9 152.4v1.2l-.6-1.2v1.2M223.5 152.4h.5l.2 .3v.5a.52 .52 0 0 1-.7 .4zM231.3 140.4l-1 1.5M231.6 142.8l.6 .2 .1 .3-.1 .5-.3 .2h-.3zM231.6 145.2a.66 .66 0 0 1 .7 .4 .66 .66 0 0 1-.2 .8h-.5zM231.6 147.6a.66 .66 0 0 1 .7 .4 .66 .66 0 0 1-.2 .8h-.5z"/>
<path d="M231.6 150h.5a.66 .66 0 0 1 .2 .8 .66 .66 0 0 1-.7 .4zM231.6 152.4h.5a.66 .66 0 0 1 .2 .8 .66 .66 0 0 1-.7 .4zM232.4 140.5h-.2a.6 .6 0 0 0-.6 .6 .6 .6 0 0 0 .6 .5h.2M232.7 142.8h.8l-.5 1.2M232.7 152.4h.7l-.3 .4 .3 .1v.5l-.1 .2h-.4l-.2-.2M232.9 141.1h.4M233.1 149.9l-.4 .9h.8M233.3 145.2l-.4 .2-.2 .8 .2 .2 .5-.1-.1-.6h-.4l-.2 .2M233.3 150.4v.8M233.4 140.5h-.5v1.1h.5M233.4 147.6h-.6l-.1 .6 .6-.1 .1 .6h-.7M234.4 153h7.2"/>
<path d="M234.4 148.3h7.2M234.4 150.6h7.2M234.4 141.1h7.2M234.4 143.5h7.2M234.4 145.9h7.2M234.7 142.1l.6-.1 .1 .3-.8 .9h.8M234.7 144.4h.4l.3 .3-.8 .8h.8M234.7 147.1l.3-.4v1.2M234.7 149.4l.3-.3v1.2M234.7 151.9l.3-.4v1.2M234.7 152.7h.7M234.7 147.9h.7"/>
<path d="M234.7 150.3h.7M235.8 142.3l.3-.3v1.2M235.8 151.5h.8l-.5 1.2M235.8 143.2h.7M236 144.4h.2l.3 .2v.7l-.4 .2a.7 .7 0 0 1-.1-1.1zM236.1 149.6l-.3-.2 .3-.3h.2l.2 .4-.4 .1-.3 .3 .2 .4 .5-.1v-.4l-.2-.2M236.5 147.2v.2a.42 .42 0 0 1-.6 0 .42 .42 0 0 1 0-.6h.6v.9l-.2 .2h-.3M238.3 144.2h.4l.3 .2v.7l-.2 .3h-.5zM238.3 146.6h.4l.3 .3v.6l-.2 .2h-.5zM238.3 141.8h.4l.3 .3v.6l-.3 .3h-.4zM238.3 148.9l.5 .1 .2 .3v.6l-.3 .3h-.4zM238.3 151.4h.5l.2 .2v.6l-.3 .4h-.4z"/>
<path d="M239.5 144.5l.4-.3v1.2M239.5 146.9l.4-.3v1.1M239.5 142.2l.4-.4v1.2M239.5 149.3l.4-.4v1.3M239.5 151.7l.4-.3v1.2M239.5 145.4h.7M239.5 143h.7M239.5 147.7h.7M239.5 150.2h.7M239.5 152.6h.7M240.5 146.6h.8l-.4 .5h.3l.1 .1-.1 .5h-.7M240.6 149.1l.4-.2 .3 .4-.8 .9h.8"/>
<path d="M240.6 151.7l.4-.3v1.2M240.6 152.6h.7M240.9 144.1l-.3 .8h.8M241.2 141.8h-.5l-.1 .6 .2-.2 .4 .1v.6h-.6M241.2 144.6v.8M244.3 159.6l-.2-.1a.66 .66 0 0 0-.6 .5 .66 .66 0 0 0 .3 .7h.5v-.5h-.2M245.1 155.4v1.2h1.2l-1.2 1.2-1.2-1.2h1.2M245.1 155.4h.1M245.1 148.3h7.2M245.1 150.6h7.2M245.1 141.1h7.2M245.1 143.5h7.2"/>
<path d="M245.1 145.9h7.2M245.4 159.5v1.2l-.6-1.2v1.2M246 159.5a.66 .66 0 0 1 .7 .4 .66 .66 0 0 1-.2 .8h-.5zM246.5 143l.5-1.2 .3 1.2M246.5 140.6l.5-1.2 .3 1.2M246.6 142.7h.6M246.6 140.3h.6M246.7 148.9a.64 .64 0 0 1 .7 .7 .64 .64 0 0 1-.7 .6zM246.7 146.6a.66 .66 0 0 1 .7 .4 .66 .66 0 0 1-.3 .7h-.4zM246.7 144.2a.66 .66 0 0 1 .7 .4 .66 .66 0 0 1-.3 .8h-.4zM247.7 142.2l.3-.4v1.2M247.7 143h.6"/>
<path d="M247.8 149.3h.2l.2-.4v1.3M247.8 150.2h.7M248.1 144.7l-.3-.3 .3-.2 .4 .1v.3a.48 .48 0 0 0-.5 .2 .48 .48 0 0 0 0 .6l.5-.1v-.5l-.2-.1M248.5 147.1v.1l-.4 .1-.2-.1-.1-.4 .3-.2 .4 .1v.8l-.2 .2h-.3M249.3 148.9a.68 .68 0 0 1 .4 .7 .68 .68 0 0 1-.4 .6l-.3-.3v-.7zM250.2 142.3l.3-.3v1.2M250.2 144.7l.3-.3v1.1M250.2 147.1l.3-.4v1.2M250.2 149.4l.3-.3v1.2M250.2 151.9l.3-.4v1.2M250.2 152.7h.7M250.2 140.8h.7"/>
<path d="M250.2 143.2h.7M250.2 145.5h.7M250.2 147.9h.7M250.2 150.3h.7M251.3 142.1h.7v.4l-.7 .7h.7M251.3 144.4h.7l-.4 .4 .4 .1v.6h-.7M251.3 140.8h.7M251.6 146.6l-.3 1h.8M251.9 151.5a.72 .72 0 0 0-.6 .5 .72 .72 0 0 0 .2 .7l.5-.1v-.5l-.5-.1-.2 .2M251.9 147.2v.7M252 149.1h-.6l-.1 .6 .6-.1 .1 .6h-.7M252.3 153h-7.2v2.4"/>
<path d="M253.2 141.6l.3-1.1 .4 1.1M253.2 144l.3-1.2 .4 1.2M253.2 141.3h.6M253.2 143.7h.6M253.3 145.2a.66 .66 0 0 1 .7 .4 .66 .66 0 0 1-.3 .8h-.4zM253.3 147.6a.66 .66 0 0 1 .7 .4 .66 .66 0 0 1-.3 .8h-.4zM253.3 150h.4a.66 .66 0 0 1 .3 .8 .66 .66 0 0 1-.7 .4zM253.9 152.4h-.4a.67 .67 0 0 0-.3 .7 .67 .67 0 0 0 .5 .5l.3-.2v-.3h-.3M254.3 140.8l.3-.3v1.1M254.3 141.6h.6M254.3 142.9l.4-.1a.78 .78 0 0 1 0 1.2l-.4-.1zM254.4 147.9l.4-.3v1.2"/>
<path d="M254.4 150.1l.6-.1 .1 .4-.8 .8h.8M254.4 148.8h.7M254.7 145.2a.75 .75 0 0 1 .2 1.2h-.3l-.2-.4 .1-.6zM255.2 152.4v1.2l-.7-1.2v1.2M255.7 152.4h.5l.2 .3v.5l-.4 .4h-.3zM263.5 140.4l-1 1.5M263.8 142.8h.4l.3 .3v.7l-.3 .2h-.4zM263.8 145.2h.4l.3 .3v.6l-.2 .3h-.5zM263.8 147.6h.4l.3 .3v.6l-.2 .3h-.5zM263.8 150h.5l.2 .3v.6l-.3 .3h-.4zM263.8 152.4h.5l.2 .3v.5l-.3 .4h-.4zM264.6 140.5a.55 .55 0 0 0-.8 .6 .55 .55 0 0 0 .8 .5"/>
<path d="M264.9 142.8h.8l-.5 1.2M264.9 152.4h.8l-.4 .4 .3 .1 .1 .4-.3 .3h-.3l-.2-.2M265.1 141.1h.4M265.3 149.9l-.3 .9h.7M265.5 145.2l-.3 .1-.2 .2v.8l.5 .1 .2-.2v-.3l-.2-.2h-.4l-.1 .2M265.5 150.4v.8M265.6 147.6h-.6v.6l.5-.1 .2 .2v.3l-.2 .2-.5-.1M265.7 140.5h-.6v1.1h.6M266.6 153h7.1M266.6 148.3h7.1M266.6 150.6h7.1M266.6 141.1h7.1"/>
<path d="M266.6 143.5h7.1M266.6 145.9h7.1M266.9 142.1l.6-.1v.5l-.7 .7h.7M266.9 144.4h.6v.5l-.7 .6h.7M266.9 147.1l.3-.4v1.2M266.9 149.4l.3-.3v1.2M266.9 151.9l.3-.4v1.2M266.9 152.7h.6M266.9 147.9h.6M266.9 150.3h.6M268 151.5h.7l-.5 1.2M268.1 142.3l.3-.3v1.2"/>
<path d="M268.1 143.2h.6M268.1 144.4h.3a.64 .64 0 0 1 .4 .6 .64 .64 0 0 1-.5 .5l-.2-.2zM268.2 149.6l-.1-.1v-.2l.4-.2 .2 .3-.6 .4v.5h.5l.1-.2v-.2l-.2-.3M268.7 147.2l-.2 .3-.4-.1v-.6l.4-.1 .2 .3-.1 .8-.5 .1M270.5 148.9a.65 .65 0 0 1 .8 .7 .65 .65 0 0 1-.8 .6zM270.5 151.4h.5a.66 .66 0 0 1 .2 .8 .66 .66 0 0 1-.7 .4zM270.5 146.6a.66 .66 0 0 1 .7 .3 .66 .66 0 0 1-.2 .8h-.5zM270.5 141.8a.61 .61 0 0 1 .8 .6 .61 .61 0 0 1-.8 .6zM270.5 144.2a.66 .66 0 0 1 .7 .4 .66 .66 0 0 1-.2 .8h-.5zM271.7 149.3l.3-.4v1.3M271.7 151.7l.3-.3v1.2M271.7 146.9l.3-.3v1.1"/>
<path d="M271.7 142.2l.3-.4v1.2M271.7 144.5l.3-.3v1.2M271.7 145.4h.7M271.7 143h.7M271.7 147.7h.7M271.7 150.2h.7M271.7 152.6h.7M272.8 149.1l.2-.2h.3l.2 .2v.3l-.7 .8h.7M272.8 151.7l.3-.3v1.2M272.8 146.6h.7l-.4 .5 .4 .1v.5h-.7M272.8 152.6h.7M273.1 144.1l-.3 .8h.8"/>
<path d="M273.4 144.6v.8M273.5 141.8h-.6l-.1 .6 .2-.2h.3l.2 .2v.5h-.7M276.6 156.5h1.9M19.1 179.4a.66 .66 0 0 1 .6 .4 .66 .66 0 0 1-.2 .8h-.4zM28.7 168.6v.8l-.2 .4h-.3M29.2 165.9l-.2-.2a.65 .65 0 0 0-.6 .6 .65 .65 0 0 0 .6 .7l.2-.2M29.3 174.3h.8v.3h-.8zM29.3 176.8h.8v.2h-.8zM29.3 179.2h.8v.2h-.8zM29.3 161.3h.8v.2h-.8zM29.3 163.7h.8v.2h-.8zM29.5 168.6l-.3 .8h.7"/>
<path d="M29.7 166.2h.5v.6l-.1 .2-.5-.3zM29.7 169v.8M30.1 174.5h11.1M30.1 176.9h11.1M30.1 179.2h11.1M30.1 161.4h11.1M30.1 163.7h11.1M30.7 166.2h.5v.8M30.7 166.1v.9M31.8 166.2l.4-.1 .1 .2v.7M31.8 166.1v.9M31.9 173.3l.4-.3v1.2"/>
<path d="M31.9 175.5l.2-.2h.3l.2 .2v.4l-.7 .6h.7M31.9 177.7h.7l-.3 .5 .3 .1v.5h-.7M31.9 174.2h.7M32.2 160.4l-.3-.3 .3-.2h.4v.4a.51 .51 0 0 0-.6 .7h.6v-.6h-.2M32.6 162.7v.2l-.4 .1-.2-.1-.1-.4 .3-.3 .4 .2v.8l-.2 .2h-.3M32.6 167h.9M34 165.7a.68 .68 0 0 1 .5 .6 .68 .68 0 0 1-.5 .7l-.2-.5 .1-.6zM34.9 166h.2l.1-.3v1.3M34.9 167h.7M35.5 172.5h2.1M35.5 161.7h3.2M35.6 175.9l.6-.1v-.5l-.6-.1v1.2"/>
<path d="M35.6 178.3h1M35.9 175.9l.4 .5M36 166.1l.6 .9M36.1 177.9v.9M36.3 172.9a.61 .61 0 0 0-.7 .3 .61 .61 0 0 0 .2 .8l.5-.1M36.3 162.2l-.2-.1a.67 .67 0 0 0-.5 .5 .67 .67 0 0 0 .2 .6h.5M36.6 166.1l-.6 .9M36.7 175.2l.3 1.2 .3-.9 .1 .9 .4-1.2M36.9 177.5l.4 1.3 .5-1.3M37.3 165.7a.68 .68 0 0 1 .4 .6 .68 .68 0 0 1-.4 .7l-.3-.5 .1-.6zM37.4 172.9l-.4-.1-.3 .3 .3 .3 .4 .2v.3l-.7 .1M37.4 160.4h.5l.2-.2v-.3l-.2-.2h-.5v1.2"/>
<path d="M37.4 162.1h-.4l-.3 .2 .1 .3 .6 .2v.4h-.7M37.8 160.4l.3 .5M37.9 173.1l.4-.3v1.2M37.9 174h.7M38.1 178.1h.6v-.5l-.6-.1v1.3h.5l.3-.4-.4-.3M38.2 175.3l.5-.1a.86 .86 0 0 1 .1 1.2h-.4a.74 .74 0 0 1-.2-1.1zM38.2 162.1a.75 .75 0 0 1 .2 1.1h-.3l-.2-.1v-.8zM38.9 160.6l.6 .4M38.9 166.2l-.3 .3-.4-.1v-.5l.4-.2a.72 .72 0 0 1 .3 .7 .72 .72 0 0 1-.6 .6M39 167h1M39.1 173.4h.4M39.1 162.6h.4"/>
<path d="M39.5 175.8h.4M39.7 172.8h-.6v1.2h.6M39.7 162.1h-.6v1.1h.6M40 175.2h-.5v1.2h.5M40.2 166.4h.5l.2-.2v-.3l-.2-.2h-.5v1.3M41.4 165.7v.2M41.4 166.1v.9M42 166.2l.3-.1 .2 .2v.7M42 166.1v.9M46.8 174.6h1M47.3 174.2v.8M47.8 169.7h.5l.2-.2-.1-.3-.6-.1v1.2"/>
<path d="M48.3 179.2h.1M48.3 176.9l-.6 1.2M48.3 176.9l.8 1.2M48.3 176.9v5M48.9 169.1l.3 1.2 .2-.9 .2 .9 .4-1.2M48.9 173.8h-.6v.6l.6-.1v.7l-.6-.1M49.3 173.8l.4 1.2 .4-1.2M50.4 169.7h.6v-.5l-.6-.1v1.2M50.6 169.7l.5 .6M51.3 170.3h.9M52 173.3l.9-.6-.9-.6-1 .6 1 .6v1.2M52 174.5h.1"/>
<path d="M52 174.5v4.7h-7.2v2.4h-14.7M52.5 169.7h.3M53 169.1h-.5v1.2M53.5 169.1v1.2h.6M54.3 170.3l.4-1.2 .4 1.2M54.4 169.9h.5M56.1 169.2a.45 .45 0 0 0-.6 .1v.7a.45 .45 0 0 0 .6 .2v-.4h-.1M60.4 164.2h.8M60.8 164v.8l-.9-.4M60.9 171l1.2 .4-1.2 .4M60.9 179.6v.4a.67 .67 0 0 0 .6 .3 .67 .67 0 0 0 .6-.6l-.2-.2h-.3v.2M60.9 178.3h1.2l-1.2 .7h1.2"/>
<path d="M61 169.9l-.1 .5a.67 .67 0 0 0 .6 .3 .67 .67 0 0 0 .6-.5l-.2-.3M61 168.7l-.1 .5a.67 .67 0 0 0 .6 .3 .67 .67 0 0 0 .6-.5l-.2-.3M61 177.1h.9l.2 .6h-1.2v-.4zM61.2 165.5h-1.3l.5 .4M61.2 165.2v.7M61.5 160.2h.1M61.5 161.4h8.4v1.8M67.7 175h.8l-.5 1.2M67.8 172.6v1.1l.2 .1 .5-.1v-1.1M68.9 170.3a.54 .54 0 0 0-.7 .6 .54 .54 0 0 0 .8 .5v-.5h-.3M69 173l.3-.4v1.2M69 173.8h.8"/>
<path d="M69.2 175l-.3 .9h.8M69.5 175.4v.8M69.9 166.1v1.2h1.1l-1.1 1.2-1.2-1.2h1.2M69.9 166.1h.1M69.9 164.3v1.8M70.1 175.6h.7M70.1 175v1.2M70.2 170.3v1.1l-.7-1.1v1.1M70.3 173.2h.3M70.8 170.3a.6 .6 0 0 1 .7 .6 .6 .6 0 0 1-.7 .5zM70.8 172.6h-.5v1.2h.5M70.8 175v1.2"/>
<path d="M72.1 175.2l-.3-.2a.67 .67 0 0 0-.5 .5 .67 .67 0 0 0 .2 .7l.6-.1M72.6 164.7l.3-.4v1.2M72.6 165.5h.6M72.6 175.1l.3-.1 .3 .3v.7l-.2 .2h-.4l-.1-.4zM73.3 162.1l-.2-.2a.65 .65 0 0 0-.6 .6 .65 .65 0 0 0 .6 .7l.2-.2M73.7 161.9h.7l-.4 .5h.3v.7l-.5 .1-.1-.2M73.8 164.3h.4l.1 .2v.8l-.2 .2a.71 .71 0 0 1-.3-1.2zM73.9 175a.71 .71 0 0 1 .3 1.2h-.4l-.1-.2v-.7zM74.9 164.4l.1-.1a.59 .59 0 0 1 .6 .4 .59 .59 0 0 1-.2 .7l-.1 .1-.4-.1zM76 164.8l.2-.1 .3 .1v.7M76 164.7v.8M77.1 164.8h.4"/>
<path d="M77.6 164.3h-.5v1.2M79.5 164.2h.8M79.8 164v.8l-.8-.4M79.9 171l1.2 .4-1.2 .4M79.9 178.3h1.2l-1.2 .7h1.2M80 169.9l-.1 .3a.6 .6 0 0 0 .6 .5 .6 .6 0 0 0 .6-.5l-.1-.3M80 168.7a.55 .55 0 0 0 .5 .8 .55 .55 0 0 0 .5-.8M80 179.6a.54 .54 0 0 0 .6 .7 .54 .54 0 0 0 .4-.8h-.4v.2M80.1 177.1h.8l.2 .6h-1.2zM80.3 165.5h-1.2l.3 .4M80.3 165.2v.7M80.6 160.2h.1"/>
<path d="M80.6 161.4h8.3v1.8M86.8 175h.8l-.5 1.2M87 172.6v1.2h.5l.1-.1v-1.1M88.1 170.3a.45 .45 0 0 0-.7 .2v.7a.45 .45 0 0 0 .7 .2v-.5h-.2M88.3 175l-.3 .9h.7M88.6 175.4v.8M88.7 172.6l-.6 .3v.8l.6 .1v-.7h-.4l-.2 .2M88.9 166.1v1.2h1.2l-1.2 1.2-1.2-1.2h1.2M88.9 166.1h.1M88.9 164.3v1.8M89.2 170.3v1.1l-.6-1.1v1.1M89.2 175v1.2"/>
<path d="M89.2 175.6h.7M89.3 173.2h.4M89.8 170.3l.6 .1 .1 .4-.1 .5-.3 .1h-.3zM89.9 172.6h-.6v1.2h.6M89.9 175v1.2M91.1 175.2l-.3-.2-.4 .3v.6l.2 .3 .5-.1M91.5 175h.8l-.4 .5 .4 .2v.3l-.2 .2-.6-.1M91.6 164.7l.3-.4v1.2M91.6 165.5h.7M92.4 162.1l-.3-.2a.65 .65 0 0 0-.5 .6 .65 .65 0 0 0 .5 .7l.3-.2M92.7 175.2l.4-.2 .3 .3-.8 .9h.8M92.8 164.5l.2-.2a.6 .6 0 0 1 .5 .5 .6 .6 0 0 1-.2 .6l-.3 .1-.2-.2z"/>
<path d="M93.6 162.4l-.3 .2h-.4l-.1-.2v-.3l.2-.2h.3a.72 .72 0 0 1 .3 .7 .72 .72 0 0 1-.6 .6M94.1 164.3h.3l.2 .2v.8l-.3 .2a.71 .71 0 0 1-.2-1.2zM95.1 164.8l.2-.1 .3 .1v.7M95.1 164.7v.8M96.2 164.8h.4M96.8 164.3h-.6v1.2M98.1 164.2l.2 .4 .8 .2 .2-.2v-.4l-.2-.2h-.3l-.2 .2v.4l.2 .2M99 171l1.2 .4-1.2 .4M99 178.3h1.2l-1.2 .7h1.2M99.1 179.6l-.1 .1a.66 .66 0 0 0 .4 .5 .66 .66 0 0 0 .8-.2l-.1-.5h-.4v.2M99.1 169.9l-.1 .3a.67 .67 0 0 0 .5 .5 .67 .67 0 0 0 .7-.3l-.1-.5M99.1 168.7l-.1 .3a.67 .67 0 0 0 .5 .5 .67 .67 0 0 0 .7-.3l-.1-.5"/>
<path d="M99.1 177.1h.9l.2 .2v.4h-1.2zM99.3 165.5h-1.2l.4 .4M99.3 165.2v.7M99.7 160.2h.1M99.7 161.4h7.1v1.8M105.9 170.3a.45 .45 0 0 0-.7 .2v.7a.45 .45 0 0 0 .7 .2v-.5h-.2M106 172.6l.1 1.2h.5l.1-1.2M106.8 166.1v1.2h1.2l-1.2 1.2-1.2-1.2h1.2M106.8 166.1h.1M106.8 164.3v1.8M107.2 170.3v1.1l-.7-1.1v1.1M107.2 173l.3-.4v1.2"/>
<path d="M107.2 173.8h.7M107.7 170.3h.3l.4 .2v.7l-.4 .2h-.3zM108.4 173l.3-.4v1.2M108.4 173.8h.7M110.2 172.7l-.2-.1a.67 .67 0 0 0-.5 .5 .67 .67 0 0 0 .2 .7l.5-.1M112.8 162.6h11.9M116.3 174.5h8.4M116.3 176.9h8.4M116.3 179.2h8.4M116.3 172.1h8.4M116.3 160.2h8.4M116.3 164.9h8.4"/>
<path d="M116.3 167.3h8.4M116.3 169.8h8.4M116.8 175.2a.66 .66 0 0 1 .6 .4 .66 .66 0 0 1-.2 .8h-.4zM116.8 172.8a.66 .66 0 0 1 .6 .4 .66 .66 0 0 1-.2 .8h-.4zM116.8 177.5a.64 .64 0 0 1 .6 .7 .64 .64 0 0 1-.6 .6zM116.8 170.4a.6 .6 0 0 1 .6 .6 .6 .6 0 0 1-.6 .6zM116.8 165.7h.4a.66 .66 0 0 1 .2 .7 .66 .66 0 0 1-.6 .5zM116.8 168.1h.4a.66 .66 0 0 1 .2 .7 .66 .66 0 0 1-.6 .4zM116.8 163.2a.64 .64 0 0 1 .6 .7 .64 .64 0 0 1-.6 .6zM117.9 175.5l.3-.3v1.2M117.9 177.9l.3-.4v1.3M117.9 165.8l.5-.1 .1 .3-.7 .9h.7"/>
<path d="M117.9 178.8h.6M117.9 176.4h.6M118.1 173.3l-.2-.2a.35 .35 0 0 1 .3-.3 .35 .35 0 0 1 .3 .3l-.2 .2a.4 .4 0 0 0-.4 .2 .4 .4 0 0 0 0 .5l.5-.1a.36 .36 0 0 0-.1-.6M118.1 168l-.2 .8h.7M118.1 163.2a.68 .68 0 0 1 .4 .7 .68 .68 0 0 1-.4 .6l-.2-.5v-.6zM118.4 170.4l-.4 .1-.1 .9a.35 .35 0 0 0 .3 .2 .35 .35 0 0 0 .3-.2l-.1-.5h-.1l-.4 .2M118.4 168.4v.8M119 177.7l.5-.2 .2 .4-.7 .9h.7M119.3 175.2a.71 .71 0 0 1 .2 1.2h-.3l-.2-.2v-.8zM119.3 179.9l-.3 .9h.7M122 161.4l.3-.4v1.2M122 163.7l.3-.3v1.2"/>
<path d="M122 166.2l.3-.4v1.2M122 168.3l.6-.1 .1 .4-.8 .8h.8M122 170.7l.4-.1 .3 .3-.8 .9h.8M122 173.1l.4-.1 .3 .3-.8 .9h.8M122 175.5l.4-.2 .3 .4-.8 .8h.8M122 177.9l.4-.2 .3 .4-.8 .8h.8M122 162.2h.7M122 164.6h.7M122 167h.7M123.1 163.4h.8l-.5 1.2M123.1 168.6l.3-.4v1.2M123.1 170.6h.7l-.4 .4 .4 .2v.5h-.7"/>
<path d="M123.1 175.3h.8l-.5 1.2M123.1 169.4h.7M123.8 161h-.6l-.1 .6 .6-.1 .1 .6h-.7M123.8 166.4l-.1 .1h-.4l-.2-.1v-.4l.3-.2 .4 .1v.8l-.2 .3h-.3M123.8 173h-.6l-.1 .6 .2-.2h.3l.2 .2v.5h-.7M123.8 178.2v.2l-.4 .1-.2-.1-.1-.4 .3-.3 .4 .2v.7l-.2 .3h-.3M124.7 160h1.2v.3h-1.2zM124.7 162.5h1.2v.1h-1.2zM124.7 164.8h1.2v.3h-1.2zM124.7 167.2h1.2v.3h-1.2zM124.7 169.6h1.2v.2h-1.2zM124.7 172h1.2v.2h-1.2z"/>
<path d="M124.7 174.3h1.2v.3h-1.2zM124.7 176.8h1.2v.2h-1.2zM124.7 179.2h1.2v.2h-1.2zM128.3 160h1.2v.3h-1.2zM128.3 162.5h1.2v.1h-1.2zM128.3 164.8h1.2v.3h-1.2zM128.3 167.2h1.2v.3h-1.2zM128.3 169.6h1.2v.2h-1.2zM128.3 172h1.2v.2h-1.2zM128.3 174.3h1.2v.3h-1.2zM128.3 176.8h1.2v.2h-1.2zM128.3 179.2h1.2v.2h-1.2z"/>
<path d="M129.5 174.5h9.5M129.5 176.9h9.5M129.5 179.2h9.5M129.5 172.1h9.5M129.5 160.2h9.5M129.5 164.9h9.5M129.5 167.3h9.5M129.5 169.8h9.5M130.3 177.7h.8l-.5 .5 .5 .2v.3l-.2 .2-.6-.1M130.4 161.4l.3-.4v1.2M130.4 163.7l.3-.3v1.2M130.4 165.9l.4-.1 .3 .4-.8 .8h.8"/>
<path d="M130.4 168.3l.5-.1 .2 .4-.8 .8h.8M130.4 170.7l.4-.1 .3 .3-.8 .9h.8M130.4 173.1l.4-.1 .3 .3-.8 .9h.8M130.4 175.5l.4-.2 .3 .4-.8 .8h.8M130.4 162.2h.7M130.4 164.6h.7M131.5 168.3l.6-.1 .1 .4-.8 .8h.8M131.7 163.9h-.1a.31 .31 0 0 1 .1-.4 .31 .31 0 0 1 .4 .1v.3h-.4l-.2 .3 .1 .4h.5l.1-.2v-.2l-.3-.3M131.7 165.8a.68 .68 0 0 1 .5 .6 .68 .68 0 0 1-.5 .6l-.2-.5 .1-.6zM131.7 170.5l-.2 .9h.7M131.7 175.9h-.1a.31 .31 0 0 1 .1-.5 .31 .31 0 0 1 .4 .1v.4h-.4l-.2 .2 .1 .4h.5l.1-.1v-.3l-.3-.2M131.7 177.7a.75 .75 0 0 1 .3 1.2h-.3l-.2-.4 .1-.6z"/>
<path d="M132.1 161h-.3a.93 .93 0 0 0-.2 1.2h.5l.1-.5-.1-.2h-.5l-.1 .2M132.1 173l-.4 .1-.2 .8a.35 .35 0 0 0 .3 .3 .35 .35 0 0 0 .4-.3v-.2l-.3-.3-.4 .3M132.1 171v.8M134.6 177.5a.64 .64 0 0 1 .7 .7 .64 .64 0 0 1-.7 .6zM134.6 172.8a.66 .66 0 0 1 .7 .4 .66 .66 0 0 1-.3 .8h-.4zM134.6 170.4l.6 .2 .1 .3-.1 .5-.3 .2h-.3zM134.6 175.2a.66 .66 0 0 1 .7 .4 .66 .66 0 0 1-.3 .8h-.4zM134.6 165.7h.4a.66 .66 0 0 1 .3 .7 .66 .66 0 0 1-.7 .5zM134.6 163.2a.64 .64 0 0 1 .7 .7 .64 .64 0 0 1-.7 .6zM134.6 168.1h.4a.66 .66 0 0 1 .3 .7 .66 .66 0 0 1-.7 .4zM135.7 177.9h.2l.2-.4v1.3M135.7 170.4h.8l-.5 1.2"/>
<path d="M135.7 175.5h.2l.2-.3v1.2M135.7 165.7h.7l-.3 .4 .3 .1v.5l-.2 .2h-.3l-.2-.2M135.7 163.6h.2l.2-.4v1.3M135.7 178.8h.7M135.7 176.4h.7M135.7 164.5h.7M136.4 173.3l-.2 .3h-.2l-.3-.3 .1-.4h.6v.8l-.2 .3h-.3M136.4 168.1h-.6l-.1 .5h.7v.6h-.7M136.8 177.5h.8l-.4 .6 .4 .1v.4l-.3 .2h-.3l-.2-.2M136.9 175.5l.3-.3v1.2M136.9 176.4h.7M145.8 170.7h.7v.4l-.7 .7h.7"/>
<path d="M147.1 176.1v-.8l.4 .5 .2-.5 .5 .1 .1 .5-.2 .2M147.5 171.1a.97 .97 0 0 1 1-1 .97 .97 0 0 1 1 1M147.5 173.1a.97 .97 0 0 0 1 .9 .97 .97 0 0 0 1-.9M147.6 171.6h1.9v1h-1.9zM147.6 171.1h1.9M147.6 173.1h1.9M148.3 168.5h-1.2l.3 .3M148.3 168.1v.7M148.5 174v7.6h3.6M148.5 170.2v-7.6h16.8v9.5h5M149.6 160.9v1.2l-.7-1.2v1.2M150.2 168.3v1l-.4 .3"/>
<path d="M150.4 160.9l.5 .1v.9l-.2 .2h-.4a.86 .86 0 0 1 .1-1.2zM150.8 169l.6-.1v-.5l-.6-.1v1.3M151 172.1h8.5M151.3 170.4v1.2M152.1 160.9v1.2l-.7-1.2v1.2M152.2 168.3l-.3 .9h.8M152.4 162.2h.9M152.5 168.7v.9M152.6 170.4v1.2l-.7-1.2v1.2M153 170.4l.3 1.2 .5-1.2M153.6 160.9v1.2M153.8 171.7h1"/>
<path d="M154.9 160.9v1.2l-.7-1.2v1.2M155 170.4v1.2M155.2 160.9l.4 1.2 .4-1.2M155.4 173.6v1l-.4 .2M156 174.2h.6v-.5l-.6-.1v1.2M156.3 170.4v1.2l-.7-1.2v1.2M157.7 170.7h.7v.4l-.8 .7h.8M157.8 173.6h-.6l-.1 .6 .6-.1 .1 .6h-.7M158.9 176.1v-.8l.5 .5v-.4h.7l.1 .5-.2 .2M159.5 171.6h2v1h-2zM160.2 168.5h-1.3l.4 .3M160.2 168.1v.7"/>
<path d="M160.4 162.6v7.6M160.4 174v6.4M161.4 171.1a.97 .97 0 0 0-1-1 .97 .97 0 0 0-.9 1h2M161.5 173.1h-2a.97 .97 0 0 0 .9 .9 .97 .97 0 0 0 1-.9M165.4 179.7h3.3M165.9 173.6v1l-.4 .2M166.5 174.2h.6v-.5l-.6-.1v1.2M167.6 162.6h3.6v7.6M167.8 160.5h3.2M168.2 173.6l-.4 .1-.2 .9 .2 .2 .5-.1-.1-.6h-.4l-.2 .1M168.5 170.7l.4-.1 .3 .3-.8 .9h.8M168.7 161l-.4-.1-.3 .3v.6l.1 .3 .6-.1"/>
<path d="M169.7 176.1v-.8l.5 .5v-.4l.1-.1 .6 .1-.1 .7M169.8 161l-.5-.1-.1 .1v.4l.6 .3-.1 .4h-.5M170.3 171.6h1.8v1h-1.8zM170.3 173.1h1.8a.93 .93 0 0 1-.9 .9 .93 .93 0 0 1-.9-.9zM170.5 160.9a.75 .75 0 0 1 .3 1.2h-.4l-.1-.5v-.6zM170.5 170.5a.93 .93 0 0 1 1.1-.2 .93 .93 0 0 1 .5 .8h-1.8zM170.9 168.5h-1.2l.3 .3M170.9 168.1v.7M171.2 174v7.6h-5.9M175.3 162.2h101.3v30.1h-101.3zM175.3 176.8h101.3M177.3 179.9h-.7v1.5"/>
<path d="M177.3 177.5h-.6l-.2 .2 .2 .4 .6 .2v.4h-.8M177.8 179.9v.2M178 178.1l.1-.2 .5 .2v.7M178 177.5v1.3M178.5 179.9v1.3l.1 .2M179.2 178.4l.6-.2-.1-.2-.4-.1-.1 .2v.5l.1 .2 .4-.1M180.3 178.4l.7-.2-.2-.3h-.3l-.2 .2v.5l.2 .2 .4-.1M181.4 177.9h.5M181.6 177.5v1.1l.3 .2M182.1 179.9v1.3l.4 .2M182.5 178.7v.1M182.5 178v.1"/>
<path d="M185.1 179.9v1.5M185.2 177.4l-1.2 1.8M187.6 179.9v1.5M188.8 179.9v.2M189.5 179.9v1.3l.3 .2M194.7 179.9v1.4l.2 .1M195.4 179.9v.2M199.2 179.9v1.5M200.4 179.9v.2M204.1 179.9v1.5M208.3 179.9v1.5M277.3 179.4a.66 .66 0 0 1 .6 .4 .66 .66 0 0 1-.2 .8h-.4z"/>
<path d="M24.4 188.5a.45 .45 0 0 0-.7 .1v.7a.45 .45 0 0 0 .7 .2M24.9 188.9l.5-.1v.7h-.5zM26 188.9l.4-.1 .1 .8M26 188.8v.8M27.1 188.9l.4-.1 .1 .8M27.1 188.8v.8M27.9 189.7h.9M29.1 188.5l.3-.1a.64 .64 0 0 1 .3 .6 .64 .64 0 0 1-.4 .6l-.3-.3zM29.3 181.5h.8v.3h-.8zM29.3 183.9h.8v.2h-.8zM29.3 186.3h.8v.2h-.8zM30.1 188.7l.4-.3v1.2"/>
<path d="M30.1 184.1h14.7v2.3h10.7M30.1 186.4h11.1M30.1 189.6h.7M31.2 188.8l.6 .8M31.8 188.8l-.6 .8M32.3 180.1l-.4 .8h.8M32.3 188.5l.3-.1a.64 .64 0 0 1 .4 .6 .64 .64 0 0 1-.5 .6l-.2-.3zM32.5 184.9h-.2a.73 .73 0 0 0-.1 1.2l.4-.1v-.5l-.4-.2-.3 .3M32.5 180.5v.9M32.6 182.5h-.6l-.1 .5h.7v.6l-.2 .1h-.3l-.2-.1M34 188.4h-.3a.73 .73 0 0 0-.1 1.2l.4-.1v-.5l-.4-.2-.2 .3M34.3 189.7h.9"/>
<path d="M35.5 189h.6v-.5l-.6-.1v1.2M35.6 180.7h1M35.6 185.5h1M36.1 180.3v.9M36.1 185v.9M36.2 182.4h-.4a.67 .67 0 0 0-.2 .6 .67 .67 0 0 0 .5 .6l.2-.1v-.5h-.2M36.7 188.4v.1M36.7 188.8v.8M37.1 185.3h.4l.3-.2-.1-.3-.6-.1v1.2h.5l.2-.1v-.4l-.3-.1M37.3 188.9l.4-.1 .1 .8M37.3 188.8v.8M37.5 182.4v1.2l-.7-1.2v1.2"/>
<path d="M37.7 180h-.6v.5h.6l.1 .4-.3 .3-.4-.2M38.1 180l.4 1.2 .4-1.2M38.1 182.4h.4a.66 .66 0 0 1 .3 .7 .66 .66 0 0 1-.7 .5zM38.1 185.9l.4-1.2 .4 1.2M38.3 185.6h.6M39.2 184.7h.7M39.5 184.7v1.2M40 184.7h.7M40.4 184.7v1.2M40.9 186h.8M42.1 184.7v1.2M42.2 192.9l.4-.4v1.3"/>
<path d="M42.2 193.8h.7M43.3 184.7v1.2l-.7-1.2v1.2M46.2 181.9h4.3v.5h-4.3zM46.2 183.3h4.3v.5h-4.3zM46.7 180.7h1M47.2 180.2v1M47.5 190.6l-.3-.1-.4 .3v.6l.2 .3h.5v-.5h-.2M48.3 186.4v1.2h1.3l-1.3 1.2-1.1-1.2h1.1M48.3 186.4h.1M48.3 183.8v2.6M48.7 190.5v1.2l-.7-1.2v1.2M49.3 190.5l.5 .1 .2 .2v.6l-.2 .3h-.5z"/>
<path d="M51.4 191.2l.6-.1v-.5l-.6-.1v1.2M52.5 190.5l.2 1.2 .3-.9 .2 .9 .3-1.2M52.6 182.5l-.3 .8h.7M52.8 183v.7M53 180.3a.45 .45 0 0 0-.7 .1v.7a.45 .45 0 0 0 .7 .2M53.3 182.5h.9l-.5 1.2M53.5 180.5l.3-.3v1.2M53.5 181.4h.7M53.9 191.2h.5l.2-.2v-.3l-.2-.2h-.5v1.2M54.3 191.2l.3 .5M54.6 183v1.1M54.7 180.3l.3-.1a.78 .78 0 0 1 0 1.2l-.3-.1z"/>
<path d="M54.9 191.9h.9M55.2 183.6l.2 .1M55.2 183v.6l-.2 .1-.4-.1M55.5 186.4v1.2l1 .6-1 .6-.9-.6 .9-.6M55.5 186.4h.1M55.9 183.1h.4M56 191.1h.5M56.5 182.5h-.6v1.2M56.6 190.5h-.6v1.2M57.1 190.5v1.2h.6M57.8 191.7l.5-1.2 .4 1.2M58 191.3h.5"/>
<path d="M59.7 190.6l-.1-.1a.66 .66 0 0 0-.6 .5 .66 .66 0 0 0 .3 .7l.5-.1v-.4h-.3M61.2 184.1l-1.3-.5v.8M61.5 187.6v1.2h1.2l-1.2 1.2-1.2-1.2h1.2M61.5 187.6h.1M61.5 181.6v6M63.9 187l-.1-.1a.66 .66 0 0 0-.5 .5 .66 .66 0 0 0 .2 .7l.5-.1v-.4h-.2M65.2 186.9v1.2l-.7-1.2v1.2M65.4 192.3v1.8M65.8 186.9a.66 .66 0 0 1 .6 .5 .66 .66 0 0 1-.2 .7h-.4zM80.3 184.1l-1.2-.5v.8M80.6 187.6v1.2h1.2l-1.2 1.2-1.2-1.2h1.2M80.6 187.6h.1"/>
<path d="M80.6 181.6v6M83 187a.59 .59 0 0 0-.7 .4 .59 .59 0 0 0 .3 .7l.5-.1v-.4h-.3M84.2 186.9v1.2l-.6-1.2v1.2M84.8 186.9a.66 .66 0 0 1 .7 .5 .66 .66 0 0 1-.2 .7h-.5zM89.2 192.7l.1-.2h.4l.1 .2v.3l-.7 .8h.7M98.6 183.9l.2-.2 .5 .1v.4l-.2 .2h-.2l-.3-.3v-.4l-.5 .2v.2l.3 .3 .2-.3M99.7 187.6v1.2h1.1l-1.1 1.2-1.2-1.2h1.2M99.7 187.6h.1M99.7 181.6v6M102.1 186.5h-.5l-.2 .3v.6l.2 .2h.5v-.4h-.2M102.8 183.1h.7l-.5 1.2M103.4 186.5v1.2l-.8-1.2v1.2"/>
<path d="M103.9 186.5h.5l.2 .3v.6l-.4 .3h-.3zM104.3 183l-.3 .9h.7M104.6 183.6v.7M105.2 183.1v1.2M105.2 183.7h.6M105.8 183.1v1.2M107.1 183.2a.55 .55 0 0 0-.8 .5 .55 .55 0 0 0 .8 .5M107.5 183.5l.4-.4v1.2M107.5 184.3h.7M108.6 183.1h.8l-.4 .5h.3v.6h-.7M110.5 183.6l-.2 .3h-.2l-.3-.3 .1-.4h.6v.9l-.5 .2M112.4 192.3v1.8"/>
<path d="M112.8 184.1h11.9M116.3 181.6h8.4M116.8 180h.4a.66 .66 0 0 1 .2 .8 .66 .66 0 0 1-.6 .4zM117.9 180.3l.3-.3v1.2M117.9 181.2h.6M119.5 180.3v.9M121.9 180.2h.8l-.4 .4 .4 .2-.1 .5-.5 .1-.2-.2M121.9 182.5h.8l-.4 .5 .4 .2-.1 .4-.5 .1-.2-.1M123.1 180.5l.3-.3v1.2M123.1 182.5h.7l-.4 .5h.4v.6l-.2 .1h-.3l-.2-.1M123.1 181.4h.7M124.7 181.5h1.2v.3h-1.2z"/>
<path d="M124.7 183.9h1.2v.2h-1.2zM127.1 188.8v1.2h1.2l-1.2 1.2-1.2-1.2h1.2M127.1 188.8h.1M127.1 187.6v1.2M128.3 181.5h1.2v.3h-1.2zM128.3 183.9h1.2v.2h-1.2zM129.5 181.6h9.5M129.5 184.1h11.9M130.2 188.7l-.2-.1a.61 .61 0 0 0-.5 .7 .61 .61 0 0 0 .5 .5l.3-.1v-.4h-.3M130.3 180.2h.8l-.5 .4 .4 .1 .1 .4-.3 .3h-.3l-.2-.2M130.3 182.5h.8l-.5 .5h.4l.1 .5-.3 .2h-.3l-.2-.1M131.5 180.3l.6-.1 .1 .3-.8 .9h.8"/>
<path d="M131.5 188.6v1.2l-.7-1.2v1.2M131.7 182.5l-.2 .8h.7M132.1 188.6a.6 .6 0 0 1 .7 .6 .6 .6 0 0 1-.7 .6zM132.1 182.9v.8M134.6 180h.4a.66 .66 0 0 1 .3 .8 .66 .66 0 0 1-.7 .4zM135.7 180.3l.4-.3v1.2M135.7 181.2h.7M136.1 192.5h.7l-.4 .5 .4 .2v.3l-.2 .3h-.4l-.1-.2M137.5 180h-.6v.5h.6l.1 .4-.3 .3-.4-.2M150.1 180v1.2M151.4 180v1.2l-.7-1.2v1.2M151.7 180l.4 1.2 .5-1.2"/>
<path d="M152.7 181.3h.9M153.8 180.2l.2-.2h.4a.86 .86 0 0 1-.1 1.2l-.5-.2zM155.1 180v.9l.3 .3 .4-.3v-.9M156.2 180h.7M156.5 180v1.2M159.3 192.3v1.8M159.6 184.7a.45 .45 0 0 0-.7 .1v.7a.45 .45 0 0 0 .7 .2v-.4h-.2M160.4 180.4v1.2h1.2l-1.2 1.2-1.1-1.2h1.1M160.4 180.4h.1M160.8 184.6v1.2l-.7-1.2v1.2M161.4 184.6l.6 .1 .1 .4-.1 .5-.4 .2h-.2zM166.3 180.1l-.5-.1a.67 .67 0 0 0-.3 .7 .67 .67 0 0 0 .5 .5l.3-.2"/>
<path d="M167.5 180l-.7 .1v.3l.7 .4-.3 .4-.4-.1M167.8 180h.8l-.5 .4 .5 .3-.1 .4-.5 .1-.2-.2M175.3 189h101.3M175.3 186.2h101.3M175.3 182.4h101.3M176.6 189.6v1.3M176.6 180.6h.4M176.8 190.2l.6 .7M177.3 186.9h-.6l-.2 .3 .2 .3 .6 .3v.4h-.8M177.4 189.6l-.8 .7M177.8 180.4v1M178 189.6v.1"/>
<path d="M178 186.9v.1M178 187.4v.9M178 190v.9M178.5 187.4h.7l-.7 .9h.7M179.2 180.9l.6-.1-.1-.3-.4-.1-.1 .2v.6l.1 .2 .4-.1M179.5 189.7l-.6-.1a.7 .7 0 0 0-.3 .9 .7 .7 0 0 0 .9 .3M179.7 187.9l.6-.2-.1-.3-.5 .1v.6l.2 .2 .4-.1M180.1 190.1l.4-.1 .2 .2v.7M180.4 181.2v.2M180.4 180.5v.1M180.7 190.3l-.7 .3 .2 .3 .5-.1M180.9 188.2v.1"/>
<path d="M180.9 187.5h.1M181.9 190.1l-.4-.1-.2 .2 .1 .6h.5M181.9 189.6v1.3M181.9 180.4h.6M182.5 188.3l.5-1.4 .5 1.4M182.6 187.9h.7M183 180.4v.8l.1 .2 .5-.2M183.4 192.4l-.4 1h.8M183.6 180.4v1M183.6 193v.8M183.7 190.2h.5M184.2 186.9l-.4 1h.9"/>
<path d="M184.2 180.4v1M184.4 189.6h-.7v1.3h.7M184.5 187.4v.9M184.7 180.4l-.5 .3M185 190.8v.1M185.1 180.5l.4-.1 .3 .3-.1 .6h-.6M185.7 189.6h.5l.2 .1v1.1l-.4 .1h-.3zM186.4 180.6l.2-.2 .3 .1v.8l-.3 .1-.2-.2zM187 190.8v.1M187.5 190.9l.5-1.3 .5 1.3M187.6 190.5h.7M187.8 180.8l.4 .6"/>
<path d="M188.2 180.4l-.6 .5M188.8 180.4v1M188.9 190.8v.1M189.2 180.4h.6M189.9 181.5h1.1M191.3 180.4v1M191.4 190.2l-.2 .2h-.4l-.2-.2 .2-.6 .5 .1a.97 .97 0 0 1-.3 1.2h-.2M191.8 180.4l-.5 .3M192 190.8v.1M192.1 180.9l.7-.1v-.3l-.2-.1-.5 .2v.6l.3 .2 .4-.1M192.8 189.6a.69 .69 0 0 1 .7 .4 .69 .69 0 0 1-.3 .8l-.1 .1a.84 .84 0 0 1-.3-1.3zM193.5 180.5l.3-.1 .3 .2v.6l-.3 .2-.3-.1"/>
<path d="M193.5 180.4v1.5M194 186.2v2.8M194.1 190.8v.1M194.6 189.7l.7-.1 .1 .6-.8 .7h.8M195.4 180.4v1M196.7 180.5a.45 .45 0 0 0-.7 .2v.4a.45 .45 0 0 0 .7 .2M197.3 186.9h.5l.2 .2v1l-.4 .2h-.3zM197.3 180.5l.4-.1 .3 .2v.8M198 180.8l-.7 .1v.4h.7M198.6 187.5h.6v.8M198.6 181.2v.2M199.2 187.7l-.6 .2v.3h.6"/>
<path d="M199.4 180.8l.4 .6M199.7 187.4h.5M199.8 180.4l-.6 .5M199.9 186.9v1.2l.3 .2M200.4 180.4v1M200.7 187.9l.6-.2-.1-.3h-.4l-.1 .1v.6l.1 .2 .5-.1M201.7 180.5l-.4-.1-.3 .3v.4l.3 .3 .4-.1M201.9 188.2v.1M201.9 187.5h.1M202.3 180.5l.4-.1 .2 .2v.8M202.9 180.8l-.7 .2 .2 .4 .5-.1M203.6 187l.7-.1 .1 .6-.9 .8h.9"/>
<path d="M204.1 180.5a.45 .45 0 0 0-.6 .2v.4a.45 .45 0 0 0 .6 .2M204.5 181.5h1.1M205.1 187h.6v1.2h-.6zM206.2 192.3v1.8M206.3 187l.7-.1 .1 .4-.9 1h.9M206.3 180.5l-.3-.1-.2 .3 .2 .2h.3l.1 .3-.2 .2-.4-.1M207.6 180.5l-.3-.1-.3 .2v.6l.3 .2 .3-.1M208.3 186.9h-.4a.93 .93 0 0 0-.1 1.3h.6v-.5l-.2-.2h-.5l-.1 .2M208.3 180.6l.1-.2 .5 .2v.8M209 187.8h1.1M210.9 186.9h.4l.2 .3v.8l-.3 .3-.4-.1-.1-.4zM212.8 186.9h-.6l-.1 .6h.7v.7h-.7"/>
<path d="M213.4 187.8h1.1M215.1 187.3l.5-.4v1.4M215.1 188.3h.9M216.4 186.9h.9l-.6 1.4M230.6 192.5h-.6v.6l.5-.1 .2 .2v.3l-.2 .3-.5-.2M253.2 192.3v1.8M254.1 186.2v6.1M256.4 189.6v1.3M257.6 190.1a.45 .45 0 0 0-.6 .1v.6h.6M257.6 189.6v1.3M258.3 190.8v.1M258.3 190.1v.1"/>
<path d="M260 189.9l.4-.3v1.3M260 190.9h.9M262.5 189.5l-1.3 1.8M262.8 189.9l.4-.3v1.3M262.8 190.9h.9M277.5 192.5h-.2a.93 .93 0 0 0-.3 1.2l.5 .1 .1-.2v-.5l-.6-.1-.1 .2"/>
<circle cx="131.2" cy="87.5" r=".64"/>
<circle cx="213.5" cy="99.4" r=".64"/>
<circle cx="229" cy="92.2" r=".64"/>
<circle cx="229" cy="94.6" r=".64"/>
<circle cx="229" cy="99.4" r=".64"/>
<circle cx="229" cy="96.9" r=".64"/>
<circle cx="250.5" cy="99.4" r=".64"/>
<circle cx="262.5" cy="96.9" r=".58"/>
<circle cx="262.5" cy="94.5" r=".58"/>
<circle cx="266" cy="92.2" r=".64"/>
<circle cx="266" cy="96.9" r=".64"/>
<circle cx="266" cy="94.6" r=".64"/>
<circle cx="266" cy="99.4" r=".64"/>
<circle cx="41.8" cy="133.9" r=".64"/>
<circle cx="89.5" cy="129.2" r=".64"/>
<circle cx="81.2" cy="150.6" r=".64"/>
</g>
<g fill="none" stroke="#000" stroke-width=".25">
<path d="M30.7 33.8h4.5v19.1h-4.5zM31.1 34.4h3.6v1.2h-3.6zM31.1 36.8h3.6v1.2h-3.6zM31.1 39.2h3.6v1.1h-3.6zM56.8 31.5h4.7v38.1h-4.7zM75.6 35.8h2.8M142.4 28.6h2.8M181.7 28.6h2.9M221.1 28.6h2.9M260.5 28.6h2.8M31.1 41.6h3.6v1.2h-3.6zM31.1 44h3.6v1.2h-3.6z"/>
<path d="M31.1 46.4h3.6v1.1h-3.6zM31.1 48.7h3.6v1.2h-3.6zM31.1 51.1h3.6v1.2h-3.6zM93.5 40.5h2.9M30.7 60.1h4.5v19h-4.5zM31.1 60.7h3.6v1.1h-3.6zM31.1 63h3.6v1.2h-3.6zM31.1 65.4h3.6v1.2h-3.6zM31.1 67.8h3.6v1.2h-3.6zM31.1 70.2h3.6v1.2h-3.6zM31.1 72.6h3.6v1.2h-3.6zM31.1 75h3.6v1.2h-3.6z"/>
<path d="M31.1 77.3h3.6v1.2h-3.6zM56.8 79.1h4.7v38.2h-4.7zM97.4 79.1h4.6v19.2h-4.6zM97.9 79.7h3.6v1.2h-3.6zM30.7 86.3h4.5v19.1h-4.5zM31.1 86.9h3.6v1.2h-3.6zM31.1 89.3h3.6v1.2h-3.6zM31.1 91.7h3.6v1.1h-3.6zM31.1 94h3.6v1.2h-3.6zM31.1 96.4h3.6v1.2h-3.6zM31.1 98.8h3.6v1.2h-3.6zM75.6 82.3h2.8"/>
<path d="M97.9 82.1h3.6v1.2h-3.6zM97.9 84.5h3.6v1.2h-3.6zM97.9 86.9h3.6v1.2h-3.6zM97.9 89.3h3.6v1.2h-3.6zM97.9 91.7h3.6v1.1h-3.6zM97.9 94h3.6v1.2h-3.6zM97.9 96.4h3.6v1.2h-3.6zM127.1 83.9h-3.5v7.2h3.5M127.1 83.9a3.6 3.6 0 0 1 3.6 3.6 3.6 3.6 0 0 1-3.6 3.6M132.5 98.3l-3-.1a6.1 6.1 0 0 1 0 7.2h3M132.5 98.2a4.8 4.8 0 0 1 4.1 3.6M141.4 81.5h3"/>
<path d="M141.4 88.7h3M141.4 81.6a6.2 6.2 0 0 1 0 7.1M144.4 81.5a4.8 4.8 0 0 1 4.2 3.6M148.6 85.1a4.8 4.8 0 0 1-4.1 3.6M151.6 92.2h-3a6.2 6.2 0 0 1 0 7.2M151.6 92.3a4.8 4.8 0 0 1 4.2 3.5 4.9 4.9 0 0 1-4.2 3.6h-3.1M180.9 88.7h4.6v9.6h-4.6zM181.4 89.3h3.6v1.2h-3.6zM181.4 91.7h3.6v1.1h-3.6zM181.4 94h3.6v1.2h-3.6zM181.4 96.4h3.6v1.2h-3.6zM214.2 89.9h14.3v11.9h-14.3z"/>
<path d="M251.2 89.9h14.3v11.9h-14.3zM31.1 101.2h3.6v1.2h-3.6zM31.1 103.6h3.6v1.2h-3.6zM97.4 105.4h4.6v19h-4.6zM97.9 106h3.6v1.1h-3.6zM97.9 108.3h3.6v1.2h-3.6zM97.9 110.7h3.6v1.2h-3.6zM97.9 113.2h3.6v1.1h-3.6zM97.9 115.5h3.6v1.2h-3.6zM97.9 117.9h3.6v1.2h-3.6zM136.7 101.8a4.9 4.9 0 0 1-4.2 3.6M170.7 109.9v2.8"/>
<path d="M203 109.9v2.8M235.2 109.9v2.8M267.3 109.9v2.8M34.1 130.4h3.6a3.6 3.6 0 0 1 3.6 3.6 3.6 3.6 0 0 1-3.6 3.5h-3.6zM50.6 125.2h2.9M85.4 132.8h-3.6v-7.2h3.6a3.6 3.6 0 0 1 3.6 3.6 3.6 3.6 0 0 1-3.6 3.6M97.9 120.3h3.6v1.2h-3.6zM97.9 122.6h3.6v1.2h-3.6zM103.3 138.7h3M103.3 138.8a6.2 6.2 0 0 1 0 7.1h3M106.3 138.8a4.8 4.8 0 0 1 4.2 3.5M128.1 125.2h2.8"/>
<path d="M51.8 150.2h2.9M82.9 148.2a3.5 3.5 0 0 1 2.5-1.1h3.5v7.1h-3.5a3.6 3.6 0 0 1-3.3-2.2 3.6 3.6 0 0 1 .8-3.8zM110.4 142.4a4.9 4.9 0 0 1-4.1 3.5M124.8 144.7h4.7v40.6h-4.7zM56.8 167.3h9.5v14.4h-9.5zM68.5 163.3h2.8M75.8 167.3h9.6v14.4h-9.6zM87.5 163.3h2.9M95 167.3h9.4v14.4h-9.4zM105.5 163.3h2.7M176.7 174.6h.4l.4 .4v.7l-.4 .4h-.4zM178.1 175.1h.6l.1 1"/>
<path d="M178.8 175.5l-.7 .1v.4h.7M179.3 175.1l.3 1 .4-1M180.5 174.6v.2M180.5 175.1v1M181.7 175.1h-.5l-.1 .3v.4l.2 .3 .4-.1M181.7 174.6v1.5M182.3 175.6l.7-.1-.1-.4h-.5l-.1 .2 .1 .7h.5M184.7 175.3h.5l.3-.4-.3-.3h-.5v1.5h.5l.3-.3v-.2l-.3-.3M186.1 175.1v.9l.4 .1 .2-.2M186.7 175.1v1M188 175.1h-.5l-.2 .3v.4l.3 .3 .4-.1M189.2 175.1h-.5l-.2 .3v.4l.3 .3 .4-.1"/>
<path d="M189.8 174.6v.2M189.8 175.1v1M256.5 187.7l.8-.1a.45 .45 0 0 0-.2-.7h-.6v1.4M256.8 187.7l.5 .6M257.9 187.9l.6-.2-.1-.3-.5 .2v.6l.2 .1h.3M259 187.4l.4 .9 .3-.9M260.2 188.2v.1M260.2 187.5v.1M262 187.1l.3-.2 .4 .3v.9l-.4 .2a.82 .82 0 0 1-.3-1.2zM263.3 188.2v.1M263.9 187.1l.2-.2h.4l.2 .4-.8 1h.8"/>
<circle cx="91.3" cy="30.3" r="2.67"/>
<circle cx="60.3" cy="144.7" r="2.67"/>
</g>
<g fill="none" stroke="#000" stroke-width=".34">
<path d="M75.6 36.7h2.8M142.3 29.5h2.9M181.7 29.5h2.9M221.1 29.5h2.8M260.4 29.5h2.8M93.5 41.4h2.9M75.6 83.1h2.8M171.7 109.9v2.8M203.9 109.9v2.8M236.1 109.9v2.8M268.3 109.9v2.8M50.5 126.1h2.9"/>
<path d="M128 126.1h2.9M51.7 151.1h2.9M68.4 164.3h2.9M87.5 164.3h2.8M105.4 164.3h2.8M176.8 183h1.1M177.4 183l-.3 1.9M178.4 183.7l-.1 1.2M178.5 183v.2M179.1 183.7h.6M179.4 183l-.2 1.8 .4 .1M180.5 183l-.2 1.7 .2 .2"/>
<path d="M181.2 184.3l.9-.2v-.3l-.6-.1-.2 .3v.8h.6M182.9 184.7l.1 .1-.2 .1 .1-.2-.1 .2M183 183.8v.2M186.4 183.1a1.02 1.02 0 0 0-1.1 .5 1.02 1.02 0 0 0 .1 1.2l.4 .1 .5-.2 .1-.6h-.4M187 184.3l1-.2-.1-.3h-.7l-.3 .9 .3 .2 .6-.1M188.8 183.9l.3-.2 .4 .1v1.1M188.8 183.7l-.2 1.2M189.6 184a.47 .47 0 0 1 .4-.3 .47 .47 0 0 1 .4 .3l-.2 .9M192.5 183h1.1M193.1 183l-.2 1.9M194.1 183.7v1.1l.5 .1 .2-.2M195 183.7l-.2 1.2"/>
<path d="M195.8 183.7l-.1 1.2M196.4 183.7l-.4 .1-.2 .3M197 183.8l.5-.1 .3 .2v.7l-.4 .3-.5-.1M197.1 183l-.2 1.9M198.7 183.9l.3-.2 .5 .1 .1 .3-.3 .7-.4 .1-.3-.2zM200.5 183l-.3 1.9M200.6 184.2l.4 .7M201.2 183.7l-.9 .7M201.9 183.7l-.1 1.2M202 183v.2M202.6 183.7h.7M202.9 183l-.2 1.7 .4 .2"/>
<path d="M205.3 183.7l-.1 1.2M205.9 183.7l-.4 .1-.2 .3M206.3 184.3l1-.2-.1-.3h-.7l-.2 .9 .2 .2 .6-.1M208.1 183.8l.5-.1 .4 .4-.3 .7h-.8M208.1 183.7l-.2 1.9M209.9 183l-.2 1.7 .2 .2M210.8 183.7l-.1 1.2M210.9 183l-.1 .2 .2-.1-.1-.1-.1 .2M212.5 183.8l-.5-.1-.4 .4v.6l.2 .2 .5-.1M213.3 183.8h.7v1.1M214 184.1l-.8 .2a.36 .36 0 0 0 .2 .6l.6-.1M215 184.8l-.3 .5"/>
<path d="M217.2 183.7l.2 1.2 .6-1.2M218.6 184.7v.2M220.8 184.9h1.1M221 183.6h.2l.4-.6-.2 1.9M222.8 184.7v.2M223.5 184.9h1.1M223.7 183.6l.6-.6-.3 1.9"/>
</g>
<path d="M91.9 28.4v3.6M59.7 142.9v3.6" fill="none" stroke="#000" stroke-width=".51"/>
<g fill="#000">
<path d="M90.4 28.6l.5-.5 .4 1zM99.9 41.4h4.3v.5h-4.3zM30.5 120.7h.8v.3h-.8zM30.5 123.1h.8v.3h-.8zM29.3 144.5h.8v.3h-.8zM29.3 147h.8v.2h-.8zM29.3 149.4h.8v.2h-.8zM29.3 151.7h.8v.3h-.8zM29.3 154.1h.8v.2h-.8zM29.3 156.5h.8v.2h-.8zM29.3 158.8h.8v.3h-.8zM60.3 146.3l.5-.4 .5 .9z"/>
<path d="M29.3 174.3h.8v.3h-.8zM29.3 176.8h.8v.2h-.8zM29.3 179.2h.8v.2h-.8zM29.3 161.3h.8v.2h-.8zM29.3 163.7h.8v.2h-.8zM147.6 171.6h1.9v1h-1.9zM147.8 170.4a.97 .97 0 0 1 1.1-.2 .97 .97 0 0 1 .6 .9h-2zM147.5 173.1h2a.97 .97 0 0 1-1 .9 .97 .97 0 0 1-1-.9zM159.5 171.6h2v1h-2zM159.8 170.4a.97 .97 0 0 1 1-.2 .97 .97 0 0 1 .6 .9h-1.9zM159.5 173.1h1.9a.97 .97 0 0 1-1 .9 .97 .97 0 0 1-.9-.9zM170.3 171.6h1.8v1h-1.8z"/>
<path d="M170.5 170.5a.93 .93 0 0 1 1.1-.2 .93 .93 0 0 1 .5 .8h-1.8zM170.3 173.1h1.8a.93 .93 0 0 1-.9 .9 .93 .93 0 0 1-.9-.9zM29.3 181.5h.8v.3h-.8zM29.3 183.9h.8v.3h-.8zM29.3 186.3h.8v.2h-.8zM46.2 183.3h4.3v.5h-4.3z"/>
<circle cx="77" cy="32.6" r=".47"/>
<circle cx="90.1" cy="37.3" r=".47"/>
<circle cx="90.1" cy="35" r=".47"/>
<circle cx="94.9" cy="37.3" r=".47"/>
<circle cx="102" cy="37.3" r=".47"/>
<circle cx="140.2" cy="26.6" r=".47"/>
<circle cx="179.6" cy="26.6" r=".47"/>
<circle cx="218.9" cy="26.6" r=".47"/>
<circle cx="258.2" cy="26.6" r=".47"/>
<circle cx="187.9" cy="75.5" r=".47"/>
<circle cx="196.3" cy="79.1" r=".47"/>
<circle cx="199.8" cy="75.5" r=".47"/>
<circle cx="227.2" cy="75.5" r=".47"/>
<circle cx="77" cy="80.3" r=".47"/>
<circle cx="117.5" cy="85.1" r=".47"/>
<circle cx="117.5" cy="89.8" r=".47"/>
<circle cx="192.7" cy="82.6" r=".47"/>
<circle cx="175.9" cy="111.3" r=".47"/>
<circle cx="208.2" cy="111.3" r=".47"/>
<circle cx="240.4" cy="111.3" r=".47"/>
<circle cx="272.5" cy="111.3" r=".47"/>
<circle cx="28.1" cy="133.9" r=".47"/>
<circle cx="52" cy="120.8" r=".47"/>
<circle cx="61.5" cy="138.7" r=".47"/>
<circle cx="96.1" cy="139.9" r=".47"/>
<circle cx="125.9" cy="120.8" r=".47"/>
<circle cx="53.2" cy="144.7" r=".47"/>
<circle cx="74.6" cy="150.6" r=".47"/>
<circle cx="134.2" cy="148.3" r=".47"/>
<circle cx="134.2" cy="150.6" r=".47"/>
<circle cx="48.3" cy="179.2" r=".47"/>
<circle cx="61.5" cy="161.4" r=".47"/>
<circle cx="80.6" cy="161.4" r=".47"/>
<circle cx="99.7" cy="161.4" r=".47"/>
<circle cx="112.8" cy="162.6" r=".47"/>
<circle cx="160.4" cy="162.6" r=".47"/>
<circle cx="48.3" cy="186.4" r=".47"/>
<circle cx="112.8" cy="184.1" r=".47"/>
<circle cx="127.1" cy="187.6" r=".47"/>
<circle cx="141.4" cy="184.1" r=".47"/>
</g>
<g fill="none" stroke="#000" stroke-width="1.2">
<circle cx="26.9" cy="21.8" r="1.23"/>
<circle cx="87.7" cy="60" r="1.23"/>
<circle cx="25.7" cy="110.1" r="1.23"/>
<circle cx="77" cy="113.7" r="1.23"/>
<circle cx="137.8" cy="112.5" r="1.23"/>
</g>
</svg>
